VERSION 5.8 ;
BUSBITCHARS "[]" ;
DIVIDERCHAR "/" ;
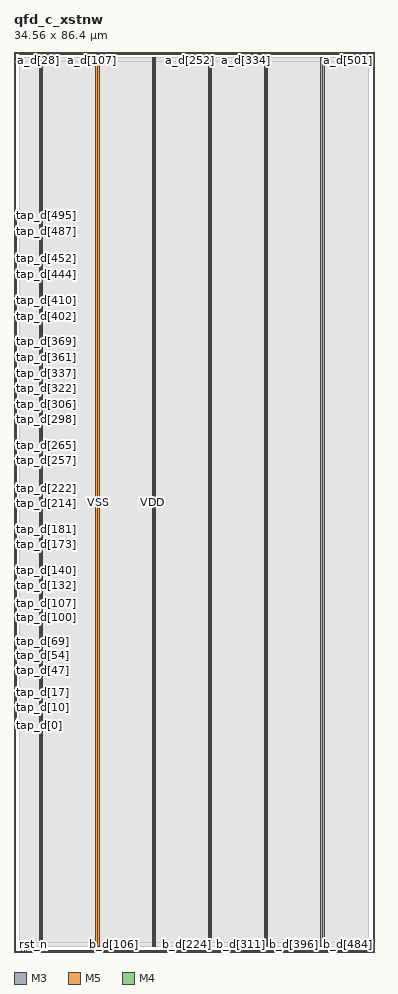
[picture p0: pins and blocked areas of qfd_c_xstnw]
MACRO qfd_c_xstnw
  CLASS BLOCK ;
  ORIGIN 0 0 ;
  FOREIGN qfd_c_xstnw 0 0 ;
  SIZE 34.56 BY 86.4 ;
  SYMMETRY X Y ;
  PIN b_d[0]
    DIRECTION INPUT ;
    USE SIGNAL ;
    PORT
      LAYER M3 ;
        RECT 3.273 0.000 3.297 0.192 ;
    END
  END b_d[0]
  PIN b_d[1]
    DIRECTION INPUT ;
    USE SIGNAL ;
    PORT
      LAYER M5 ;
        RECT 3.312 0.000 3.336 0.192 ;
    END
  END b_d[1]
  PIN b_d[2]
    DIRECTION INPUT ;
    USE SIGNAL ;
    PORT
      LAYER M3 ;
        RECT 3.381 0.000 3.405 0.192 ;
    END
  END b_d[2]
  PIN b_d[3]
    DIRECTION INPUT ;
    USE SIGNAL ;
    PORT
      LAYER M5 ;
        RECT 3.456 0.000 3.480 0.192 ;
    END
  END b_d[3]
  PIN b_d[4]
    DIRECTION INPUT ;
    USE SIGNAL ;
    PORT
      LAYER M3 ;
        RECT 3.489 0.000 3.513 0.192 ;
    END
  END b_d[4]
  PIN b_d[5]
    DIRECTION INPUT ;
    USE SIGNAL ;
    PORT
      LAYER M5 ;
        RECT 3.552 0.000 3.576 0.192 ;
    END
  END b_d[5]
  PIN b_d[6]
    DIRECTION INPUT ;
    USE SIGNAL ;
    PORT
      LAYER M3 ;
        RECT 3.633 0.000 3.657 0.192 ;
    END
  END b_d[6]
  PIN b_d[7]
    DIRECTION INPUT ;
    USE SIGNAL ;
    PORT
      LAYER M5 ;
        RECT 3.696 0.000 3.720 0.192 ;
    END
  END b_d[7]
  PIN b_d[8]
    DIRECTION INPUT ;
    USE SIGNAL ;
    PORT
      LAYER M3 ;
        RECT 3.741 0.000 3.765 0.192 ;
    END
  END b_d[8]
  PIN b_d[9]
    DIRECTION INPUT ;
    USE SIGNAL ;
    PORT
      LAYER M5 ;
        RECT 3.792 0.000 3.816 0.192 ;
    END
  END b_d[9]
  PIN b_d[10]
    DIRECTION INPUT ;
    USE SIGNAL ;
    PORT
      LAYER M3 ;
        RECT 3.849 0.000 3.873 0.192 ;
    END
  END b_d[10]
  PIN b_d[11]
    DIRECTION INPUT ;
    USE SIGNAL ;
    PORT
      LAYER M5 ;
        RECT 3.936 0.000 3.960 0.192 ;
    END
  END b_d[11]
  PIN b_d[12]
    DIRECTION INPUT ;
    USE SIGNAL ;
    PORT
      LAYER M3 ;
        RECT 3.957 0.000 3.981 0.192 ;
    END
  END b_d[12]
  PIN b_d[13]
    DIRECTION INPUT ;
    USE SIGNAL ;
    PORT
      LAYER M5 ;
        RECT 4.032 0.000 4.056 0.192 ;
    END
  END b_d[13]
  PIN b_d[14]
    DIRECTION INPUT ;
    USE SIGNAL ;
    PORT
      LAYER M3 ;
        RECT 4.101 0.000 4.125 0.192 ;
    END
  END b_d[14]
  PIN b_d[15]
    DIRECTION INPUT ;
    USE SIGNAL ;
    PORT
      LAYER M5 ;
        RECT 4.176 0.000 4.200 0.192 ;
    END
  END b_d[15]
  PIN b_d[16]
    DIRECTION INPUT ;
    USE SIGNAL ;
    PORT
      LAYER M3 ;
        RECT 4.209 0.000 4.233 0.192 ;
    END
  END b_d[16]
  PIN b_d[17]
    DIRECTION INPUT ;
    USE SIGNAL ;
    PORT
      LAYER M5 ;
        RECT 4.272 0.000 4.296 0.192 ;
    END
  END b_d[17]
  PIN b_d[18]
    DIRECTION INPUT ;
    USE SIGNAL ;
    PORT
      LAYER M3 ;
        RECT 4.317 0.000 4.341 0.192 ;
    END
  END b_d[18]
  PIN b_d[19]
    DIRECTION INPUT ;
    USE SIGNAL ;
    PORT
      LAYER M5 ;
        RECT 4.368 0.000 4.392 0.192 ;
    END
  END b_d[19]
  PIN b_d[20]
    DIRECTION INPUT ;
    USE SIGNAL ;
    PORT
      LAYER M3 ;
        RECT 4.461 0.000 4.485 0.192 ;
    END
  END b_d[20]
  PIN b_d[21]
    DIRECTION INPUT ;
    USE SIGNAL ;
    PORT
      LAYER M5 ;
        RECT 4.512 0.000 4.536 0.192 ;
    END
  END b_d[21]
  PIN b_d[22]
    DIRECTION INPUT ;
    USE SIGNAL ;
    PORT
      LAYER M3 ;
        RECT 4.569 0.000 4.593 0.192 ;
    END
  END b_d[22]
  PIN b_d[23]
    DIRECTION INPUT ;
    USE SIGNAL ;
    PORT
      LAYER M5 ;
        RECT 4.608 0.000 4.632 0.192 ;
    END
  END b_d[23]
  PIN b_d[24]
    DIRECTION INPUT ;
    USE SIGNAL ;
    PORT
      LAYER M3 ;
        RECT 4.677 0.000 4.701 0.192 ;
    END
  END b_d[24]
  PIN b_d[25]
    DIRECTION INPUT ;
    USE SIGNAL ;
    PORT
      LAYER M5 ;
        RECT 4.752 0.000 4.776 0.192 ;
    END
  END b_d[25]
  PIN b_d[26]
    DIRECTION INPUT ;
    USE SIGNAL ;
    PORT
      LAYER M3 ;
        RECT 4.821 0.000 4.845 0.192 ;
    END
  END b_d[26]
  PIN b_d[27]
    DIRECTION INPUT ;
    USE SIGNAL ;
    PORT
      LAYER M5 ;
        RECT 4.848 0.000 4.872 0.192 ;
    END
  END b_d[27]
  PIN b_d[28]
    DIRECTION INPUT ;
    USE SIGNAL ;
    PORT
      LAYER M3 ;
        RECT 4.929 0.000 4.953 0.192 ;
    END
  END b_d[28]
  PIN b_d[29]
    DIRECTION INPUT ;
    USE SIGNAL ;
    PORT
      LAYER M5 ;
        RECT 4.992 0.000 5.016 0.192 ;
    END
  END b_d[29]
  PIN b_d[30]
    DIRECTION INPUT ;
    USE SIGNAL ;
    PORT
      LAYER M3 ;
        RECT 5.037 0.000 5.061 0.192 ;
    END
  END b_d[30]
  PIN b_d[31]
    DIRECTION INPUT ;
    USE SIGNAL ;
    PORT
      LAYER M5 ;
        RECT 5.088 0.000 5.112 0.192 ;
    END
  END b_d[31]
  PIN b_d[32]
    DIRECTION INPUT ;
    USE SIGNAL ;
    PORT
      LAYER M3 ;
        RECT 5.181 0.000 5.205 0.192 ;
    END
  END b_d[32]
  PIN b_d[33]
    DIRECTION INPUT ;
    USE SIGNAL ;
    PORT
      LAYER M5 ;
        RECT 5.232 0.000 5.256 0.192 ;
    END
  END b_d[33]
  PIN b_d[34]
    DIRECTION INPUT ;
    USE SIGNAL ;
    PORT
      LAYER M3 ;
        RECT 5.289 0.000 5.313 0.192 ;
    END
  END b_d[34]
  PIN b_d[35]
    DIRECTION INPUT ;
    USE SIGNAL ;
    PORT
      LAYER M5 ;
        RECT 5.328 0.000 5.352 0.192 ;
    END
  END b_d[35]
  PIN b_d[36]
    DIRECTION INPUT ;
    USE SIGNAL ;
    PORT
      LAYER M3 ;
        RECT 5.397 0.000 5.421 0.192 ;
    END
  END b_d[36]
  PIN b_d[37]
    DIRECTION INPUT ;
    USE SIGNAL ;
    PORT
      LAYER M5 ;
        RECT 5.472 0.000 5.496 0.192 ;
    END
  END b_d[37]
  PIN b_d[38]
    DIRECTION INPUT ;
    USE SIGNAL ;
    PORT
      LAYER M3 ;
        RECT 5.541 0.000 5.565 0.192 ;
    END
  END b_d[38]
  PIN b_d[39]
    DIRECTION INPUT ;
    USE SIGNAL ;
    PORT
      LAYER M5 ;
        RECT 5.568 0.000 5.592 0.192 ;
    END
  END b_d[39]
  PIN b_d[40]
    DIRECTION INPUT ;
    USE SIGNAL ;
    PORT
      LAYER M3 ;
        RECT 5.649 0.000 5.673 0.192 ;
    END
  END b_d[40]
  PIN b_d[41]
    DIRECTION INPUT ;
    USE SIGNAL ;
    PORT
      LAYER M5 ;
        RECT 5.712 0.000 5.736 0.192 ;
    END
  END b_d[41]
  PIN b_d[42]
    DIRECTION INPUT ;
    USE SIGNAL ;
    PORT
      LAYER M3 ;
        RECT 5.757 0.000 5.781 0.192 ;
    END
  END b_d[42]
  PIN b_d[43]
    DIRECTION INPUT ;
    USE SIGNAL ;
    PORT
      LAYER M5 ;
        RECT 5.808 0.000 5.832 0.192 ;
    END
  END b_d[43]
  PIN b_d[44]
    DIRECTION INPUT ;
    USE SIGNAL ;
    PORT
      LAYER M3 ;
        RECT 5.865 0.000 5.889 0.192 ;
    END
  END b_d[44]
  PIN b_d[45]
    DIRECTION INPUT ;
    USE SIGNAL ;
    PORT
      LAYER M5 ;
        RECT 5.952 0.000 5.976 0.192 ;
    END
  END b_d[45]
  PIN b_d[46]
    DIRECTION INPUT ;
    USE SIGNAL ;
    PORT
      LAYER M3 ;
        RECT 6.009 0.000 6.033 0.192 ;
    END
  END b_d[46]
  PIN b_d[47]
    DIRECTION INPUT ;
    USE SIGNAL ;
    PORT
      LAYER M5 ;
        RECT 6.048 0.000 6.072 0.192 ;
    END
  END b_d[47]
  PIN b_d[48]
    DIRECTION INPUT ;
    USE SIGNAL ;
    PORT
      LAYER M3 ;
        RECT 6.117 0.000 6.141 0.192 ;
    END
  END b_d[48]
  PIN b_d[49]
    DIRECTION INPUT ;
    USE SIGNAL ;
    PORT
      LAYER M5 ;
        RECT 6.192 0.000 6.216 0.192 ;
    END
  END b_d[49]
  PIN b_d[50]
    DIRECTION INPUT ;
    USE SIGNAL ;
    PORT
      LAYER M3 ;
        RECT 6.225 0.000 6.249 0.192 ;
    END
  END b_d[50]
  PIN b_d[51]
    DIRECTION INPUT ;
    USE SIGNAL ;
    PORT
      LAYER M5 ;
        RECT 6.288 0.000 6.312 0.192 ;
    END
  END b_d[51]
  PIN b_d[52]
    DIRECTION INPUT ;
    USE SIGNAL ;
    PORT
      LAYER M3 ;
        RECT 6.369 0.000 6.393 0.192 ;
    END
  END b_d[52]
  PIN b_d[53]
    DIRECTION INPUT ;
    USE SIGNAL ;
    PORT
      LAYER M5 ;
        RECT 6.432 0.000 6.456 0.192 ;
    END
  END b_d[53]
  PIN b_d[54]
    DIRECTION INPUT ;
    USE SIGNAL ;
    PORT
      LAYER M3 ;
        RECT 6.477 0.000 6.501 0.192 ;
    END
  END b_d[54]
  PIN b_d[55]
    DIRECTION INPUT ;
    USE SIGNAL ;
    PORT
      LAYER M5 ;
        RECT 6.528 0.000 6.552 0.192 ;
    END
  END b_d[55]
  PIN b_d[56]
    DIRECTION INPUT ;
    USE SIGNAL ;
    PORT
      LAYER M3 ;
        RECT 6.585 0.000 6.609 0.192 ;
    END
  END b_d[56]
  PIN b_d[57]
    DIRECTION INPUT ;
    USE SIGNAL ;
    PORT
      LAYER M5 ;
        RECT 6.672 0.000 6.696 0.192 ;
    END
  END b_d[57]
  PIN b_d[58]
    DIRECTION INPUT ;
    USE SIGNAL ;
    PORT
      LAYER M3 ;
        RECT 6.729 0.000 6.753 0.192 ;
    END
  END b_d[58]
  PIN b_d[59]
    DIRECTION INPUT ;
    USE SIGNAL ;
    PORT
      LAYER M5 ;
        RECT 6.768 0.000 6.792 0.192 ;
    END
  END b_d[59]
  PIN b_d[60]
    DIRECTION INPUT ;
    USE SIGNAL ;
    PORT
      LAYER M3 ;
        RECT 6.837 0.000 6.861 0.192 ;
    END
  END b_d[60]
  PIN b_d[61]
    DIRECTION INPUT ;
    USE SIGNAL ;
    PORT
      LAYER M5 ;
        RECT 6.912 0.000 6.936 0.192 ;
    END
  END b_d[61]
  PIN b_d[62]
    DIRECTION INPUT ;
    USE SIGNAL ;
    PORT
      LAYER M3 ;
        RECT 6.945 0.000 6.969 0.192 ;
    END
  END b_d[62]
  PIN b_d[63]
    DIRECTION INPUT ;
    USE SIGNAL ;
    PORT
      LAYER M5 ;
        RECT 7.008 0.000 7.032 0.192 ;
    END
  END b_d[63]
  PIN b_d[64]
    DIRECTION INPUT ;
    USE SIGNAL ;
    PORT
      LAYER M3 ;
        RECT 7.089 0.000 7.113 0.192 ;
    END
  END b_d[64]
  PIN b_d[65]
    DIRECTION INPUT ;
    USE SIGNAL ;
    PORT
      LAYER M5 ;
        RECT 7.152 0.000 7.176 0.192 ;
    END
  END b_d[65]
  PIN b_d[66]
    DIRECTION INPUT ;
    USE SIGNAL ;
    PORT
      LAYER M3 ;
        RECT 7.197 0.000 7.221 0.192 ;
    END
  END b_d[66]
  PIN b_d[67]
    DIRECTION INPUT ;
    USE SIGNAL ;
    PORT
      LAYER M5 ;
        RECT 7.248 0.000 7.272 0.192 ;
    END
  END b_d[67]
  PIN b_d[68]
    DIRECTION INPUT ;
    USE SIGNAL ;
    PORT
      LAYER M3 ;
        RECT 7.305 0.000 7.329 0.192 ;
    END
  END b_d[68]
  PIN b_d[69]
    DIRECTION INPUT ;
    USE SIGNAL ;
    PORT
      LAYER M5 ;
        RECT 7.392 0.000 7.416 0.192 ;
    END
  END b_d[69]
  PIN b_d[70]
    DIRECTION INPUT ;
    USE SIGNAL ;
    PORT
      LAYER M3 ;
        RECT 7.449 0.000 7.473 0.192 ;
    END
  END b_d[70]
  PIN b_d[71]
    DIRECTION INPUT ;
    USE SIGNAL ;
    PORT
      LAYER M5 ;
        RECT 7.488 0.000 7.512 0.192 ;
    END
  END b_d[71]
  PIN b_d[72]
    DIRECTION INPUT ;
    USE SIGNAL ;
    PORT
      LAYER M3 ;
        RECT 7.557 0.000 7.581 0.192 ;
    END
  END b_d[72]
  PIN b_d[73]
    DIRECTION INPUT ;
    USE SIGNAL ;
    PORT
      LAYER M5 ;
        RECT 7.632 0.000 7.656 0.192 ;
    END
  END b_d[73]
  PIN b_d[74]
    DIRECTION INPUT ;
    USE SIGNAL ;
    PORT
      LAYER M3 ;
        RECT 7.665 0.000 7.689 0.192 ;
    END
  END b_d[74]
  PIN b_d[75]
    DIRECTION INPUT ;
    USE SIGNAL ;
    PORT
      LAYER M5 ;
        RECT 7.728 0.000 7.752 0.192 ;
    END
  END b_d[75]
  PIN b_d[76]
    DIRECTION INPUT ;
    USE SIGNAL ;
    PORT
      LAYER M3 ;
        RECT 7.809 0.000 7.833 0.192 ;
    END
  END b_d[76]
  PIN b_d[77]
    DIRECTION INPUT ;
    USE SIGNAL ;
    PORT
      LAYER M5 ;
        RECT 7.872 0.000 7.896 0.192 ;
    END
  END b_d[77]
  PIN b_d[78]
    DIRECTION INPUT ;
    USE SIGNAL ;
    PORT
      LAYER M3 ;
        RECT 7.917 0.000 7.941 0.192 ;
    END
  END b_d[78]
  PIN b_d[79]
    DIRECTION INPUT ;
    USE SIGNAL ;
    PORT
      LAYER M5 ;
        RECT 7.968 0.000 7.992 0.192 ;
    END
  END b_d[79]
  PIN b_d[80]
    DIRECTION INPUT ;
    USE SIGNAL ;
    PORT
      LAYER M3 ;
        RECT 8.025 0.000 8.049 0.192 ;
    END
  END b_d[80]
  PIN b_d[81]
    DIRECTION INPUT ;
    USE SIGNAL ;
    PORT
      LAYER M5 ;
        RECT 8.112 0.000 8.136 0.192 ;
    END
  END b_d[81]
  PIN b_d[82]
    DIRECTION INPUT ;
    USE SIGNAL ;
    PORT
      LAYER M3 ;
        RECT 8.133 0.000 8.157 0.192 ;
    END
  END b_d[82]
  PIN b_d[83]
    DIRECTION INPUT ;
    USE SIGNAL ;
    PORT
      LAYER M5 ;
        RECT 8.208 0.000 8.232 0.192 ;
    END
  END b_d[83]
  PIN b_d[84]
    DIRECTION INPUT ;
    USE SIGNAL ;
    PORT
      LAYER M3 ;
        RECT 8.277 0.000 8.301 0.192 ;
    END
  END b_d[84]
  PIN b_d[85]
    DIRECTION INPUT ;
    USE SIGNAL ;
    PORT
      LAYER M5 ;
        RECT 8.352 0.000 8.376 0.192 ;
    END
  END b_d[85]
  PIN b_d[86]
    DIRECTION INPUT ;
    USE SIGNAL ;
    PORT
      LAYER M3 ;
        RECT 8.385 0.000 8.409 0.192 ;
    END
  END b_d[86]
  PIN b_d[87]
    DIRECTION INPUT ;
    USE SIGNAL ;
    PORT
      LAYER M5 ;
        RECT 8.448 0.000 8.472 0.192 ;
    END
  END b_d[87]
  PIN b_d[88]
    DIRECTION INPUT ;
    USE SIGNAL ;
    PORT
      LAYER M3 ;
        RECT 8.493 0.000 8.517 0.192 ;
    END
  END b_d[88]
  PIN b_d[89]
    DIRECTION INPUT ;
    USE SIGNAL ;
    PORT
      LAYER M5 ;
        RECT 8.544 0.000 8.568 0.192 ;
    END
  END b_d[89]
  PIN b_d[90]
    DIRECTION INPUT ;
    USE SIGNAL ;
    PORT
      LAYER M3 ;
        RECT 8.637 0.000 8.661 0.192 ;
    END
  END b_d[90]
  PIN b_d[91]
    DIRECTION INPUT ;
    USE SIGNAL ;
    PORT
      LAYER M5 ;
        RECT 8.688 0.000 8.712 0.192 ;
    END
  END b_d[91]
  PIN b_d[92]
    DIRECTION INPUT ;
    USE SIGNAL ;
    PORT
      LAYER M3 ;
        RECT 8.745 0.000 8.769 0.192 ;
    END
  END b_d[92]
  PIN b_d[93]
    DIRECTION INPUT ;
    USE SIGNAL ;
    PORT
      LAYER M5 ;
        RECT 8.784 0.000 8.808 0.192 ;
    END
  END b_d[93]
  PIN b_d[94]
    DIRECTION INPUT ;
    USE SIGNAL ;
    PORT
      LAYER M3 ;
        RECT 8.853 0.000 8.877 0.192 ;
    END
  END b_d[94]
  PIN b_d[95]
    DIRECTION INPUT ;
    USE SIGNAL ;
    PORT
      LAYER M5 ;
        RECT 8.928 0.000 8.952 0.192 ;
    END
  END b_d[95]
  PIN b_d[96]
    DIRECTION INPUT ;
    USE SIGNAL ;
    PORT
      LAYER M3 ;
        RECT 8.997 0.000 9.021 0.192 ;
    END
  END b_d[96]
  PIN b_d[97]
    DIRECTION INPUT ;
    USE SIGNAL ;
    PORT
      LAYER M5 ;
        RECT 9.024 0.000 9.048 0.192 ;
    END
  END b_d[97]
  PIN b_d[98]
    DIRECTION INPUT ;
    USE SIGNAL ;
    PORT
      LAYER M3 ;
        RECT 9.105 0.000 9.129 0.192 ;
    END
  END b_d[98]
  PIN b_d[99]
    DIRECTION INPUT ;
    USE SIGNAL ;
    PORT
      LAYER M5 ;
        RECT 9.168 0.000 9.192 0.192 ;
    END
  END b_d[99]
  PIN b_d[100]
    DIRECTION INPUT ;
    USE SIGNAL ;
    PORT
      LAYER M3 ;
        RECT 9.213 0.000 9.237 0.192 ;
    END
  END b_d[100]
  PIN b_d[101]
    DIRECTION INPUT ;
    USE SIGNAL ;
    PORT
      LAYER M5 ;
        RECT 9.264 0.000 9.288 0.192 ;
    END
  END b_d[101]
  PIN b_d[102]
    DIRECTION INPUT ;
    USE SIGNAL ;
    PORT
      LAYER M3 ;
        RECT 9.357 0.000 9.381 0.192 ;
    END
  END b_d[102]
  PIN b_d[103]
    DIRECTION INPUT ;
    USE SIGNAL ;
    PORT
      LAYER M5 ;
        RECT 9.408 0.000 9.432 0.192 ;
    END
  END b_d[103]
  PIN b_d[104]
    DIRECTION INPUT ;
    USE SIGNAL ;
    PORT
      LAYER M3 ;
        RECT 9.465 0.000 9.489 0.192 ;
    END
  END b_d[104]
  PIN b_d[105]
    DIRECTION INPUT ;
    USE SIGNAL ;
    PORT
      LAYER M5 ;
        RECT 9.504 0.000 9.528 0.192 ;
    END
  END b_d[105]
  PIN b_d[106]
    DIRECTION INPUT ;
    USE SIGNAL ;
    PORT
      LAYER M3 ;
        RECT 9.573 0.000 9.597 0.192 ;
    END
  END b_d[106]
  PIN b_d[107]
    DIRECTION INPUT ;
    USE SIGNAL ;
    PORT
      LAYER M5 ;
        RECT 9.648 0.000 9.672 0.192 ;
    END
  END b_d[107]
  PIN b_d[108]
    DIRECTION INPUT ;
    USE SIGNAL ;
    PORT
      LAYER M3 ;
        RECT 9.717 0.000 9.741 0.192 ;
    END
  END b_d[108]
  PIN b_d[109]
    DIRECTION INPUT ;
    USE SIGNAL ;
    PORT
      LAYER M5 ;
        RECT 9.744 0.000 9.768 0.192 ;
    END
  END b_d[109]
  PIN b_d[110]
    DIRECTION INPUT ;
    USE SIGNAL ;
    PORT
      LAYER M3 ;
        RECT 9.825 0.000 9.849 0.192 ;
    END
  END b_d[110]
  PIN b_d[111]
    DIRECTION INPUT ;
    USE SIGNAL ;
    PORT
      LAYER M5 ;
        RECT 9.888 0.000 9.912 0.192 ;
    END
  END b_d[111]
  PIN b_d[112]
    DIRECTION INPUT ;
    USE SIGNAL ;
    PORT
      LAYER M3 ;
        RECT 9.933 0.000 9.957 0.192 ;
    END
  END b_d[112]
  PIN b_d[113]
    DIRECTION INPUT ;
    USE SIGNAL ;
    PORT
      LAYER M5 ;
        RECT 9.984 0.000 10.008 0.192 ;
    END
  END b_d[113]
  PIN b_d[114]
    DIRECTION INPUT ;
    USE SIGNAL ;
    PORT
      LAYER M3 ;
        RECT 10.041 0.000 10.065 0.192 ;
    END
  END b_d[114]
  PIN b_d[115]
    DIRECTION INPUT ;
    USE SIGNAL ;
    PORT
      LAYER M5 ;
        RECT 10.128 0.000 10.152 0.192 ;
    END
  END b_d[115]
  PIN b_d[116]
    DIRECTION INPUT ;
    USE SIGNAL ;
    PORT
      LAYER M3 ;
        RECT 10.185 0.000 10.209 0.192 ;
    END
  END b_d[116]
  PIN b_d[117]
    DIRECTION INPUT ;
    USE SIGNAL ;
    PORT
      LAYER M5 ;
        RECT 10.224 0.000 10.248 0.192 ;
    END
  END b_d[117]
  PIN b_d[118]
    DIRECTION INPUT ;
    USE SIGNAL ;
    PORT
      LAYER M3 ;
        RECT 10.293 0.000 10.317 0.192 ;
    END
  END b_d[118]
  PIN b_d[119]
    DIRECTION INPUT ;
    USE SIGNAL ;
    PORT
      LAYER M5 ;
        RECT 10.368 0.000 10.392 0.192 ;
    END
  END b_d[119]
  PIN b_d[120]
    DIRECTION INPUT ;
    USE SIGNAL ;
    PORT
      LAYER M3 ;
        RECT 10.401 0.000 10.425 0.192 ;
    END
  END b_d[120]
  PIN b_d[121]
    DIRECTION INPUT ;
    USE SIGNAL ;
    PORT
      LAYER M5 ;
        RECT 10.464 0.000 10.488 0.192 ;
    END
  END b_d[121]
  PIN b_d[122]
    DIRECTION INPUT ;
    USE SIGNAL ;
    PORT
      LAYER M3 ;
        RECT 10.545 0.000 10.569 0.192 ;
    END
  END b_d[122]
  PIN b_d[123]
    DIRECTION INPUT ;
    USE SIGNAL ;
    PORT
      LAYER M5 ;
        RECT 10.608 0.000 10.632 0.192 ;
    END
  END b_d[123]
  PIN b_d[124]
    DIRECTION INPUT ;
    USE SIGNAL ;
    PORT
      LAYER M3 ;
        RECT 10.653 0.000 10.677 0.192 ;
    END
  END b_d[124]
  PIN b_d[125]
    DIRECTION INPUT ;
    USE SIGNAL ;
    PORT
      LAYER M5 ;
        RECT 10.704 0.000 10.728 0.192 ;
    END
  END b_d[125]
  PIN b_d[126]
    DIRECTION INPUT ;
    USE SIGNAL ;
    PORT
      LAYER M3 ;
        RECT 10.761 0.000 10.785 0.192 ;
    END
  END b_d[126]
  PIN b_d[127]
    DIRECTION INPUT ;
    USE SIGNAL ;
    PORT
      LAYER M5 ;
        RECT 10.848 0.000 10.872 0.192 ;
    END
  END b_d[127]
  PIN b_d[128]
    DIRECTION INPUT ;
    USE SIGNAL ;
    PORT
      LAYER M3 ;
        RECT 10.905 0.000 10.929 0.192 ;
    END
  END b_d[128]
  PIN b_d[129]
    DIRECTION INPUT ;
    USE SIGNAL ;
    PORT
      LAYER M5 ;
        RECT 10.944 0.000 10.968 0.192 ;
    END
  END b_d[129]
  PIN b_d[130]
    DIRECTION INPUT ;
    USE SIGNAL ;
    PORT
      LAYER M3 ;
        RECT 11.013 0.000 11.037 0.192 ;
    END
  END b_d[130]
  PIN b_d[131]
    DIRECTION INPUT ;
    USE SIGNAL ;
    PORT
      LAYER M5 ;
        RECT 11.088 0.000 11.112 0.192 ;
    END
  END b_d[131]
  PIN b_d[132]
    DIRECTION INPUT ;
    USE SIGNAL ;
    PORT
      LAYER M3 ;
        RECT 11.121 0.000 11.145 0.192 ;
    END
  END b_d[132]
  PIN b_d[133]
    DIRECTION INPUT ;
    USE SIGNAL ;
    PORT
      LAYER M5 ;
        RECT 11.184 0.000 11.208 0.192 ;
    END
  END b_d[133]
  PIN b_d[134]
    DIRECTION INPUT ;
    USE SIGNAL ;
    PORT
      LAYER M3 ;
        RECT 11.265 0.000 11.289 0.192 ;
    END
  END b_d[134]
  PIN b_d[135]
    DIRECTION INPUT ;
    USE SIGNAL ;
    PORT
      LAYER M5 ;
        RECT 11.328 0.000 11.352 0.192 ;
    END
  END b_d[135]
  PIN b_d[136]
    DIRECTION INPUT ;
    USE SIGNAL ;
    PORT
      LAYER M3 ;
        RECT 11.373 0.000 11.397 0.192 ;
    END
  END b_d[136]
  PIN b_d[137]
    DIRECTION INPUT ;
    USE SIGNAL ;
    PORT
      LAYER M5 ;
        RECT 11.424 0.000 11.448 0.192 ;
    END
  END b_d[137]
  PIN b_d[138]
    DIRECTION INPUT ;
    USE SIGNAL ;
    PORT
      LAYER M3 ;
        RECT 11.481 0.000 11.505 0.192 ;
    END
  END b_d[138]
  PIN b_d[139]
    DIRECTION INPUT ;
    USE SIGNAL ;
    PORT
      LAYER M5 ;
        RECT 11.568 0.000 11.592 0.192 ;
    END
  END b_d[139]
  PIN b_d[140]
    DIRECTION INPUT ;
    USE SIGNAL ;
    PORT
      LAYER M3 ;
        RECT 11.625 0.000 11.649 0.192 ;
    END
  END b_d[140]
  PIN b_d[141]
    DIRECTION INPUT ;
    USE SIGNAL ;
    PORT
      LAYER M5 ;
        RECT 11.664 0.000 11.688 0.192 ;
    END
  END b_d[141]
  PIN b_d[142]
    DIRECTION INPUT ;
    USE SIGNAL ;
    PORT
      LAYER M3 ;
        RECT 11.733 0.000 11.757 0.192 ;
    END
  END b_d[142]
  PIN b_d[143]
    DIRECTION INPUT ;
    USE SIGNAL ;
    PORT
      LAYER M5 ;
        RECT 11.808 0.000 11.832 0.192 ;
    END
  END b_d[143]
  PIN b_d[144]
    DIRECTION INPUT ;
    USE SIGNAL ;
    PORT
      LAYER M3 ;
        RECT 11.841 0.000 11.865 0.192 ;
    END
  END b_d[144]
  PIN b_d[145]
    DIRECTION INPUT ;
    USE SIGNAL ;
    PORT
      LAYER M5 ;
        RECT 11.904 0.000 11.928 0.192 ;
    END
  END b_d[145]
  PIN b_d[146]
    DIRECTION INPUT ;
    USE SIGNAL ;
    PORT
      LAYER M3 ;
        RECT 11.949 0.000 11.973 0.192 ;
    END
  END b_d[146]
  PIN b_d[147]
    DIRECTION INPUT ;
    USE SIGNAL ;
    PORT
      LAYER M5 ;
        RECT 12.048 0.000 12.072 0.192 ;
    END
  END b_d[147]
  PIN b_d[148]
    DIRECTION INPUT ;
    USE SIGNAL ;
    PORT
      LAYER M3 ;
        RECT 12.093 0.000 12.117 0.192 ;
    END
  END b_d[148]
  PIN b_d[149]
    DIRECTION INPUT ;
    USE SIGNAL ;
    PORT
      LAYER M5 ;
        RECT 12.144 0.000 12.168 0.192 ;
    END
  END b_d[149]
  PIN b_d[150]
    DIRECTION INPUT ;
    USE SIGNAL ;
    PORT
      LAYER M3 ;
        RECT 12.201 0.000 12.225 0.192 ;
    END
  END b_d[150]
  PIN b_d[151]
    DIRECTION INPUT ;
    USE SIGNAL ;
    PORT
      LAYER M5 ;
        RECT 12.288 0.000 12.312 0.192 ;
    END
  END b_d[151]
  PIN b_d[152]
    DIRECTION INPUT ;
    USE SIGNAL ;
    PORT
      LAYER M3 ;
        RECT 12.309 0.000 12.333 0.192 ;
    END
  END b_d[152]
  PIN b_d[153]
    DIRECTION INPUT ;
    USE SIGNAL ;
    PORT
      LAYER M5 ;
        RECT 12.384 0.000 12.408 0.192 ;
    END
  END b_d[153]
  PIN b_d[154]
    DIRECTION INPUT ;
    USE SIGNAL ;
    PORT
      LAYER M3 ;
        RECT 12.453 0.000 12.477 0.192 ;
    END
  END b_d[154]
  PIN b_d[155]
    DIRECTION INPUT ;
    USE SIGNAL ;
    PORT
      LAYER M5 ;
        RECT 12.480 0.000 12.504 0.192 ;
    END
  END b_d[155]
  PIN b_d[156]
    DIRECTION INPUT ;
    USE SIGNAL ;
    PORT
      LAYER M3 ;
        RECT 12.561 0.000 12.585 0.192 ;
    END
  END b_d[156]
  PIN b_d[157]
    DIRECTION INPUT ;
    USE SIGNAL ;
    PORT
      LAYER M5 ;
        RECT 12.624 0.000 12.648 0.192 ;
    END
  END b_d[157]
  PIN b_d[158]
    DIRECTION INPUT ;
    USE SIGNAL ;
    PORT
      LAYER M3 ;
        RECT 12.669 0.000 12.693 0.192 ;
    END
  END b_d[158]
  PIN b_d[159]
    DIRECTION INPUT ;
    USE SIGNAL ;
    PORT
      LAYER M5 ;
        RECT 12.720 0.000 12.744 0.192 ;
    END
  END b_d[159]
  PIN b_d[160]
    DIRECTION INPUT ;
    USE SIGNAL ;
    PORT
      LAYER M3 ;
        RECT 12.813 0.000 12.837 0.192 ;
    END
  END b_d[160]
  PIN b_d[161]
    DIRECTION INPUT ;
    USE SIGNAL ;
    PORT
      LAYER M5 ;
        RECT 12.864 0.000 12.888 0.192 ;
    END
  END b_d[161]
  PIN b_d[162]
    DIRECTION INPUT ;
    USE SIGNAL ;
    PORT
      LAYER M3 ;
        RECT 12.921 0.000 12.945 0.192 ;
    END
  END b_d[162]
  PIN b_d[163]
    DIRECTION INPUT ;
    USE SIGNAL ;
    PORT
      LAYER M5 ;
        RECT 12.960 0.000 12.984 0.192 ;
    END
  END b_d[163]
  PIN b_d[164]
    DIRECTION INPUT ;
    USE SIGNAL ;
    PORT
      LAYER M3 ;
        RECT 13.029 0.000 13.053 0.192 ;
    END
  END b_d[164]
  PIN b_d[165]
    DIRECTION INPUT ;
    USE SIGNAL ;
    PORT
      LAYER M5 ;
        RECT 13.104 0.000 13.128 0.192 ;
    END
  END b_d[165]
  PIN b_d[166]
    DIRECTION INPUT ;
    USE SIGNAL ;
    PORT
      LAYER M3 ;
        RECT 13.173 0.000 13.197 0.192 ;
    END
  END b_d[166]
  PIN b_d[167]
    DIRECTION INPUT ;
    USE SIGNAL ;
    PORT
      LAYER M5 ;
        RECT 13.200 0.000 13.224 0.192 ;
    END
  END b_d[167]
  PIN b_d[168]
    DIRECTION INPUT ;
    USE SIGNAL ;
    PORT
      LAYER M3 ;
        RECT 13.281 0.000 13.305 0.192 ;
    END
  END b_d[168]
  PIN b_d[169]
    DIRECTION INPUT ;
    USE SIGNAL ;
    PORT
      LAYER M5 ;
        RECT 13.344 0.000 13.368 0.192 ;
    END
  END b_d[169]
  PIN b_d[170]
    DIRECTION INPUT ;
    USE SIGNAL ;
    PORT
      LAYER M3 ;
        RECT 13.389 0.000 13.413 0.192 ;
    END
  END b_d[170]
  PIN b_d[171]
    DIRECTION INPUT ;
    USE SIGNAL ;
    PORT
      LAYER M5 ;
        RECT 13.440 0.000 13.464 0.192 ;
    END
  END b_d[171]
  PIN b_d[172]
    DIRECTION INPUT ;
    USE SIGNAL ;
    PORT
      LAYER M3 ;
        RECT 13.533 0.000 13.557 0.192 ;
    END
  END b_d[172]
  PIN b_d[173]
    DIRECTION INPUT ;
    USE SIGNAL ;
    PORT
      LAYER M5 ;
        RECT 13.584 0.000 13.608 0.192 ;
    END
  END b_d[173]
  PIN b_d[174]
    DIRECTION INPUT ;
    USE SIGNAL ;
    PORT
      LAYER M3 ;
        RECT 13.641 0.000 13.665 0.192 ;
    END
  END b_d[174]
  PIN b_d[175]
    DIRECTION INPUT ;
    USE SIGNAL ;
    PORT
      LAYER M5 ;
        RECT 13.680 0.000 13.704 0.192 ;
    END
  END b_d[175]
  PIN b_d[176]
    DIRECTION INPUT ;
    USE SIGNAL ;
    PORT
      LAYER M3 ;
        RECT 13.749 0.000 13.773 0.192 ;
    END
  END b_d[176]
  PIN b_d[177]
    DIRECTION INPUT ;
    USE SIGNAL ;
    PORT
      LAYER M5 ;
        RECT 13.824 0.000 13.848 0.192 ;
    END
  END b_d[177]
  PIN b_d[178]
    DIRECTION INPUT ;
    USE SIGNAL ;
    PORT
      LAYER M3 ;
        RECT 13.893 0.000 13.917 0.192 ;
    END
  END b_d[178]
  PIN b_d[179]
    DIRECTION INPUT ;
    USE SIGNAL ;
    PORT
      LAYER M5 ;
        RECT 13.920 0.000 13.944 0.192 ;
    END
  END b_d[179]
  PIN b_d[180]
    DIRECTION INPUT ;
    USE SIGNAL ;
    PORT
      LAYER M3 ;
        RECT 14.001 0.000 14.025 0.192 ;
    END
  END b_d[180]
  PIN b_d[181]
    DIRECTION INPUT ;
    USE SIGNAL ;
    PORT
      LAYER M5 ;
        RECT 14.064 0.000 14.088 0.192 ;
    END
  END b_d[181]
  PIN b_d[182]
    DIRECTION INPUT ;
    USE SIGNAL ;
    PORT
      LAYER M3 ;
        RECT 14.109 0.000 14.133 0.192 ;
    END
  END b_d[182]
  PIN b_d[183]
    DIRECTION INPUT ;
    USE SIGNAL ;
    PORT
      LAYER M5 ;
        RECT 14.160 0.000 14.184 0.192 ;
    END
  END b_d[183]
  PIN b_d[184]
    DIRECTION INPUT ;
    USE SIGNAL ;
    PORT
      LAYER M3 ;
        RECT 14.217 0.000 14.241 0.192 ;
    END
  END b_d[184]
  PIN b_d[185]
    DIRECTION INPUT ;
    USE SIGNAL ;
    PORT
      LAYER M5 ;
        RECT 14.304 0.000 14.328 0.192 ;
    END
  END b_d[185]
  PIN b_d[186]
    DIRECTION INPUT ;
    USE SIGNAL ;
    PORT
      LAYER M3 ;
        RECT 14.361 0.000 14.385 0.192 ;
    END
  END b_d[186]
  PIN b_d[187]
    DIRECTION INPUT ;
    USE SIGNAL ;
    PORT
      LAYER M5 ;
        RECT 14.400 0.000 14.424 0.192 ;
    END
  END b_d[187]
  PIN b_d[188]
    DIRECTION INPUT ;
    USE SIGNAL ;
    PORT
      LAYER M3 ;
        RECT 14.469 0.000 14.493 0.192 ;
    END
  END b_d[188]
  PIN b_d[189]
    DIRECTION INPUT ;
    USE SIGNAL ;
    PORT
      LAYER M5 ;
        RECT 14.544 0.000 14.568 0.192 ;
    END
  END b_d[189]
  PIN b_d[190]
    DIRECTION INPUT ;
    USE SIGNAL ;
    PORT
      LAYER M3 ;
        RECT 14.577 0.000 14.601 0.192 ;
    END
  END b_d[190]
  PIN b_d[191]
    DIRECTION INPUT ;
    USE SIGNAL ;
    PORT
      LAYER M5 ;
        RECT 14.640 0.000 14.664 0.192 ;
    END
  END b_d[191]
  PIN b_d[192]
    DIRECTION INPUT ;
    USE SIGNAL ;
    PORT
      LAYER M3 ;
        RECT 14.721 0.000 14.745 0.192 ;
    END
  END b_d[192]
  PIN b_d[193]
    DIRECTION INPUT ;
    USE SIGNAL ;
    PORT
      LAYER M5 ;
        RECT 14.784 0.000 14.808 0.192 ;
    END
  END b_d[193]
  PIN b_d[194]
    DIRECTION INPUT ;
    USE SIGNAL ;
    PORT
      LAYER M3 ;
        RECT 14.829 0.000 14.853 0.192 ;
    END
  END b_d[194]
  PIN b_d[195]
    DIRECTION INPUT ;
    USE SIGNAL ;
    PORT
      LAYER M5 ;
        RECT 14.880 0.000 14.904 0.192 ;
    END
  END b_d[195]
  PIN b_d[196]
    DIRECTION INPUT ;
    USE SIGNAL ;
    PORT
      LAYER M3 ;
        RECT 14.937 0.000 14.961 0.192 ;
    END
  END b_d[196]
  PIN b_d[197]
    DIRECTION INPUT ;
    USE SIGNAL ;
    PORT
      LAYER M5 ;
        RECT 15.024 0.000 15.048 0.192 ;
    END
  END b_d[197]
  PIN b_d[198]
    DIRECTION INPUT ;
    USE SIGNAL ;
    PORT
      LAYER M3 ;
        RECT 15.081 0.000 15.105 0.192 ;
    END
  END b_d[198]
  PIN b_d[199]
    DIRECTION INPUT ;
    USE SIGNAL ;
    PORT
      LAYER M5 ;
        RECT 15.120 0.000 15.144 0.192 ;
    END
  END b_d[199]
  PIN b_d[200]
    DIRECTION INPUT ;
    USE SIGNAL ;
    PORT
      LAYER M3 ;
        RECT 15.189 0.000 15.213 0.192 ;
    END
  END b_d[200]
  PIN b_d[201]
    DIRECTION INPUT ;
    USE SIGNAL ;
    PORT
      LAYER M5 ;
        RECT 15.264 0.000 15.288 0.192 ;
    END
  END b_d[201]
  PIN b_d[202]
    DIRECTION INPUT ;
    USE SIGNAL ;
    PORT
      LAYER M3 ;
        RECT 15.297 0.000 15.321 0.192 ;
    END
  END b_d[202]
  PIN b_d[203]
    DIRECTION INPUT ;
    USE SIGNAL ;
    PORT
      LAYER M5 ;
        RECT 15.360 0.000 15.384 0.192 ;
    END
  END b_d[203]
  PIN b_d[204]
    DIRECTION INPUT ;
    USE SIGNAL ;
    PORT
      LAYER M3 ;
        RECT 15.441 0.000 15.465 0.192 ;
    END
  END b_d[204]
  PIN b_d[205]
    DIRECTION INPUT ;
    USE SIGNAL ;
    PORT
      LAYER M5 ;
        RECT 15.504 0.000 15.528 0.192 ;
    END
  END b_d[205]
  PIN b_d[206]
    DIRECTION INPUT ;
    USE SIGNAL ;
    PORT
      LAYER M3 ;
        RECT 15.549 0.000 15.573 0.192 ;
    END
  END b_d[206]
  PIN b_d[207]
    DIRECTION INPUT ;
    USE SIGNAL ;
    PORT
      LAYER M5 ;
        RECT 15.600 0.000 15.624 0.192 ;
    END
  END b_d[207]
  PIN b_d[208]
    DIRECTION INPUT ;
    USE SIGNAL ;
    PORT
      LAYER M3 ;
        RECT 15.657 0.000 15.681 0.192 ;
    END
  END b_d[208]
  PIN b_d[209]
    DIRECTION INPUT ;
    USE SIGNAL ;
    PORT
      LAYER M5 ;
        RECT 15.744 0.000 15.768 0.192 ;
    END
  END b_d[209]
  PIN b_d[210]
    DIRECTION INPUT ;
    USE SIGNAL ;
    PORT
      LAYER M3 ;
        RECT 15.801 0.000 15.825 0.192 ;
    END
  END b_d[210]
  PIN b_d[211]
    DIRECTION INPUT ;
    USE SIGNAL ;
    PORT
      LAYER M5 ;
        RECT 15.840 0.000 15.864 0.192 ;
    END
  END b_d[211]
  PIN b_d[212]
    DIRECTION INPUT ;
    USE SIGNAL ;
    PORT
      LAYER M3 ;
        RECT 15.909 0.000 15.933 0.192 ;
    END
  END b_d[212]
  PIN b_d[213]
    DIRECTION INPUT ;
    USE SIGNAL ;
    PORT
      LAYER M5 ;
        RECT 15.984 0.000 16.008 0.192 ;
    END
  END b_d[213]
  PIN b_d[214]
    DIRECTION INPUT ;
    USE SIGNAL ;
    PORT
      LAYER M3 ;
        RECT 16.017 0.000 16.041 0.192 ;
    END
  END b_d[214]
  PIN b_d[215]
    DIRECTION INPUT ;
    USE SIGNAL ;
    PORT
      LAYER M5 ;
        RECT 16.080 0.000 16.104 0.192 ;
    END
  END b_d[215]
  PIN b_d[216]
    DIRECTION INPUT ;
    USE SIGNAL ;
    PORT
      LAYER M3 ;
        RECT 16.125 0.000 16.149 0.192 ;
    END
  END b_d[216]
  PIN b_d[217]
    DIRECTION INPUT ;
    USE SIGNAL ;
    PORT
      LAYER M5 ;
        RECT 16.224 0.000 16.248 0.192 ;
    END
  END b_d[217]
  PIN b_d[218]
    DIRECTION INPUT ;
    USE SIGNAL ;
    PORT
      LAYER M3 ;
        RECT 16.269 0.000 16.293 0.192 ;
    END
  END b_d[218]
  PIN b_d[219]
    DIRECTION INPUT ;
    USE SIGNAL ;
    PORT
      LAYER M5 ;
        RECT 16.320 0.000 16.344 0.192 ;
    END
  END b_d[219]
  PIN b_d[220]
    DIRECTION INPUT ;
    USE SIGNAL ;
    PORT
      LAYER M3 ;
        RECT 16.377 0.000 16.401 0.192 ;
    END
  END b_d[220]
  PIN b_d[221]
    DIRECTION INPUT ;
    USE SIGNAL ;
    PORT
      LAYER M5 ;
        RECT 16.464 0.000 16.488 0.192 ;
    END
  END b_d[221]
  PIN b_d[222]
    DIRECTION INPUT ;
    USE SIGNAL ;
    PORT
      LAYER M3 ;
        RECT 16.485 0.000 16.509 0.192 ;
    END
  END b_d[222]
  PIN b_d[223]
    DIRECTION INPUT ;
    USE SIGNAL ;
    PORT
      LAYER M5 ;
        RECT 16.560 0.000 16.584 0.192 ;
    END
  END b_d[223]
  PIN b_d[224]
    DIRECTION INPUT ;
    USE SIGNAL ;
    PORT
      LAYER M3 ;
        RECT 16.629 0.000 16.653 0.192 ;
    END
  END b_d[224]
  PIN b_d[225]
    DIRECTION INPUT ;
    USE SIGNAL ;
    PORT
      LAYER M5 ;
        RECT 16.656 0.000 16.680 0.192 ;
    END
  END b_d[225]
  PIN b_d[226]
    DIRECTION INPUT ;
    USE SIGNAL ;
    PORT
      LAYER M3 ;
        RECT 16.737 0.000 16.761 0.192 ;
    END
  END b_d[226]
  PIN b_d[227]
    DIRECTION INPUT ;
    USE SIGNAL ;
    PORT
      LAYER M5 ;
        RECT 16.800 0.000 16.824 0.192 ;
    END
  END b_d[227]
  PIN b_d[228]
    DIRECTION INPUT ;
    USE SIGNAL ;
    PORT
      LAYER M3 ;
        RECT 16.845 0.000 16.869 0.192 ;
    END
  END b_d[228]
  PIN b_d[229]
    DIRECTION INPUT ;
    USE SIGNAL ;
    PORT
      LAYER M5 ;
        RECT 16.896 0.000 16.920 0.192 ;
    END
  END b_d[229]
  PIN b_d[230]
    DIRECTION INPUT ;
    USE SIGNAL ;
    PORT
      LAYER M3 ;
        RECT 16.989 0.000 17.013 0.192 ;
    END
  END b_d[230]
  PIN b_d[231]
    DIRECTION INPUT ;
    USE SIGNAL ;
    PORT
      LAYER M5 ;
        RECT 17.040 0.000 17.064 0.192 ;
    END
  END b_d[231]
  PIN b_d[232]
    DIRECTION INPUT ;
    USE SIGNAL ;
    PORT
      LAYER M3 ;
        RECT 17.097 0.000 17.121 0.192 ;
    END
  END b_d[232]
  PIN b_d[233]
    DIRECTION INPUT ;
    USE SIGNAL ;
    PORT
      LAYER M5 ;
        RECT 17.136 0.000 17.160 0.192 ;
    END
  END b_d[233]
  PIN b_d[234]
    DIRECTION INPUT ;
    USE SIGNAL ;
    PORT
      LAYER M3 ;
        RECT 17.205 0.000 17.229 0.192 ;
    END
  END b_d[234]
  PIN b_d[235]
    DIRECTION INPUT ;
    USE SIGNAL ;
    PORT
      LAYER M5 ;
        RECT 17.280 0.000 17.304 0.192 ;
    END
  END b_d[235]
  PIN b_d[236]
    DIRECTION INPUT ;
    USE SIGNAL ;
    PORT
      LAYER M3 ;
        RECT 17.349 0.000 17.373 0.192 ;
    END
  END b_d[236]
  PIN b_d[237]
    DIRECTION INPUT ;
    USE SIGNAL ;
    PORT
      LAYER M5 ;
        RECT 17.376 0.000 17.400 0.192 ;
    END
  END b_d[237]
  PIN b_d[238]
    DIRECTION INPUT ;
    USE SIGNAL ;
    PORT
      LAYER M3 ;
        RECT 17.457 0.000 17.481 0.192 ;
    END
  END b_d[238]
  PIN b_d[239]
    DIRECTION INPUT ;
    USE SIGNAL ;
    PORT
      LAYER M5 ;
        RECT 17.520 0.000 17.544 0.192 ;
    END
  END b_d[239]
  PIN b_d[240]
    DIRECTION INPUT ;
    USE SIGNAL ;
    PORT
      LAYER M3 ;
        RECT 17.565 0.000 17.589 0.192 ;
    END
  END b_d[240]
  PIN b_d[241]
    DIRECTION INPUT ;
    USE SIGNAL ;
    PORT
      LAYER M5 ;
        RECT 17.616 0.000 17.640 0.192 ;
    END
  END b_d[241]
  PIN b_d[242]
    DIRECTION INPUT ;
    USE SIGNAL ;
    PORT
      LAYER M3 ;
        RECT 17.709 0.000 17.733 0.192 ;
    END
  END b_d[242]
  PIN b_d[243]
    DIRECTION INPUT ;
    USE SIGNAL ;
    PORT
      LAYER M5 ;
        RECT 17.760 0.000 17.784 0.192 ;
    END
  END b_d[243]
  PIN b_d[244]
    DIRECTION INPUT ;
    USE SIGNAL ;
    PORT
      LAYER M3 ;
        RECT 17.817 0.000 17.841 0.192 ;
    END
  END b_d[244]
  PIN b_d[245]
    DIRECTION INPUT ;
    USE SIGNAL ;
    PORT
      LAYER M5 ;
        RECT 17.856 0.000 17.880 0.192 ;
    END
  END b_d[245]
  PIN b_d[246]
    DIRECTION INPUT ;
    USE SIGNAL ;
    PORT
      LAYER M3 ;
        RECT 17.925 0.000 17.949 0.192 ;
    END
  END b_d[246]
  PIN b_d[247]
    DIRECTION INPUT ;
    USE SIGNAL ;
    PORT
      LAYER M5 ;
        RECT 18.000 0.000 18.024 0.192 ;
    END
  END b_d[247]
  PIN b_d[248]
    DIRECTION INPUT ;
    USE SIGNAL ;
    PORT
      LAYER M3 ;
        RECT 18.069 0.000 18.093 0.192 ;
    END
  END b_d[248]
  PIN b_d[249]
    DIRECTION INPUT ;
    USE SIGNAL ;
    PORT
      LAYER M5 ;
        RECT 18.096 0.000 18.120 0.192 ;
    END
  END b_d[249]
  PIN b_d[250]
    DIRECTION INPUT ;
    USE SIGNAL ;
    PORT
      LAYER M3 ;
        RECT 18.177 0.000 18.201 0.192 ;
    END
  END b_d[250]
  PIN b_d[251]
    DIRECTION INPUT ;
    USE SIGNAL ;
    PORT
      LAYER M5 ;
        RECT 18.240 0.000 18.264 0.192 ;
    END
  END b_d[251]
  PIN b_d[252]
    DIRECTION INPUT ;
    USE SIGNAL ;
    PORT
      LAYER M3 ;
        RECT 18.285 0.000 18.309 0.192 ;
    END
  END b_d[252]
  PIN b_d[253]
    DIRECTION INPUT ;
    USE SIGNAL ;
    PORT
      LAYER M5 ;
        RECT 18.336 0.000 18.360 0.192 ;
    END
  END b_d[253]
  PIN b_d[254]
    DIRECTION INPUT ;
    USE SIGNAL ;
    PORT
      LAYER M3 ;
        RECT 18.393 0.000 18.417 0.192 ;
    END
  END b_d[254]
  PIN b_d[255]
    DIRECTION INPUT ;
    USE SIGNAL ;
    PORT
      LAYER M5 ;
        RECT 18.480 0.000 18.504 0.192 ;
    END
  END b_d[255]
  PIN b_d[256]
    DIRECTION INPUT ;
    USE SIGNAL ;
    PORT
      LAYER M3 ;
        RECT 18.537 0.000 18.561 0.192 ;
    END
  END b_d[256]
  PIN b_d[257]
    DIRECTION INPUT ;
    USE SIGNAL ;
    PORT
      LAYER M5 ;
        RECT 18.576 0.000 18.600 0.192 ;
    END
  END b_d[257]
  PIN b_d[258]
    DIRECTION INPUT ;
    USE SIGNAL ;
    PORT
      LAYER M3 ;
        RECT 18.645 0.000 18.669 0.192 ;
    END
  END b_d[258]
  PIN b_d[259]
    DIRECTION INPUT ;
    USE SIGNAL ;
    PORT
      LAYER M5 ;
        RECT 18.720 0.000 18.744 0.192 ;
    END
  END b_d[259]
  PIN b_d[260]
    DIRECTION INPUT ;
    USE SIGNAL ;
    PORT
      LAYER M3 ;
        RECT 18.753 0.000 18.777 0.192 ;
    END
  END b_d[260]
  PIN b_d[261]
    DIRECTION INPUT ;
    USE SIGNAL ;
    PORT
      LAYER M5 ;
        RECT 18.816 0.000 18.840 0.192 ;
    END
  END b_d[261]
  PIN b_d[262]
    DIRECTION INPUT ;
    USE SIGNAL ;
    PORT
      LAYER M3 ;
        RECT 18.897 0.000 18.921 0.192 ;
    END
  END b_d[262]
  PIN b_d[263]
    DIRECTION INPUT ;
    USE SIGNAL ;
    PORT
      LAYER M5 ;
        RECT 18.960 0.000 18.984 0.192 ;
    END
  END b_d[263]
  PIN b_d[264]
    DIRECTION INPUT ;
    USE SIGNAL ;
    PORT
      LAYER M3 ;
        RECT 19.005 0.000 19.029 0.192 ;
    END
  END b_d[264]
  PIN b_d[265]
    DIRECTION INPUT ;
    USE SIGNAL ;
    PORT
      LAYER M5 ;
        RECT 19.056 0.000 19.080 0.192 ;
    END
  END b_d[265]
  PIN b_d[266]
    DIRECTION INPUT ;
    USE SIGNAL ;
    PORT
      LAYER M3 ;
        RECT 19.113 0.000 19.137 0.192 ;
    END
  END b_d[266]
  PIN b_d[267]
    DIRECTION INPUT ;
    USE SIGNAL ;
    PORT
      LAYER M5 ;
        RECT 19.200 0.000 19.224 0.192 ;
    END
  END b_d[267]
  PIN b_d[268]
    DIRECTION INPUT ;
    USE SIGNAL ;
    PORT
      LAYER M3 ;
        RECT 19.257 0.000 19.281 0.192 ;
    END
  END b_d[268]
  PIN b_d[269]
    DIRECTION INPUT ;
    USE SIGNAL ;
    PORT
      LAYER M5 ;
        RECT 19.296 0.000 19.320 0.192 ;
    END
  END b_d[269]
  PIN b_d[270]
    DIRECTION INPUT ;
    USE SIGNAL ;
    PORT
      LAYER M3 ;
        RECT 19.365 0.000 19.389 0.192 ;
    END
  END b_d[270]
  PIN b_d[271]
    DIRECTION INPUT ;
    USE SIGNAL ;
    PORT
      LAYER M5 ;
        RECT 19.440 0.000 19.464 0.192 ;
    END
  END b_d[271]
  PIN b_d[272]
    DIRECTION INPUT ;
    USE SIGNAL ;
    PORT
      LAYER M3 ;
        RECT 19.473 0.000 19.497 0.192 ;
    END
  END b_d[272]
  PIN b_d[273]
    DIRECTION INPUT ;
    USE SIGNAL ;
    PORT
      LAYER M5 ;
        RECT 19.536 0.000 19.560 0.192 ;
    END
  END b_d[273]
  PIN b_d[274]
    DIRECTION INPUT ;
    USE SIGNAL ;
    PORT
      LAYER M3 ;
        RECT 19.617 0.000 19.641 0.192 ;
    END
  END b_d[274]
  PIN b_d[275]
    DIRECTION INPUT ;
    USE SIGNAL ;
    PORT
      LAYER M5 ;
        RECT 19.680 0.000 19.704 0.192 ;
    END
  END b_d[275]
  PIN b_d[276]
    DIRECTION INPUT ;
    USE SIGNAL ;
    PORT
      LAYER M3 ;
        RECT 19.725 0.000 19.749 0.192 ;
    END
  END b_d[276]
  PIN b_d[277]
    DIRECTION INPUT ;
    USE SIGNAL ;
    PORT
      LAYER M5 ;
        RECT 19.776 0.000 19.800 0.192 ;
    END
  END b_d[277]
  PIN b_d[278]
    DIRECTION INPUT ;
    USE SIGNAL ;
    PORT
      LAYER M3 ;
        RECT 19.833 0.000 19.857 0.192 ;
    END
  END b_d[278]
  PIN b_d[279]
    DIRECTION INPUT ;
    USE SIGNAL ;
    PORT
      LAYER M5 ;
        RECT 19.920 0.000 19.944 0.192 ;
    END
  END b_d[279]
  PIN b_d[280]
    DIRECTION INPUT ;
    USE SIGNAL ;
    PORT
      LAYER M3 ;
        RECT 19.977 0.000 20.001 0.192 ;
    END
  END b_d[280]
  PIN b_d[281]
    DIRECTION INPUT ;
    USE SIGNAL ;
    PORT
      LAYER M5 ;
        RECT 20.016 0.000 20.040 0.192 ;
    END
  END b_d[281]
  PIN b_d[282]
    DIRECTION INPUT ;
    USE SIGNAL ;
    PORT
      LAYER M3 ;
        RECT 20.085 0.000 20.109 0.192 ;
    END
  END b_d[282]
  PIN b_d[283]
    DIRECTION INPUT ;
    USE SIGNAL ;
    PORT
      LAYER M5 ;
        RECT 20.160 0.000 20.184 0.192 ;
    END
  END b_d[283]
  PIN b_d[284]
    DIRECTION INPUT ;
    USE SIGNAL ;
    PORT
      LAYER M3 ;
        RECT 20.193 0.000 20.217 0.192 ;
    END
  END b_d[284]
  PIN b_d[285]
    DIRECTION INPUT ;
    USE SIGNAL ;
    PORT
      LAYER M5 ;
        RECT 20.256 0.000 20.280 0.192 ;
    END
  END b_d[285]
  PIN b_d[286]
    DIRECTION INPUT ;
    USE SIGNAL ;
    PORT
      LAYER M3 ;
        RECT 20.301 0.000 20.325 0.192 ;
    END
  END b_d[286]
  PIN b_d[287]
    DIRECTION INPUT ;
    USE SIGNAL ;
    PORT
      LAYER M5 ;
        RECT 20.400 0.000 20.424 0.192 ;
    END
  END b_d[287]
  PIN b_d[288]
    DIRECTION INPUT ;
    USE SIGNAL ;
    PORT
      LAYER M3 ;
        RECT 20.445 0.000 20.469 0.192 ;
    END
  END b_d[288]
  PIN b_d[289]
    DIRECTION INPUT ;
    USE SIGNAL ;
    PORT
      LAYER M5 ;
        RECT 20.496 0.000 20.520 0.192 ;
    END
  END b_d[289]
  PIN b_d[290]
    DIRECTION INPUT ;
    USE SIGNAL ;
    PORT
      LAYER M3 ;
        RECT 20.553 0.000 20.577 0.192 ;
    END
  END b_d[290]
  PIN b_d[291]
    DIRECTION INPUT ;
    USE SIGNAL ;
    PORT
      LAYER M5 ;
        RECT 20.640 0.000 20.664 0.192 ;
    END
  END b_d[291]
  PIN b_d[292]
    DIRECTION INPUT ;
    USE SIGNAL ;
    PORT
      LAYER M3 ;
        RECT 20.661 0.000 20.685 0.192 ;
    END
  END b_d[292]
  PIN b_d[293]
    DIRECTION INPUT ;
    USE SIGNAL ;
    PORT
      LAYER M5 ;
        RECT 20.736 0.000 20.760 0.192 ;
    END
  END b_d[293]
  PIN b_d[294]
    DIRECTION INPUT ;
    USE SIGNAL ;
    PORT
      LAYER M3 ;
        RECT 20.805 0.000 20.829 0.192 ;
    END
  END b_d[294]
  PIN b_d[295]
    DIRECTION INPUT ;
    USE SIGNAL ;
    PORT
      LAYER M5 ;
        RECT 20.832 0.000 20.856 0.192 ;
    END
  END b_d[295]
  PIN b_d[296]
    DIRECTION INPUT ;
    USE SIGNAL ;
    PORT
      LAYER M3 ;
        RECT 20.913 0.000 20.937 0.192 ;
    END
  END b_d[296]
  PIN b_d[297]
    DIRECTION INPUT ;
    USE SIGNAL ;
    PORT
      LAYER M5 ;
        RECT 20.976 0.000 21.000 0.192 ;
    END
  END b_d[297]
  PIN b_d[298]
    DIRECTION INPUT ;
    USE SIGNAL ;
    PORT
      LAYER M3 ;
        RECT 21.021 0.000 21.045 0.192 ;
    END
  END b_d[298]
  PIN b_d[299]
    DIRECTION INPUT ;
    USE SIGNAL ;
    PORT
      LAYER M5 ;
        RECT 21.072 0.000 21.096 0.192 ;
    END
  END b_d[299]
  PIN b_d[300]
    DIRECTION INPUT ;
    USE SIGNAL ;
    PORT
      LAYER M3 ;
        RECT 21.165 0.000 21.189 0.192 ;
    END
  END b_d[300]
  PIN b_d[301]
    DIRECTION INPUT ;
    USE SIGNAL ;
    PORT
      LAYER M5 ;
        RECT 21.216 0.000 21.240 0.192 ;
    END
  END b_d[301]
  PIN b_d[302]
    DIRECTION INPUT ;
    USE SIGNAL ;
    PORT
      LAYER M3 ;
        RECT 21.273 0.000 21.297 0.192 ;
    END
  END b_d[302]
  PIN b_d[303]
    DIRECTION INPUT ;
    USE SIGNAL ;
    PORT
      LAYER M5 ;
        RECT 21.312 0.000 21.336 0.192 ;
    END
  END b_d[303]
  PIN b_d[304]
    DIRECTION INPUT ;
    USE SIGNAL ;
    PORT
      LAYER M3 ;
        RECT 21.381 0.000 21.405 0.192 ;
    END
  END b_d[304]
  PIN b_d[305]
    DIRECTION INPUT ;
    USE SIGNAL ;
    PORT
      LAYER M5 ;
        RECT 21.456 0.000 21.480 0.192 ;
    END
  END b_d[305]
  PIN b_d[306]
    DIRECTION INPUT ;
    USE SIGNAL ;
    PORT
      LAYER M3 ;
        RECT 21.525 0.000 21.549 0.192 ;
    END
  END b_d[306]
  PIN b_d[307]
    DIRECTION INPUT ;
    USE SIGNAL ;
    PORT
      LAYER M5 ;
        RECT 21.552 0.000 21.576 0.192 ;
    END
  END b_d[307]
  PIN b_d[308]
    DIRECTION INPUT ;
    USE SIGNAL ;
    PORT
      LAYER M3 ;
        RECT 21.633 0.000 21.657 0.192 ;
    END
  END b_d[308]
  PIN b_d[309]
    DIRECTION INPUT ;
    USE SIGNAL ;
    PORT
      LAYER M5 ;
        RECT 21.696 0.000 21.720 0.192 ;
    END
  END b_d[309]
  PIN b_d[310]
    DIRECTION INPUT ;
    USE SIGNAL ;
    PORT
      LAYER M3 ;
        RECT 21.741 0.000 21.765 0.192 ;
    END
  END b_d[310]
  PIN b_d[311]
    DIRECTION INPUT ;
    USE SIGNAL ;
    PORT
      LAYER M5 ;
        RECT 21.792 0.000 21.816 0.192 ;
    END
  END b_d[311]
  PIN b_d[312]
    DIRECTION INPUT ;
    USE SIGNAL ;
    PORT
      LAYER M3 ;
        RECT 21.885 0.000 21.909 0.192 ;
    END
  END b_d[312]
  PIN b_d[313]
    DIRECTION INPUT ;
    USE SIGNAL ;
    PORT
      LAYER M5 ;
        RECT 21.936 0.000 21.960 0.192 ;
    END
  END b_d[313]
  PIN b_d[314]
    DIRECTION INPUT ;
    USE SIGNAL ;
    PORT
      LAYER M3 ;
        RECT 21.993 0.000 22.017 0.192 ;
    END
  END b_d[314]
  PIN b_d[315]
    DIRECTION INPUT ;
    USE SIGNAL ;
    PORT
      LAYER M5 ;
        RECT 22.032 0.000 22.056 0.192 ;
    END
  END b_d[315]
  PIN b_d[316]
    DIRECTION INPUT ;
    USE SIGNAL ;
    PORT
      LAYER M3 ;
        RECT 22.101 0.000 22.125 0.192 ;
    END
  END b_d[316]
  PIN b_d[317]
    DIRECTION INPUT ;
    USE SIGNAL ;
    PORT
      LAYER M5 ;
        RECT 22.176 0.000 22.200 0.192 ;
    END
  END b_d[317]
  PIN b_d[318]
    DIRECTION INPUT ;
    USE SIGNAL ;
    PORT
      LAYER M3 ;
        RECT 22.209 0.000 22.233 0.192 ;
    END
  END b_d[318]
  PIN b_d[319]
    DIRECTION INPUT ;
    USE SIGNAL ;
    PORT
      LAYER M5 ;
        RECT 22.272 0.000 22.296 0.192 ;
    END
  END b_d[319]
  PIN b_d[320]
    DIRECTION INPUT ;
    USE SIGNAL ;
    PORT
      LAYER M3 ;
        RECT 22.353 0.000 22.377 0.192 ;
    END
  END b_d[320]
  PIN b_d[321]
    DIRECTION INPUT ;
    USE SIGNAL ;
    PORT
      LAYER M5 ;
        RECT 22.416 0.000 22.440 0.192 ;
    END
  END b_d[321]
  PIN b_d[322]
    DIRECTION INPUT ;
    USE SIGNAL ;
    PORT
      LAYER M3 ;
        RECT 22.461 0.000 22.485 0.192 ;
    END
  END b_d[322]
  PIN b_d[323]
    DIRECTION INPUT ;
    USE SIGNAL ;
    PORT
      LAYER M5 ;
        RECT 22.512 0.000 22.536 0.192 ;
    END
  END b_d[323]
  PIN b_d[324]
    DIRECTION INPUT ;
    USE SIGNAL ;
    PORT
      LAYER M3 ;
        RECT 22.569 0.000 22.593 0.192 ;
    END
  END b_d[324]
  PIN b_d[325]
    DIRECTION INPUT ;
    USE SIGNAL ;
    PORT
      LAYER M5 ;
        RECT 22.656 0.000 22.680 0.192 ;
    END
  END b_d[325]
  PIN b_d[326]
    DIRECTION INPUT ;
    USE SIGNAL ;
    PORT
      LAYER M3 ;
        RECT 22.713 0.000 22.737 0.192 ;
    END
  END b_d[326]
  PIN b_d[327]
    DIRECTION INPUT ;
    USE SIGNAL ;
    PORT
      LAYER M5 ;
        RECT 22.752 0.000 22.776 0.192 ;
    END
  END b_d[327]
  PIN b_d[328]
    DIRECTION INPUT ;
    USE SIGNAL ;
    PORT
      LAYER M3 ;
        RECT 22.821 0.000 22.845 0.192 ;
    END
  END b_d[328]
  PIN b_d[329]
    DIRECTION INPUT ;
    USE SIGNAL ;
    PORT
      LAYER M5 ;
        RECT 22.896 0.000 22.920 0.192 ;
    END
  END b_d[329]
  PIN b_d[330]
    DIRECTION INPUT ;
    USE SIGNAL ;
    PORT
      LAYER M3 ;
        RECT 22.929 0.000 22.953 0.192 ;
    END
  END b_d[330]
  PIN b_d[331]
    DIRECTION INPUT ;
    USE SIGNAL ;
    PORT
      LAYER M5 ;
        RECT 22.992 0.000 23.016 0.192 ;
    END
  END b_d[331]
  PIN b_d[332]
    DIRECTION INPUT ;
    USE SIGNAL ;
    PORT
      LAYER M3 ;
        RECT 23.073 0.000 23.097 0.192 ;
    END
  END b_d[332]
  PIN b_d[333]
    DIRECTION INPUT ;
    USE SIGNAL ;
    PORT
      LAYER M5 ;
        RECT 23.136 0.000 23.160 0.192 ;
    END
  END b_d[333]
  PIN b_d[334]
    DIRECTION INPUT ;
    USE SIGNAL ;
    PORT
      LAYER M3 ;
        RECT 23.181 0.000 23.205 0.192 ;
    END
  END b_d[334]
  PIN b_d[335]
    DIRECTION INPUT ;
    USE SIGNAL ;
    PORT
      LAYER M5 ;
        RECT 23.232 0.000 23.256 0.192 ;
    END
  END b_d[335]
  PIN b_d[336]
    DIRECTION INPUT ;
    USE SIGNAL ;
    PORT
      LAYER M3 ;
        RECT 23.289 0.000 23.313 0.192 ;
    END
  END b_d[336]
  PIN b_d[337]
    DIRECTION INPUT ;
    USE SIGNAL ;
    PORT
      LAYER M5 ;
        RECT 23.376 0.000 23.400 0.192 ;
    END
  END b_d[337]
  PIN b_d[338]
    DIRECTION INPUT ;
    USE SIGNAL ;
    PORT
      LAYER M3 ;
        RECT 23.433 0.000 23.457 0.192 ;
    END
  END b_d[338]
  PIN b_d[339]
    DIRECTION INPUT ;
    USE SIGNAL ;
    PORT
      LAYER M5 ;
        RECT 23.472 0.000 23.496 0.192 ;
    END
  END b_d[339]
  PIN b_d[340]
    DIRECTION INPUT ;
    USE SIGNAL ;
    PORT
      LAYER M3 ;
        RECT 23.541 0.000 23.565 0.192 ;
    END
  END b_d[340]
  PIN b_d[341]
    DIRECTION INPUT ;
    USE SIGNAL ;
    PORT
      LAYER M5 ;
        RECT 23.616 0.000 23.640 0.192 ;
    END
  END b_d[341]
  PIN b_d[342]
    DIRECTION INPUT ;
    USE SIGNAL ;
    PORT
      LAYER M3 ;
        RECT 23.649 0.000 23.673 0.192 ;
    END
  END b_d[342]
  PIN b_d[343]
    DIRECTION INPUT ;
    USE SIGNAL ;
    PORT
      LAYER M5 ;
        RECT 23.712 0.000 23.736 0.192 ;
    END
  END b_d[343]
  PIN b_d[344]
    DIRECTION INPUT ;
    USE SIGNAL ;
    PORT
      LAYER M3 ;
        RECT 23.793 0.000 23.817 0.192 ;
    END
  END b_d[344]
  PIN b_d[345]
    DIRECTION INPUT ;
    USE SIGNAL ;
    PORT
      LAYER M5 ;
        RECT 23.856 0.000 23.880 0.192 ;
    END
  END b_d[345]
  PIN b_d[346]
    DIRECTION INPUT ;
    USE SIGNAL ;
    PORT
      LAYER M3 ;
        RECT 23.901 0.000 23.925 0.192 ;
    END
  END b_d[346]
  PIN b_d[347]
    DIRECTION INPUT ;
    USE SIGNAL ;
    PORT
      LAYER M5 ;
        RECT 23.952 0.000 23.976 0.192 ;
    END
  END b_d[347]
  PIN b_d[348]
    DIRECTION INPUT ;
    USE SIGNAL ;
    PORT
      LAYER M3 ;
        RECT 24.009 0.000 24.033 0.192 ;
    END
  END b_d[348]
  PIN b_d[349]
    DIRECTION INPUT ;
    USE SIGNAL ;
    PORT
      LAYER M5 ;
        RECT 24.096 0.000 24.120 0.192 ;
    END
  END b_d[349]
  PIN b_d[350]
    DIRECTION INPUT ;
    USE SIGNAL ;
    PORT
      LAYER M3 ;
        RECT 24.153 0.000 24.177 0.192 ;
    END
  END b_d[350]
  PIN b_d[351]
    DIRECTION INPUT ;
    USE SIGNAL ;
    PORT
      LAYER M5 ;
        RECT 24.192 0.000 24.216 0.192 ;
    END
  END b_d[351]
  PIN b_d[352]
    DIRECTION INPUT ;
    USE SIGNAL ;
    PORT
      LAYER M3 ;
        RECT 24.261 0.000 24.285 0.192 ;
    END
  END b_d[352]
  PIN b_d[353]
    DIRECTION INPUT ;
    USE SIGNAL ;
    PORT
      LAYER M5 ;
        RECT 24.336 0.000 24.360 0.192 ;
    END
  END b_d[353]
  PIN b_d[354]
    DIRECTION INPUT ;
    USE SIGNAL ;
    PORT
      LAYER M3 ;
        RECT 24.369 0.000 24.393 0.192 ;
    END
  END b_d[354]
  PIN b_d[355]
    DIRECTION INPUT ;
    USE SIGNAL ;
    PORT
      LAYER M5 ;
        RECT 24.432 0.000 24.456 0.192 ;
    END
  END b_d[355]
  PIN b_d[356]
    DIRECTION INPUT ;
    USE SIGNAL ;
    PORT
      LAYER M3 ;
        RECT 24.477 0.000 24.501 0.192 ;
    END
  END b_d[356]
  PIN b_d[357]
    DIRECTION INPUT ;
    USE SIGNAL ;
    PORT
      LAYER M5 ;
        RECT 24.576 0.000 24.600 0.192 ;
    END
  END b_d[357]
  PIN b_d[358]
    DIRECTION INPUT ;
    USE SIGNAL ;
    PORT
      LAYER M3 ;
        RECT 24.621 0.000 24.645 0.192 ;
    END
  END b_d[358]
  PIN b_d[359]
    DIRECTION INPUT ;
    USE SIGNAL ;
    PORT
      LAYER M5 ;
        RECT 24.672 0.000 24.696 0.192 ;
    END
  END b_d[359]
  PIN b_d[360]
    DIRECTION INPUT ;
    USE SIGNAL ;
    PORT
      LAYER M3 ;
        RECT 24.729 0.000 24.753 0.192 ;
    END
  END b_d[360]
  PIN b_d[361]
    DIRECTION INPUT ;
    USE SIGNAL ;
    PORT
      LAYER M5 ;
        RECT 24.768 0.000 24.792 0.192 ;
    END
  END b_d[361]
  PIN b_d[362]
    DIRECTION INPUT ;
    USE SIGNAL ;
    PORT
      LAYER M3 ;
        RECT 24.837 0.000 24.861 0.192 ;
    END
  END b_d[362]
  PIN b_d[363]
    DIRECTION INPUT ;
    USE SIGNAL ;
    PORT
      LAYER M5 ;
        RECT 24.912 0.000 24.936 0.192 ;
    END
  END b_d[363]
  PIN b_d[364]
    DIRECTION INPUT ;
    USE SIGNAL ;
    PORT
      LAYER M3 ;
        RECT 24.981 0.000 25.005 0.192 ;
    END
  END b_d[364]
  PIN b_d[365]
    DIRECTION INPUT ;
    USE SIGNAL ;
    PORT
      LAYER M5 ;
        RECT 25.008 0.000 25.032 0.192 ;
    END
  END b_d[365]
  PIN b_d[366]
    DIRECTION INPUT ;
    USE SIGNAL ;
    PORT
      LAYER M3 ;
        RECT 25.089 0.000 25.113 0.192 ;
    END
  END b_d[366]
  PIN b_d[367]
    DIRECTION INPUT ;
    USE SIGNAL ;
    PORT
      LAYER M5 ;
        RECT 25.152 0.000 25.176 0.192 ;
    END
  END b_d[367]
  PIN b_d[368]
    DIRECTION INPUT ;
    USE SIGNAL ;
    PORT
      LAYER M3 ;
        RECT 25.197 0.000 25.221 0.192 ;
    END
  END b_d[368]
  PIN b_d[369]
    DIRECTION INPUT ;
    USE SIGNAL ;
    PORT
      LAYER M5 ;
        RECT 25.248 0.000 25.272 0.192 ;
    END
  END b_d[369]
  PIN b_d[370]
    DIRECTION INPUT ;
    USE SIGNAL ;
    PORT
      LAYER M3 ;
        RECT 25.341 0.000 25.365 0.192 ;
    END
  END b_d[370]
  PIN b_d[371]
    DIRECTION INPUT ;
    USE SIGNAL ;
    PORT
      LAYER M5 ;
        RECT 25.392 0.000 25.416 0.192 ;
    END
  END b_d[371]
  PIN b_d[372]
    DIRECTION INPUT ;
    USE SIGNAL ;
    PORT
      LAYER M3 ;
        RECT 25.449 0.000 25.473 0.192 ;
    END
  END b_d[372]
  PIN b_d[373]
    DIRECTION INPUT ;
    USE SIGNAL ;
    PORT
      LAYER M5 ;
        RECT 25.488 0.000 25.512 0.192 ;
    END
  END b_d[373]
  PIN b_d[374]
    DIRECTION INPUT ;
    USE SIGNAL ;
    PORT
      LAYER M3 ;
        RECT 25.557 0.000 25.581 0.192 ;
    END
  END b_d[374]
  PIN b_d[375]
    DIRECTION INPUT ;
    USE SIGNAL ;
    PORT
      LAYER M5 ;
        RECT 25.632 0.000 25.656 0.192 ;
    END
  END b_d[375]
  PIN b_d[376]
    DIRECTION INPUT ;
    USE SIGNAL ;
    PORT
      LAYER M3 ;
        RECT 25.701 0.000 25.725 0.192 ;
    END
  END b_d[376]
  PIN b_d[377]
    DIRECTION INPUT ;
    USE SIGNAL ;
    PORT
      LAYER M5 ;
        RECT 25.728 0.000 25.752 0.192 ;
    END
  END b_d[377]
  PIN b_d[378]
    DIRECTION INPUT ;
    USE SIGNAL ;
    PORT
      LAYER M3 ;
        RECT 25.809 0.000 25.833 0.192 ;
    END
  END b_d[378]
  PIN b_d[379]
    DIRECTION INPUT ;
    USE SIGNAL ;
    PORT
      LAYER M5 ;
        RECT 25.872 0.000 25.896 0.192 ;
    END
  END b_d[379]
  PIN b_d[380]
    DIRECTION INPUT ;
    USE SIGNAL ;
    PORT
      LAYER M3 ;
        RECT 25.917 0.000 25.941 0.192 ;
    END
  END b_d[380]
  PIN b_d[381]
    DIRECTION INPUT ;
    USE SIGNAL ;
    PORT
      LAYER M5 ;
        RECT 25.968 0.000 25.992 0.192 ;
    END
  END b_d[381]
  PIN b_d[382]
    DIRECTION INPUT ;
    USE SIGNAL ;
    PORT
      LAYER M3 ;
        RECT 26.061 0.000 26.085 0.192 ;
    END
  END b_d[382]
  PIN b_d[383]
    DIRECTION INPUT ;
    USE SIGNAL ;
    PORT
      LAYER M5 ;
        RECT 26.112 0.000 26.136 0.192 ;
    END
  END b_d[383]
  PIN b_d[384]
    DIRECTION INPUT ;
    USE SIGNAL ;
    PORT
      LAYER M3 ;
        RECT 26.169 0.000 26.193 0.192 ;
    END
  END b_d[384]
  PIN b_d[385]
    DIRECTION INPUT ;
    USE SIGNAL ;
    PORT
      LAYER M5 ;
        RECT 26.208 0.000 26.232 0.192 ;
    END
  END b_d[385]
  PIN b_d[386]
    DIRECTION INPUT ;
    USE SIGNAL ;
    PORT
      LAYER M3 ;
        RECT 26.277 0.000 26.301 0.192 ;
    END
  END b_d[386]
  PIN b_d[387]
    DIRECTION INPUT ;
    USE SIGNAL ;
    PORT
      LAYER M5 ;
        RECT 26.352 0.000 26.376 0.192 ;
    END
  END b_d[387]
  PIN b_d[388]
    DIRECTION INPUT ;
    USE SIGNAL ;
    PORT
      LAYER M3 ;
        RECT 26.385 0.000 26.409 0.192 ;
    END
  END b_d[388]
  PIN b_d[389]
    DIRECTION INPUT ;
    USE SIGNAL ;
    PORT
      LAYER M5 ;
        RECT 26.448 0.000 26.472 0.192 ;
    END
  END b_d[389]
  PIN b_d[390]
    DIRECTION INPUT ;
    USE SIGNAL ;
    PORT
      LAYER M3 ;
        RECT 26.529 0.000 26.553 0.192 ;
    END
  END b_d[390]
  PIN b_d[391]
    DIRECTION INPUT ;
    USE SIGNAL ;
    PORT
      LAYER M5 ;
        RECT 26.592 0.000 26.616 0.192 ;
    END
  END b_d[391]
  PIN b_d[392]
    DIRECTION INPUT ;
    USE SIGNAL ;
    PORT
      LAYER M3 ;
        RECT 26.637 0.000 26.661 0.192 ;
    END
  END b_d[392]
  PIN b_d[393]
    DIRECTION INPUT ;
    USE SIGNAL ;
    PORT
      LAYER M5 ;
        RECT 26.688 0.000 26.712 0.192 ;
    END
  END b_d[393]
  PIN b_d[394]
    DIRECTION INPUT ;
    USE SIGNAL ;
    PORT
      LAYER M3 ;
        RECT 26.745 0.000 26.769 0.192 ;
    END
  END b_d[394]
  PIN b_d[395]
    DIRECTION INPUT ;
    USE SIGNAL ;
    PORT
      LAYER M5 ;
        RECT 26.832 0.000 26.856 0.192 ;
    END
  END b_d[395]
  PIN b_d[396]
    DIRECTION INPUT ;
    USE SIGNAL ;
    PORT
      LAYER M3 ;
        RECT 26.889 0.000 26.913 0.192 ;
    END
  END b_d[396]
  PIN b_d[397]
    DIRECTION INPUT ;
    USE SIGNAL ;
    PORT
      LAYER M5 ;
        RECT 26.928 0.000 26.952 0.192 ;
    END
  END b_d[397]
  PIN b_d[398]
    DIRECTION INPUT ;
    USE SIGNAL ;
    PORT
      LAYER M3 ;
        RECT 26.997 0.000 27.021 0.192 ;
    END
  END b_d[398]
  PIN b_d[399]
    DIRECTION INPUT ;
    USE SIGNAL ;
    PORT
      LAYER M5 ;
        RECT 27.072 0.000 27.096 0.192 ;
    END
  END b_d[399]
  PIN b_d[400]
    DIRECTION INPUT ;
    USE SIGNAL ;
    PORT
      LAYER M3 ;
        RECT 27.105 0.000 27.129 0.192 ;
    END
  END b_d[400]
  PIN b_d[401]
    DIRECTION INPUT ;
    USE SIGNAL ;
    PORT
      LAYER M5 ;
        RECT 27.168 0.000 27.192 0.192 ;
    END
  END b_d[401]
  PIN b_d[402]
    DIRECTION INPUT ;
    USE SIGNAL ;
    PORT
      LAYER M3 ;
        RECT 27.249 0.000 27.273 0.192 ;
    END
  END b_d[402]
  PIN b_d[403]
    DIRECTION INPUT ;
    USE SIGNAL ;
    PORT
      LAYER M5 ;
        RECT 27.312 0.000 27.336 0.192 ;
    END
  END b_d[403]
  PIN b_d[404]
    DIRECTION INPUT ;
    USE SIGNAL ;
    PORT
      LAYER M3 ;
        RECT 27.357 0.000 27.381 0.192 ;
    END
  END b_d[404]
  PIN b_d[405]
    DIRECTION INPUT ;
    USE SIGNAL ;
    PORT
      LAYER M5 ;
        RECT 27.408 0.000 27.432 0.192 ;
    END
  END b_d[405]
  PIN b_d[406]
    DIRECTION INPUT ;
    USE SIGNAL ;
    PORT
      LAYER M3 ;
        RECT 27.465 0.000 27.489 0.192 ;
    END
  END b_d[406]
  PIN b_d[407]
    DIRECTION INPUT ;
    USE SIGNAL ;
    PORT
      LAYER M5 ;
        RECT 27.552 0.000 27.576 0.192 ;
    END
  END b_d[407]
  PIN b_d[408]
    DIRECTION INPUT ;
    USE SIGNAL ;
    PORT
      LAYER M3 ;
        RECT 27.609 0.000 27.633 0.192 ;
    END
  END b_d[408]
  PIN b_d[409]
    DIRECTION INPUT ;
    USE SIGNAL ;
    PORT
      LAYER M5 ;
        RECT 27.648 0.000 27.672 0.192 ;
    END
  END b_d[409]
  PIN b_d[410]
    DIRECTION INPUT ;
    USE SIGNAL ;
    PORT
      LAYER M3 ;
        RECT 27.717 0.000 27.741 0.192 ;
    END
  END b_d[410]
  PIN b_d[411]
    DIRECTION INPUT ;
    USE SIGNAL ;
    PORT
      LAYER M5 ;
        RECT 27.792 0.000 27.816 0.192 ;
    END
  END b_d[411]
  PIN b_d[412]
    DIRECTION INPUT ;
    USE SIGNAL ;
    PORT
      LAYER M3 ;
        RECT 27.825 0.000 27.849 0.192 ;
    END
  END b_d[412]
  PIN b_d[413]
    DIRECTION INPUT ;
    USE SIGNAL ;
    PORT
      LAYER M5 ;
        RECT 27.888 0.000 27.912 0.192 ;
    END
  END b_d[413]
  PIN b_d[414]
    DIRECTION INPUT ;
    USE SIGNAL ;
    PORT
      LAYER M3 ;
        RECT 27.969 0.000 27.993 0.192 ;
    END
  END b_d[414]
  PIN b_d[415]
    DIRECTION INPUT ;
    USE SIGNAL ;
    PORT
      LAYER M5 ;
        RECT 28.032 0.000 28.056 0.192 ;
    END
  END b_d[415]
  PIN b_d[416]
    DIRECTION INPUT ;
    USE SIGNAL ;
    PORT
      LAYER M3 ;
        RECT 28.077 0.000 28.101 0.192 ;
    END
  END b_d[416]
  PIN b_d[417]
    DIRECTION INPUT ;
    USE SIGNAL ;
    PORT
      LAYER M5 ;
        RECT 28.128 0.000 28.152 0.192 ;
    END
  END b_d[417]
  PIN b_d[418]
    DIRECTION INPUT ;
    USE SIGNAL ;
    PORT
      LAYER M3 ;
        RECT 28.185 0.000 28.209 0.192 ;
    END
  END b_d[418]
  PIN b_d[419]
    DIRECTION INPUT ;
    USE SIGNAL ;
    PORT
      LAYER M5 ;
        RECT 28.272 0.000 28.296 0.192 ;
    END
  END b_d[419]
  PIN b_d[420]
    DIRECTION INPUT ;
    USE SIGNAL ;
    PORT
      LAYER M3 ;
        RECT 28.329 0.000 28.353 0.192 ;
    END
  END b_d[420]
  PIN b_d[421]
    DIRECTION INPUT ;
    USE SIGNAL ;
    PORT
      LAYER M5 ;
        RECT 28.368 0.000 28.392 0.192 ;
    END
  END b_d[421]
  PIN b_d[422]
    DIRECTION INPUT ;
    USE SIGNAL ;
    PORT
      LAYER M3 ;
        RECT 28.437 0.000 28.461 0.192 ;
    END
  END b_d[422]
  PIN b_d[423]
    DIRECTION INPUT ;
    USE SIGNAL ;
    PORT
      LAYER M5 ;
        RECT 28.512 0.000 28.536 0.192 ;
    END
  END b_d[423]
  PIN b_d[424]
    DIRECTION INPUT ;
    USE SIGNAL ;
    PORT
      LAYER M3 ;
        RECT 28.545 0.000 28.569 0.192 ;
    END
  END b_d[424]
  PIN b_d[425]
    DIRECTION INPUT ;
    USE SIGNAL ;
    PORT
      LAYER M5 ;
        RECT 28.608 0.000 28.632 0.192 ;
    END
  END b_d[425]
  PIN b_d[426]
    DIRECTION INPUT ;
    USE SIGNAL ;
    PORT
      LAYER M3 ;
        RECT 28.653 0.000 28.677 0.192 ;
    END
  END b_d[426]
  PIN b_d[427]
    DIRECTION INPUT ;
    USE SIGNAL ;
    PORT
      LAYER M5 ;
        RECT 28.752 0.000 28.776 0.192 ;
    END
  END b_d[427]
  PIN b_d[428]
    DIRECTION INPUT ;
    USE SIGNAL ;
    PORT
      LAYER M3 ;
        RECT 28.797 0.000 28.821 0.192 ;
    END
  END b_d[428]
  PIN b_d[429]
    DIRECTION INPUT ;
    USE SIGNAL ;
    PORT
      LAYER M5 ;
        RECT 28.848 0.000 28.872 0.192 ;
    END
  END b_d[429]
  PIN b_d[430]
    DIRECTION INPUT ;
    USE SIGNAL ;
    PORT
      LAYER M3 ;
        RECT 28.905 0.000 28.929 0.192 ;
    END
  END b_d[430]
  PIN b_d[431]
    DIRECTION INPUT ;
    USE SIGNAL ;
    PORT
      LAYER M5 ;
        RECT 28.944 0.000 28.968 0.192 ;
    END
  END b_d[431]
  PIN b_d[432]
    DIRECTION INPUT ;
    USE SIGNAL ;
    PORT
      LAYER M3 ;
        RECT 29.013 0.000 29.037 0.192 ;
    END
  END b_d[432]
  PIN b_d[433]
    DIRECTION INPUT ;
    USE SIGNAL ;
    PORT
      LAYER M5 ;
        RECT 29.088 0.000 29.112 0.192 ;
    END
  END b_d[433]
  PIN b_d[434]
    DIRECTION INPUT ;
    USE SIGNAL ;
    PORT
      LAYER M3 ;
        RECT 29.157 0.000 29.181 0.192 ;
    END
  END b_d[434]
  PIN b_d[435]
    DIRECTION INPUT ;
    USE SIGNAL ;
    PORT
      LAYER M5 ;
        RECT 29.184 0.000 29.208 0.192 ;
    END
  END b_d[435]
  PIN b_d[436]
    DIRECTION INPUT ;
    USE SIGNAL ;
    PORT
      LAYER M3 ;
        RECT 29.265 0.000 29.289 0.192 ;
    END
  END b_d[436]
  PIN b_d[437]
    DIRECTION INPUT ;
    USE SIGNAL ;
    PORT
      LAYER M5 ;
        RECT 29.328 0.000 29.352 0.192 ;
    END
  END b_d[437]
  PIN b_d[438]
    DIRECTION INPUT ;
    USE SIGNAL ;
    PORT
      LAYER M3 ;
        RECT 29.373 0.000 29.397 0.192 ;
    END
  END b_d[438]
  PIN b_d[439]
    DIRECTION INPUT ;
    USE SIGNAL ;
    PORT
      LAYER M5 ;
        RECT 29.424 0.000 29.448 0.192 ;
    END
  END b_d[439]
  PIN b_d[440]
    DIRECTION INPUT ;
    USE SIGNAL ;
    PORT
      LAYER M3 ;
        RECT 29.517 0.000 29.541 0.192 ;
    END
  END b_d[440]
  PIN b_d[441]
    DIRECTION INPUT ;
    USE SIGNAL ;
    PORT
      LAYER M5 ;
        RECT 29.568 0.000 29.592 0.192 ;
    END
  END b_d[441]
  PIN b_d[442]
    DIRECTION INPUT ;
    USE SIGNAL ;
    PORT
      LAYER M3 ;
        RECT 29.625 0.000 29.649 0.192 ;
    END
  END b_d[442]
  PIN b_d[443]
    DIRECTION INPUT ;
    USE SIGNAL ;
    PORT
      LAYER M5 ;
        RECT 29.664 0.000 29.688 0.192 ;
    END
  END b_d[443]
  PIN b_d[444]
    DIRECTION INPUT ;
    USE SIGNAL ;
    PORT
      LAYER M3 ;
        RECT 29.733 0.000 29.757 0.192 ;
    END
  END b_d[444]
  PIN b_d[445]
    DIRECTION INPUT ;
    USE SIGNAL ;
    PORT
      LAYER M5 ;
        RECT 29.808 0.000 29.832 0.192 ;
    END
  END b_d[445]
  PIN b_d[446]
    DIRECTION INPUT ;
    USE SIGNAL ;
    PORT
      LAYER M3 ;
        RECT 29.877 0.000 29.901 0.192 ;
    END
  END b_d[446]
  PIN b_d[447]
    DIRECTION INPUT ;
    USE SIGNAL ;
    PORT
      LAYER M5 ;
        RECT 29.904 0.000 29.928 0.192 ;
    END
  END b_d[447]
  PIN b_d[448]
    DIRECTION INPUT ;
    USE SIGNAL ;
    PORT
      LAYER M3 ;
        RECT 29.985 0.000 30.009 0.192 ;
    END
  END b_d[448]
  PIN b_d[449]
    DIRECTION INPUT ;
    USE SIGNAL ;
    PORT
      LAYER M5 ;
        RECT 30.048 0.000 30.072 0.192 ;
    END
  END b_d[449]
  PIN b_d[450]
    DIRECTION INPUT ;
    USE SIGNAL ;
    PORT
      LAYER M3 ;
        RECT 30.093 0.000 30.117 0.192 ;
    END
  END b_d[450]
  PIN b_d[451]
    DIRECTION INPUT ;
    USE SIGNAL ;
    PORT
      LAYER M5 ;
        RECT 30.144 0.000 30.168 0.192 ;
    END
  END b_d[451]
  PIN b_d[452]
    DIRECTION INPUT ;
    USE SIGNAL ;
    PORT
      LAYER M3 ;
        RECT 30.237 0.000 30.261 0.192 ;
    END
  END b_d[452]
  PIN b_d[453]
    DIRECTION INPUT ;
    USE SIGNAL ;
    PORT
      LAYER M5 ;
        RECT 30.288 0.000 30.312 0.192 ;
    END
  END b_d[453]
  PIN b_d[454]
    DIRECTION INPUT ;
    USE SIGNAL ;
    PORT
      LAYER M3 ;
        RECT 30.345 0.000 30.369 0.192 ;
    END
  END b_d[454]
  PIN b_d[455]
    DIRECTION INPUT ;
    USE SIGNAL ;
    PORT
      LAYER M5 ;
        RECT 30.384 0.000 30.408 0.192 ;
    END
  END b_d[455]
  PIN b_d[456]
    DIRECTION INPUT ;
    USE SIGNAL ;
    PORT
      LAYER M3 ;
        RECT 30.453 0.000 30.477 0.192 ;
    END
  END b_d[456]
  PIN b_d[457]
    DIRECTION INPUT ;
    USE SIGNAL ;
    PORT
      LAYER M5 ;
        RECT 30.528 0.000 30.552 0.192 ;
    END
  END b_d[457]
  PIN b_d[458]
    DIRECTION INPUT ;
    USE SIGNAL ;
    PORT
      LAYER M3 ;
        RECT 30.561 0.000 30.585 0.192 ;
    END
  END b_d[458]
  PIN b_d[459]
    DIRECTION INPUT ;
    USE SIGNAL ;
    PORT
      LAYER M5 ;
        RECT 30.624 0.000 30.648 0.192 ;
    END
  END b_d[459]
  PIN b_d[460]
    DIRECTION INPUT ;
    USE SIGNAL ;
    PORT
      LAYER M3 ;
        RECT 30.705 0.000 30.729 0.192 ;
    END
  END b_d[460]
  PIN b_d[461]
    DIRECTION INPUT ;
    USE SIGNAL ;
    PORT
      LAYER M5 ;
        RECT 30.768 0.000 30.792 0.192 ;
    END
  END b_d[461]
  PIN b_d[462]
    DIRECTION INPUT ;
    USE SIGNAL ;
    PORT
      LAYER M3 ;
        RECT 30.813 0.000 30.837 0.192 ;
    END
  END b_d[462]
  PIN b_d[463]
    DIRECTION INPUT ;
    USE SIGNAL ;
    PORT
      LAYER M5 ;
        RECT 30.864 0.000 30.888 0.192 ;
    END
  END b_d[463]
  PIN b_d[464]
    DIRECTION INPUT ;
    USE SIGNAL ;
    PORT
      LAYER M3 ;
        RECT 30.921 0.000 30.945 0.192 ;
    END
  END b_d[464]
  PIN b_d[465]
    DIRECTION INPUT ;
    USE SIGNAL ;
    PORT
      LAYER M5 ;
        RECT 31.008 0.000 31.032 0.192 ;
    END
  END b_d[465]
  PIN b_d[466]
    DIRECTION INPUT ;
    USE SIGNAL ;
    PORT
      LAYER M3 ;
        RECT 31.065 0.000 31.089 0.192 ;
    END
  END b_d[466]
  PIN b_d[467]
    DIRECTION INPUT ;
    USE SIGNAL ;
    PORT
      LAYER M5 ;
        RECT 31.104 0.000 31.128 0.192 ;
    END
  END b_d[467]
  PIN b_d[468]
    DIRECTION INPUT ;
    USE SIGNAL ;
    PORT
      LAYER M3 ;
        RECT 31.173 0.000 31.197 0.192 ;
    END
  END b_d[468]
  PIN b_d[469]
    DIRECTION INPUT ;
    USE SIGNAL ;
    PORT
      LAYER M5 ;
        RECT 31.248 0.000 31.272 0.192 ;
    END
  END b_d[469]
  PIN b_d[470]
    DIRECTION INPUT ;
    USE SIGNAL ;
    PORT
      LAYER M3 ;
        RECT 31.281 0.000 31.305 0.192 ;
    END
  END b_d[470]
  PIN b_d[471]
    DIRECTION INPUT ;
    USE SIGNAL ;
    PORT
      LAYER M5 ;
        RECT 31.344 0.000 31.368 0.192 ;
    END
  END b_d[471]
  PIN b_d[472]
    DIRECTION INPUT ;
    USE SIGNAL ;
    PORT
      LAYER M3 ;
        RECT 31.425 0.000 31.449 0.192 ;
    END
  END b_d[472]
  PIN b_d[473]
    DIRECTION INPUT ;
    USE SIGNAL ;
    PORT
      LAYER M5 ;
        RECT 31.488 0.000 31.512 0.192 ;
    END
  END b_d[473]
  PIN b_d[474]
    DIRECTION INPUT ;
    USE SIGNAL ;
    PORT
      LAYER M3 ;
        RECT 31.533 0.000 31.557 0.192 ;
    END
  END b_d[474]
  PIN b_d[475]
    DIRECTION INPUT ;
    USE SIGNAL ;
    PORT
      LAYER M5 ;
        RECT 31.584 0.000 31.608 0.192 ;
    END
  END b_d[475]
  PIN b_d[476]
    DIRECTION INPUT ;
    USE SIGNAL ;
    PORT
      LAYER M3 ;
        RECT 31.641 0.000 31.665 0.192 ;
    END
  END b_d[476]
  PIN b_d[477]
    DIRECTION INPUT ;
    USE SIGNAL ;
    PORT
      LAYER M5 ;
        RECT 31.728 0.000 31.752 0.192 ;
    END
  END b_d[477]
  PIN b_d[478]
    DIRECTION INPUT ;
    USE SIGNAL ;
    PORT
      LAYER M3 ;
        RECT 31.785 0.000 31.809 0.192 ;
    END
  END b_d[478]
  PIN b_d[479]
    DIRECTION INPUT ;
    USE SIGNAL ;
    PORT
      LAYER M5 ;
        RECT 31.824 0.000 31.848 0.192 ;
    END
  END b_d[479]
  PIN b_d[480]
    DIRECTION INPUT ;
    USE SIGNAL ;
    PORT
      LAYER M3 ;
        RECT 31.893 0.000 31.917 0.192 ;
    END
  END b_d[480]
  PIN b_d[481]
    DIRECTION INPUT ;
    USE SIGNAL ;
    PORT
      LAYER M5 ;
        RECT 31.968 0.000 31.992 0.192 ;
    END
  END b_d[481]
  PIN b_d[482]
    DIRECTION INPUT ;
    USE SIGNAL ;
    PORT
      LAYER M3 ;
        RECT 32.001 0.000 32.025 0.192 ;
    END
  END b_d[482]
  PIN b_d[483]
    DIRECTION INPUT ;
    USE SIGNAL ;
    PORT
      LAYER M5 ;
        RECT 32.064 0.000 32.088 0.192 ;
    END
  END b_d[483]
  PIN b_d[484]
    DIRECTION INPUT ;
    USE SIGNAL ;
    PORT
      LAYER M3 ;
        RECT 32.145 0.000 32.169 0.192 ;
    END
  END b_d[484]
  PIN b_d[485]
    DIRECTION INPUT ;
    USE SIGNAL ;
    PORT
      LAYER M5 ;
        RECT 32.208 0.000 32.232 0.192 ;
    END
  END b_d[485]
  PIN b_d[486]
    DIRECTION INPUT ;
    USE SIGNAL ;
    PORT
      LAYER M3 ;
        RECT 32.253 0.000 32.277 0.192 ;
    END
  END b_d[486]
  PIN b_d[487]
    DIRECTION INPUT ;
    USE SIGNAL ;
    PORT
      LAYER M5 ;
        RECT 32.304 0.000 32.328 0.192 ;
    END
  END b_d[487]
  PIN b_d[488]
    DIRECTION INPUT ;
    USE SIGNAL ;
    PORT
      LAYER M3 ;
        RECT 32.361 0.000 32.385 0.192 ;
    END
  END b_d[488]
  PIN b_d[489]
    DIRECTION INPUT ;
    USE SIGNAL ;
    PORT
      LAYER M5 ;
        RECT 32.448 0.000 32.472 0.192 ;
    END
  END b_d[489]
  PIN b_d[490]
    DIRECTION INPUT ;
    USE SIGNAL ;
    PORT
      LAYER M3 ;
        RECT 32.469 0.000 32.493 0.192 ;
    END
  END b_d[490]
  PIN b_d[491]
    DIRECTION INPUT ;
    USE SIGNAL ;
    PORT
      LAYER M5 ;
        RECT 32.544 0.000 32.568 0.192 ;
    END
  END b_d[491]
  PIN b_d[492]
    DIRECTION INPUT ;
    USE SIGNAL ;
    PORT
      LAYER M3 ;
        RECT 32.613 0.000 32.637 0.192 ;
    END
  END b_d[492]
  PIN b_d[493]
    DIRECTION INPUT ;
    USE SIGNAL ;
    PORT
      LAYER M5 ;
        RECT 32.688 0.000 32.712 0.192 ;
    END
  END b_d[493]
  PIN b_d[494]
    DIRECTION INPUT ;
    USE SIGNAL ;
    PORT
      LAYER M3 ;
        RECT 32.721 0.000 32.745 0.192 ;
    END
  END b_d[494]
  PIN b_d[495]
    DIRECTION INPUT ;
    USE SIGNAL ;
    PORT
      LAYER M5 ;
        RECT 32.784 0.000 32.808 0.192 ;
    END
  END b_d[495]
  PIN b_d[496]
    DIRECTION INPUT ;
    USE SIGNAL ;
    PORT
      LAYER M3 ;
        RECT 32.829 0.000 32.853 0.192 ;
    END
  END b_d[496]
  PIN b_d[497]
    DIRECTION INPUT ;
    USE SIGNAL ;
    PORT
      LAYER M5 ;
        RECT 32.928 0.000 32.952 0.192 ;
    END
  END b_d[497]
  PIN b_d[498]
    DIRECTION INPUT ;
    USE SIGNAL ;
    PORT
      LAYER M3 ;
        RECT 32.973 0.000 32.997 0.192 ;
    END
  END b_d[498]
  PIN b_d[499]
    DIRECTION INPUT ;
    USE SIGNAL ;
    PORT
      LAYER M5 ;
        RECT 33.024 0.000 33.048 0.192 ;
    END
  END b_d[499]
  PIN b_d[500]
    DIRECTION INPUT ;
    USE SIGNAL ;
    PORT
      LAYER M3 ;
        RECT 33.081 0.000 33.105 0.192 ;
    END
  END b_d[500]
  PIN b_d[501]
    DIRECTION INPUT ;
    USE SIGNAL ;
    PORT
      LAYER M5 ;
        RECT 33.120 0.000 33.144 0.192 ;
    END
  END b_d[501]
  PIN b_d[502]
    DIRECTION INPUT ;
    USE SIGNAL ;
    PORT
      LAYER M3 ;
        RECT 33.189 0.000 33.213 0.192 ;
    END
  END b_d[502]
  PIN b_d[503]
    DIRECTION INPUT ;
    USE SIGNAL ;
    PORT
      LAYER M5 ;
        RECT 33.264 0.000 33.288 0.192 ;
    END
  END b_d[503]
  PIN b_d[504]
    DIRECTION INPUT ;
    USE SIGNAL ;
    PORT
      LAYER M3 ;
        RECT 33.333 0.000 33.357 0.192 ;
    END
  END b_d[504]
  PIN b_d[505]
    DIRECTION INPUT ;
    USE SIGNAL ;
    PORT
      LAYER M5 ;
        RECT 33.360 0.000 33.384 0.192 ;
    END
  END b_d[505]
  PIN b_d[506]
    DIRECTION INPUT ;
    USE SIGNAL ;
    PORT
      LAYER M3 ;
        RECT 33.441 0.000 33.465 0.192 ;
    END
  END b_d[506]
  PIN b_d[507]
    DIRECTION INPUT ;
    USE SIGNAL ;
    PORT
      LAYER M5 ;
        RECT 33.504 0.000 33.528 0.192 ;
    END
  END b_d[507]
  PIN b_d[508]
    DIRECTION INPUT ;
    USE SIGNAL ;
    PORT
      LAYER M3 ;
        RECT 33.549 0.000 33.573 0.192 ;
    END
  END b_d[508]
  PIN b_d[509]
    DIRECTION INPUT ;
    USE SIGNAL ;
    PORT
      LAYER M5 ;
        RECT 33.600 0.000 33.624 0.192 ;
    END
  END b_d[509]
  PIN b_d[510]
    DIRECTION INPUT ;
    USE SIGNAL ;
    PORT
      LAYER M3 ;
        RECT 33.693 0.000 33.717 0.192 ;
    END
  END b_d[510]
  PIN b_d[511]
    DIRECTION INPUT ;
    USE SIGNAL ;
    PORT
      LAYER M5 ;
        RECT 33.744 0.000 33.768 0.192 ;
    END
  END b_d[511]
  PIN b_d[512]
    DIRECTION INPUT ;
    USE SIGNAL ;
    PORT
      LAYER M3 ;
        RECT 33.801 0.000 33.825 0.192 ;
    END
  END b_d[512]
  PIN b_d[513]
    DIRECTION INPUT ;
    USE SIGNAL ;
    PORT
      LAYER M5 ;
        RECT 33.840 0.000 33.864 0.192 ;
    END
  END b_d[513]
  PIN b_d[514]
    DIRECTION INPUT ;
    USE SIGNAL ;
    PORT
      LAYER M3 ;
        RECT 33.909 0.000 33.933 0.192 ;
    END
  END b_d[514]
  PIN b_d[515]
    DIRECTION INPUT ;
    USE SIGNAL ;
    PORT
      LAYER M5 ;
        RECT 33.984 0.000 34.008 0.192 ;
    END
  END b_d[515]
  PIN ck
    DIRECTION INPUT ;
    USE CLOCK ;
    PORT
      LAYER M5 ;
        RECT 2.544 0.000 2.568 0.192 ;
    END
  END ck
  PIN rst_n
    DIRECTION INPUT ;
    USE SIGNAL ;
    PORT
      LAYER M5 ;
        RECT 1.872 0.000 1.896 0.192 ;
    END
  END rst_n
  PIN sidx[0]
    DIRECTION INPUT ;
    USE SIGNAL ;
    PORT
      LAYER M3 ;
        RECT 0.681 0.000 0.705 0.192 ;
    END
  END sidx[0]
  PIN sidx[1]
    DIRECTION INPUT ;
    USE SIGNAL ;
    PORT
      LAYER M5 ;
        RECT 0.960 0.000 0.984 0.192 ;
    END
  END sidx[1]
  PIN sidx[2]
    DIRECTION INPUT ;
    USE SIGNAL ;
    PORT
      LAYER M3 ;
        RECT 1.221 0.000 1.245 0.192 ;
    END
  END sidx[2]
  PIN a_d[0]
    DIRECTION OUTPUT ;
    USE SIGNAL ;
    PORT
      LAYER M3 ;
        RECT 0.573 86.208 0.597 86.400 ;
    END
  END a_d[0]
  PIN a_d[1]
    DIRECTION OUTPUT ;
    USE SIGNAL ;
    PORT
      LAYER M5 ;
        RECT 0.624 86.208 0.648 86.400 ;
    END
  END a_d[1]
  PIN a_d[2]
    DIRECTION OUTPUT ;
    USE SIGNAL ;
    PORT
      LAYER M3 ;
        RECT 0.681 86.208 0.705 86.400 ;
    END
  END a_d[2]
  PIN a_d[3]
    DIRECTION OUTPUT ;
    USE SIGNAL ;
    PORT
      LAYER M5 ;
        RECT 0.768 86.208 0.792 86.400 ;
    END
  END a_d[3]
  PIN a_d[4]
    DIRECTION OUTPUT ;
    USE SIGNAL ;
    PORT
      LAYER M3 ;
        RECT 0.825 86.208 0.849 86.400 ;
    END
  END a_d[4]
  PIN a_d[5]
    DIRECTION OUTPUT ;
    USE SIGNAL ;
    PORT
      LAYER M5 ;
        RECT 0.864 86.208 0.888 86.400 ;
    END
  END a_d[5]
  PIN a_d[6]
    DIRECTION OUTPUT ;
    USE SIGNAL ;
    PORT
      LAYER M3 ;
        RECT 0.933 86.208 0.957 86.400 ;
    END
  END a_d[6]
  PIN a_d[7]
    DIRECTION OUTPUT ;
    USE SIGNAL ;
    PORT
      LAYER M5 ;
        RECT 1.008 86.208 1.032 86.400 ;
    END
  END a_d[7]
  PIN a_d[8]
    DIRECTION OUTPUT ;
    USE SIGNAL ;
    PORT
      LAYER M3 ;
        RECT 1.077 86.208 1.101 86.400 ;
    END
  END a_d[8]
  PIN a_d[9]
    DIRECTION OUTPUT ;
    USE SIGNAL ;
    PORT
      LAYER M5 ;
        RECT 1.152 86.208 1.176 86.400 ;
    END
  END a_d[9]
  PIN a_d[10]
    DIRECTION OUTPUT ;
    USE SIGNAL ;
    PORT
      LAYER M3 ;
        RECT 1.221 86.208 1.245 86.400 ;
    END
  END a_d[10]
  PIN a_d[11]
    DIRECTION OUTPUT ;
    USE SIGNAL ;
    PORT
      LAYER M5 ;
        RECT 1.296 86.208 1.320 86.400 ;
    END
  END a_d[11]
  PIN a_d[12]
    DIRECTION OUTPUT ;
    USE SIGNAL ;
    PORT
      LAYER M3 ;
        RECT 1.329 86.208 1.353 86.400 ;
    END
  END a_d[12]
  PIN a_d[13]
    DIRECTION OUTPUT ;
    USE SIGNAL ;
    PORT
      LAYER M5 ;
        RECT 1.392 86.208 1.416 86.400 ;
    END
  END a_d[13]
  PIN a_d[14]
    DIRECTION OUTPUT ;
    USE SIGNAL ;
    PORT
      LAYER M3 ;
        RECT 1.473 86.208 1.497 86.400 ;
    END
  END a_d[14]
  PIN a_d[15]
    DIRECTION OUTPUT ;
    USE SIGNAL ;
    PORT
      LAYER M5 ;
        RECT 1.536 86.208 1.560 86.400 ;
    END
  END a_d[15]
  PIN a_d[16]
    DIRECTION OUTPUT ;
    USE SIGNAL ;
    PORT
      LAYER M3 ;
        RECT 1.581 86.208 1.605 86.400 ;
    END
  END a_d[16]
  PIN a_d[17]
    DIRECTION OUTPUT ;
    USE SIGNAL ;
    PORT
      LAYER M5 ;
        RECT 1.680 86.208 1.704 86.400 ;
    END
  END a_d[17]
  PIN a_d[18]
    DIRECTION OUTPUT ;
    USE SIGNAL ;
    PORT
      LAYER M3 ;
        RECT 1.725 86.208 1.749 86.400 ;
    END
  END a_d[18]
  PIN a_d[19]
    DIRECTION OUTPUT ;
    USE SIGNAL ;
    PORT
      LAYER M5 ;
        RECT 1.776 86.208 1.800 86.400 ;
    END
  END a_d[19]
  PIN a_d[20]
    DIRECTION OUTPUT ;
    USE SIGNAL ;
    PORT
      LAYER M3 ;
        RECT 1.869 86.208 1.893 86.400 ;
    END
  END a_d[20]
  PIN a_d[21]
    DIRECTION OUTPUT ;
    USE SIGNAL ;
    PORT
      LAYER M5 ;
        RECT 1.920 86.208 1.944 86.400 ;
    END
  END a_d[21]
  PIN a_d[22]
    DIRECTION OUTPUT ;
    USE SIGNAL ;
    PORT
      LAYER M3 ;
        RECT 1.977 86.208 2.001 86.400 ;
    END
  END a_d[22]
  PIN a_d[23]
    DIRECTION OUTPUT ;
    USE SIGNAL ;
    PORT
      LAYER M5 ;
        RECT 2.064 86.208 2.088 86.400 ;
    END
  END a_d[23]
  PIN a_d[24]
    DIRECTION OUTPUT ;
    USE SIGNAL ;
    PORT
      LAYER M3 ;
        RECT 2.121 86.208 2.145 86.400 ;
    END
  END a_d[24]
  PIN a_d[25]
    DIRECTION OUTPUT ;
    USE SIGNAL ;
    PORT
      LAYER M5 ;
        RECT 2.160 86.208 2.184 86.400 ;
    END
  END a_d[25]
  PIN a_d[26]
    DIRECTION OUTPUT ;
    USE SIGNAL ;
    PORT
      LAYER M3 ;
        RECT 2.265 86.208 2.289 86.400 ;
    END
  END a_d[26]
  PIN a_d[27]
    DIRECTION OUTPUT ;
    USE SIGNAL ;
    PORT
      LAYER M5 ;
        RECT 2.304 86.208 2.328 86.400 ;
    END
  END a_d[27]
  PIN a_d[28]
    DIRECTION OUTPUT ;
    USE SIGNAL ;
    PORT
      LAYER M3 ;
        RECT 2.373 86.208 2.397 86.400 ;
    END
  END a_d[28]
  PIN a_d[29]
    DIRECTION OUTPUT ;
    USE SIGNAL ;
    PORT
      LAYER M5 ;
        RECT 2.448 86.208 2.472 86.400 ;
    END
  END a_d[29]
  PIN a_d[30]
    DIRECTION OUTPUT ;
    USE SIGNAL ;
    PORT
      LAYER M3 ;
        RECT 2.517 86.208 2.541 86.400 ;
    END
  END a_d[30]
  PIN a_d[31]
    DIRECTION OUTPUT ;
    USE SIGNAL ;
    PORT
      LAYER M5 ;
        RECT 2.592 86.208 2.616 86.400 ;
    END
  END a_d[31]
  PIN a_d[32]
    DIRECTION OUTPUT ;
    USE SIGNAL ;
    PORT
      LAYER M3 ;
        RECT 2.625 86.208 2.649 86.400 ;
    END
  END a_d[32]
  PIN a_d[33]
    DIRECTION OUTPUT ;
    USE SIGNAL ;
    PORT
      LAYER M5 ;
        RECT 2.688 86.208 2.712 86.400 ;
    END
  END a_d[33]
  PIN a_d[34]
    DIRECTION OUTPUT ;
    USE SIGNAL ;
    PORT
      LAYER M3 ;
        RECT 2.769 86.208 2.793 86.400 ;
    END
  END a_d[34]
  PIN a_d[35]
    DIRECTION OUTPUT ;
    USE SIGNAL ;
    PORT
      LAYER M5 ;
        RECT 2.832 86.208 2.856 86.400 ;
    END
  END a_d[35]
  PIN a_d[36]
    DIRECTION OUTPUT ;
    USE SIGNAL ;
    PORT
      LAYER M3 ;
        RECT 2.913 86.208 2.937 86.400 ;
    END
  END a_d[36]
  PIN a_d[37]
    DIRECTION OUTPUT ;
    USE SIGNAL ;
    PORT
      LAYER M5 ;
        RECT 2.976 86.208 3.000 86.400 ;
    END
  END a_d[37]
  PIN a_d[38]
    DIRECTION OUTPUT ;
    USE SIGNAL ;
    PORT
      LAYER M3 ;
        RECT 3.021 86.208 3.045 86.400 ;
    END
  END a_d[38]
  PIN a_d[39]
    DIRECTION OUTPUT ;
    USE SIGNAL ;
    PORT
      LAYER M5 ;
        RECT 3.072 86.208 3.096 86.400 ;
    END
  END a_d[39]
  PIN a_d[40]
    DIRECTION OUTPUT ;
    USE SIGNAL ;
    PORT
      LAYER M3 ;
        RECT 3.165 86.208 3.189 86.400 ;
    END
  END a_d[40]
  PIN a_d[41]
    DIRECTION OUTPUT ;
    USE SIGNAL ;
    PORT
      LAYER M5 ;
        RECT 3.216 86.208 3.240 86.400 ;
    END
  END a_d[41]
  PIN a_d[42]
    DIRECTION OUTPUT ;
    USE SIGNAL ;
    PORT
      LAYER M3 ;
        RECT 3.273 86.208 3.297 86.400 ;
    END
  END a_d[42]
  PIN a_d[43]
    DIRECTION OUTPUT ;
    USE SIGNAL ;
    PORT
      LAYER M5 ;
        RECT 3.360 86.208 3.384 86.400 ;
    END
  END a_d[43]
  PIN a_d[44]
    DIRECTION OUTPUT ;
    USE SIGNAL ;
    PORT
      LAYER M3 ;
        RECT 3.417 86.208 3.441 86.400 ;
    END
  END a_d[44]
  PIN a_d[45]
    DIRECTION OUTPUT ;
    USE SIGNAL ;
    PORT
      LAYER M5 ;
        RECT 3.504 86.208 3.528 86.400 ;
    END
  END a_d[45]
  PIN a_d[46]
    DIRECTION OUTPUT ;
    USE SIGNAL ;
    PORT
      LAYER M3 ;
        RECT 3.561 86.208 3.585 86.400 ;
    END
  END a_d[46]
  PIN a_d[47]
    DIRECTION OUTPUT ;
    USE SIGNAL ;
    PORT
      LAYER M5 ;
        RECT 3.600 86.208 3.624 86.400 ;
    END
  END a_d[47]
  PIN a_d[48]
    DIRECTION OUTPUT ;
    USE SIGNAL ;
    PORT
      LAYER M3 ;
        RECT 3.669 86.208 3.693 86.400 ;
    END
  END a_d[48]
  PIN a_d[49]
    DIRECTION OUTPUT ;
    USE SIGNAL ;
    PORT
      LAYER M5 ;
        RECT 3.744 86.208 3.768 86.400 ;
    END
  END a_d[49]
  PIN a_d[50]
    DIRECTION OUTPUT ;
    USE SIGNAL ;
    PORT
      LAYER M3 ;
        RECT 3.813 86.208 3.837 86.400 ;
    END
  END a_d[50]
  PIN a_d[51]
    DIRECTION OUTPUT ;
    USE SIGNAL ;
    PORT
      LAYER M5 ;
        RECT 3.888 86.208 3.912 86.400 ;
    END
  END a_d[51]
  PIN a_d[52]
    DIRECTION OUTPUT ;
    USE SIGNAL ;
    PORT
      LAYER M3 ;
        RECT 3.921 86.208 3.945 86.400 ;
    END
  END a_d[52]
  PIN a_d[53]
    DIRECTION OUTPUT ;
    USE SIGNAL ;
    PORT
      LAYER M5 ;
        RECT 3.984 86.208 4.008 86.400 ;
    END
  END a_d[53]
  PIN a_d[54]
    DIRECTION OUTPUT ;
    USE SIGNAL ;
    PORT
      LAYER M3 ;
        RECT 4.065 86.208 4.089 86.400 ;
    END
  END a_d[54]
  PIN a_d[55]
    DIRECTION OUTPUT ;
    USE SIGNAL ;
    PORT
      LAYER M5 ;
        RECT 4.128 86.208 4.152 86.400 ;
    END
  END a_d[55]
  PIN a_d[56]
    DIRECTION OUTPUT ;
    USE SIGNAL ;
    PORT
      LAYER M3 ;
        RECT 4.209 86.208 4.233 86.400 ;
    END
  END a_d[56]
  PIN a_d[57]
    DIRECTION OUTPUT ;
    USE SIGNAL ;
    PORT
      LAYER M5 ;
        RECT 4.272 86.208 4.296 86.400 ;
    END
  END a_d[57]
  PIN a_d[58]
    DIRECTION OUTPUT ;
    USE SIGNAL ;
    PORT
      LAYER M3 ;
        RECT 4.317 86.208 4.341 86.400 ;
    END
  END a_d[58]
  PIN a_d[59]
    DIRECTION OUTPUT ;
    USE SIGNAL ;
    PORT
      LAYER M5 ;
        RECT 4.368 86.208 4.392 86.400 ;
    END
  END a_d[59]
  PIN a_d[60]
    DIRECTION OUTPUT ;
    USE SIGNAL ;
    PORT
      LAYER M3 ;
        RECT 4.461 86.208 4.485 86.400 ;
    END
  END a_d[60]
  PIN a_d[61]
    DIRECTION OUTPUT ;
    USE SIGNAL ;
    PORT
      LAYER M5 ;
        RECT 4.512 86.208 4.536 86.400 ;
    END
  END a_d[61]
  PIN a_d[62]
    DIRECTION OUTPUT ;
    USE SIGNAL ;
    PORT
      LAYER M3 ;
        RECT 4.569 86.208 4.593 86.400 ;
    END
  END a_d[62]
  PIN a_d[63]
    DIRECTION OUTPUT ;
    USE SIGNAL ;
    PORT
      LAYER M5 ;
        RECT 4.656 86.208 4.680 86.400 ;
    END
  END a_d[63]
  PIN a_d[64]
    DIRECTION OUTPUT ;
    USE SIGNAL ;
    PORT
      LAYER M3 ;
        RECT 4.713 86.208 4.737 86.400 ;
    END
  END a_d[64]
  PIN a_d[65]
    DIRECTION OUTPUT ;
    USE SIGNAL ;
    PORT
      LAYER M5 ;
        RECT 4.800 86.208 4.824 86.400 ;
    END
  END a_d[65]
  PIN a_d[66]
    DIRECTION OUTPUT ;
    USE SIGNAL ;
    PORT
      LAYER M3 ;
        RECT 4.857 86.208 4.881 86.400 ;
    END
  END a_d[66]
  PIN a_d[67]
    DIRECTION OUTPUT ;
    USE SIGNAL ;
    PORT
      LAYER M5 ;
        RECT 4.896 86.208 4.920 86.400 ;
    END
  END a_d[67]
  PIN a_d[68]
    DIRECTION OUTPUT ;
    USE SIGNAL ;
    PORT
      LAYER M3 ;
        RECT 4.965 86.208 4.989 86.400 ;
    END
  END a_d[68]
  PIN a_d[69]
    DIRECTION OUTPUT ;
    USE SIGNAL ;
    PORT
      LAYER M5 ;
        RECT 5.040 86.208 5.064 86.400 ;
    END
  END a_d[69]
  PIN a_d[70]
    DIRECTION OUTPUT ;
    USE SIGNAL ;
    PORT
      LAYER M3 ;
        RECT 5.109 86.208 5.133 86.400 ;
    END
  END a_d[70]
  PIN a_d[71]
    DIRECTION OUTPUT ;
    USE SIGNAL ;
    PORT
      LAYER M5 ;
        RECT 5.184 86.208 5.208 86.400 ;
    END
  END a_d[71]
  PIN a_d[72]
    DIRECTION OUTPUT ;
    USE SIGNAL ;
    PORT
      LAYER M3 ;
        RECT 5.217 86.208 5.241 86.400 ;
    END
  END a_d[72]
  PIN a_d[73]
    DIRECTION OUTPUT ;
    USE SIGNAL ;
    PORT
      LAYER M5 ;
        RECT 5.280 86.208 5.304 86.400 ;
    END
  END a_d[73]
  PIN a_d[74]
    DIRECTION OUTPUT ;
    USE SIGNAL ;
    PORT
      LAYER M3 ;
        RECT 5.361 86.208 5.385 86.400 ;
    END
  END a_d[74]
  PIN a_d[75]
    DIRECTION OUTPUT ;
    USE SIGNAL ;
    PORT
      LAYER M5 ;
        RECT 5.424 86.208 5.448 86.400 ;
    END
  END a_d[75]
  PIN a_d[76]
    DIRECTION OUTPUT ;
    USE SIGNAL ;
    PORT
      LAYER M3 ;
        RECT 5.505 86.208 5.529 86.400 ;
    END
  END a_d[76]
  PIN a_d[77]
    DIRECTION OUTPUT ;
    USE SIGNAL ;
    PORT
      LAYER M5 ;
        RECT 5.568 86.208 5.592 86.400 ;
    END
  END a_d[77]
  PIN a_d[78]
    DIRECTION OUTPUT ;
    USE SIGNAL ;
    PORT
      LAYER M3 ;
        RECT 5.613 86.208 5.637 86.400 ;
    END
  END a_d[78]
  PIN a_d[79]
    DIRECTION OUTPUT ;
    USE SIGNAL ;
    PORT
      LAYER M5 ;
        RECT 5.664 86.208 5.688 86.400 ;
    END
  END a_d[79]
  PIN a_d[80]
    DIRECTION OUTPUT ;
    USE SIGNAL ;
    PORT
      LAYER M3 ;
        RECT 5.757 86.208 5.781 86.400 ;
    END
  END a_d[80]
  PIN a_d[81]
    DIRECTION OUTPUT ;
    USE SIGNAL ;
    PORT
      LAYER M5 ;
        RECT 5.808 86.208 5.832 86.400 ;
    END
  END a_d[81]
  PIN a_d[82]
    DIRECTION OUTPUT ;
    USE SIGNAL ;
    PORT
      LAYER M3 ;
        RECT 5.865 86.208 5.889 86.400 ;
    END
  END a_d[82]
  PIN a_d[83]
    DIRECTION OUTPUT ;
    USE SIGNAL ;
    PORT
      LAYER M5 ;
        RECT 5.952 86.208 5.976 86.400 ;
    END
  END a_d[83]
  PIN a_d[84]
    DIRECTION OUTPUT ;
    USE SIGNAL ;
    PORT
      LAYER M3 ;
        RECT 6.009 86.208 6.033 86.400 ;
    END
  END a_d[84]
  PIN a_d[85]
    DIRECTION OUTPUT ;
    USE SIGNAL ;
    PORT
      LAYER M5 ;
        RECT 6.096 86.208 6.120 86.400 ;
    END
  END a_d[85]
  PIN a_d[86]
    DIRECTION OUTPUT ;
    USE SIGNAL ;
    PORT
      LAYER M3 ;
        RECT 6.153 86.208 6.177 86.400 ;
    END
  END a_d[86]
  PIN a_d[87]
    DIRECTION OUTPUT ;
    USE SIGNAL ;
    PORT
      LAYER M5 ;
        RECT 6.192 86.208 6.216 86.400 ;
    END
  END a_d[87]
  PIN a_d[88]
    DIRECTION OUTPUT ;
    USE SIGNAL ;
    PORT
      LAYER M3 ;
        RECT 6.261 86.208 6.285 86.400 ;
    END
  END a_d[88]
  PIN a_d[89]
    DIRECTION OUTPUT ;
    USE SIGNAL ;
    PORT
      LAYER M5 ;
        RECT 6.336 86.208 6.360 86.400 ;
    END
  END a_d[89]
  PIN a_d[90]
    DIRECTION OUTPUT ;
    USE SIGNAL ;
    PORT
      LAYER M3 ;
        RECT 6.405 86.208 6.429 86.400 ;
    END
  END a_d[90]
  PIN a_d[91]
    DIRECTION OUTPUT ;
    USE SIGNAL ;
    PORT
      LAYER M5 ;
        RECT 6.480 86.208 6.504 86.400 ;
    END
  END a_d[91]
  PIN a_d[92]
    DIRECTION OUTPUT ;
    USE SIGNAL ;
    PORT
      LAYER M3 ;
        RECT 6.513 86.208 6.537 86.400 ;
    END
  END a_d[92]
  PIN a_d[93]
    DIRECTION OUTPUT ;
    USE SIGNAL ;
    PORT
      LAYER M5 ;
        RECT 6.576 86.208 6.600 86.400 ;
    END
  END a_d[93]
  PIN a_d[94]
    DIRECTION OUTPUT ;
    USE SIGNAL ;
    PORT
      LAYER M3 ;
        RECT 6.657 86.208 6.681 86.400 ;
    END
  END a_d[94]
  PIN a_d[95]
    DIRECTION OUTPUT ;
    USE SIGNAL ;
    PORT
      LAYER M5 ;
        RECT 6.720 86.208 6.744 86.400 ;
    END
  END a_d[95]
  PIN a_d[96]
    DIRECTION OUTPUT ;
    USE SIGNAL ;
    PORT
      LAYER M3 ;
        RECT 6.801 86.208 6.825 86.400 ;
    END
  END a_d[96]
  PIN a_d[97]
    DIRECTION OUTPUT ;
    USE SIGNAL ;
    PORT
      LAYER M5 ;
        RECT 6.864 86.208 6.888 86.400 ;
    END
  END a_d[97]
  PIN a_d[98]
    DIRECTION OUTPUT ;
    USE SIGNAL ;
    PORT
      LAYER M3 ;
        RECT 6.909 86.208 6.933 86.400 ;
    END
  END a_d[98]
  PIN a_d[99]
    DIRECTION OUTPUT ;
    USE SIGNAL ;
    PORT
      LAYER M5 ;
        RECT 6.960 86.208 6.984 86.400 ;
    END
  END a_d[99]
  PIN a_d[100]
    DIRECTION OUTPUT ;
    USE SIGNAL ;
    PORT
      LAYER M3 ;
        RECT 7.053 86.208 7.077 86.400 ;
    END
  END a_d[100]
  PIN a_d[101]
    DIRECTION OUTPUT ;
    USE SIGNAL ;
    PORT
      LAYER M5 ;
        RECT 7.104 86.208 7.128 86.400 ;
    END
  END a_d[101]
  PIN a_d[102]
    DIRECTION OUTPUT ;
    USE SIGNAL ;
    PORT
      LAYER M3 ;
        RECT 7.161 86.208 7.185 86.400 ;
    END
  END a_d[102]
  PIN a_d[103]
    DIRECTION OUTPUT ;
    USE SIGNAL ;
    PORT
      LAYER M5 ;
        RECT 7.248 86.208 7.272 86.400 ;
    END
  END a_d[103]
  PIN a_d[104]
    DIRECTION OUTPUT ;
    USE SIGNAL ;
    PORT
      LAYER M3 ;
        RECT 7.305 86.208 7.329 86.400 ;
    END
  END a_d[104]
  PIN a_d[105]
    DIRECTION OUTPUT ;
    USE SIGNAL ;
    PORT
      LAYER M5 ;
        RECT 7.392 86.208 7.416 86.400 ;
    END
  END a_d[105]
  PIN a_d[106]
    DIRECTION OUTPUT ;
    USE SIGNAL ;
    PORT
      LAYER M3 ;
        RECT 7.449 86.208 7.473 86.400 ;
    END
  END a_d[106]
  PIN a_d[107]
    DIRECTION OUTPUT ;
    USE SIGNAL ;
    PORT
      LAYER M5 ;
        RECT 7.488 86.208 7.512 86.400 ;
    END
  END a_d[107]
  PIN a_d[108]
    DIRECTION OUTPUT ;
    USE SIGNAL ;
    PORT
      LAYER M3 ;
        RECT 7.557 86.208 7.581 86.400 ;
    END
  END a_d[108]
  PIN a_d[109]
    DIRECTION OUTPUT ;
    USE SIGNAL ;
    PORT
      LAYER M5 ;
        RECT 7.632 86.208 7.656 86.400 ;
    END
  END a_d[109]
  PIN a_d[110]
    DIRECTION OUTPUT ;
    USE SIGNAL ;
    PORT
      LAYER M3 ;
        RECT 7.701 86.208 7.725 86.400 ;
    END
  END a_d[110]
  PIN a_d[111]
    DIRECTION OUTPUT ;
    USE SIGNAL ;
    PORT
      LAYER M5 ;
        RECT 7.776 86.208 7.800 86.400 ;
    END
  END a_d[111]
  PIN a_d[112]
    DIRECTION OUTPUT ;
    USE SIGNAL ;
    PORT
      LAYER M3 ;
        RECT 7.845 86.208 7.869 86.400 ;
    END
  END a_d[112]
  PIN a_d[113]
    DIRECTION OUTPUT ;
    USE SIGNAL ;
    PORT
      LAYER M5 ;
        RECT 7.872 86.208 7.896 86.400 ;
    END
  END a_d[113]
  PIN a_d[114]
    DIRECTION OUTPUT ;
    USE SIGNAL ;
    PORT
      LAYER M3 ;
        RECT 7.953 86.208 7.977 86.400 ;
    END
  END a_d[114]
  PIN a_d[115]
    DIRECTION OUTPUT ;
    USE SIGNAL ;
    PORT
      LAYER M5 ;
        RECT 8.016 86.208 8.040 86.400 ;
    END
  END a_d[115]
  PIN a_d[116]
    DIRECTION OUTPUT ;
    USE SIGNAL ;
    PORT
      LAYER M3 ;
        RECT 8.097 86.208 8.121 86.400 ;
    END
  END a_d[116]
  PIN a_d[117]
    DIRECTION OUTPUT ;
    USE SIGNAL ;
    PORT
      LAYER M5 ;
        RECT 8.160 86.208 8.184 86.400 ;
    END
  END a_d[117]
  PIN a_d[118]
    DIRECTION OUTPUT ;
    USE SIGNAL ;
    PORT
      LAYER M3 ;
        RECT 8.205 86.208 8.229 86.400 ;
    END
  END a_d[118]
  PIN a_d[119]
    DIRECTION OUTPUT ;
    USE SIGNAL ;
    PORT
      LAYER M5 ;
        RECT 8.304 86.208 8.328 86.400 ;
    END
  END a_d[119]
  PIN a_d[120]
    DIRECTION OUTPUT ;
    USE SIGNAL ;
    PORT
      LAYER M3 ;
        RECT 8.349 86.208 8.373 86.400 ;
    END
  END a_d[120]
  PIN a_d[121]
    DIRECTION OUTPUT ;
    USE SIGNAL ;
    PORT
      LAYER M5 ;
        RECT 8.400 86.208 8.424 86.400 ;
    END
  END a_d[121]
  PIN a_d[122]
    DIRECTION OUTPUT ;
    USE SIGNAL ;
    PORT
      LAYER M3 ;
        RECT 8.493 86.208 8.517 86.400 ;
    END
  END a_d[122]
  PIN a_d[123]
    DIRECTION OUTPUT ;
    USE SIGNAL ;
    PORT
      LAYER M5 ;
        RECT 8.544 86.208 8.568 86.400 ;
    END
  END a_d[123]
  PIN a_d[124]
    DIRECTION OUTPUT ;
    USE SIGNAL ;
    PORT
      LAYER M3 ;
        RECT 8.601 86.208 8.625 86.400 ;
    END
  END a_d[124]
  PIN a_d[125]
    DIRECTION OUTPUT ;
    USE SIGNAL ;
    PORT
      LAYER M5 ;
        RECT 8.688 86.208 8.712 86.400 ;
    END
  END a_d[125]
  PIN a_d[126]
    DIRECTION OUTPUT ;
    USE SIGNAL ;
    PORT
      LAYER M3 ;
        RECT 8.745 86.208 8.769 86.400 ;
    END
  END a_d[126]
  PIN a_d[127]
    DIRECTION OUTPUT ;
    USE SIGNAL ;
    PORT
      LAYER M5 ;
        RECT 8.784 86.208 8.808 86.400 ;
    END
  END a_d[127]
  PIN a_d[128]
    DIRECTION OUTPUT ;
    USE SIGNAL ;
    PORT
      LAYER M3 ;
        RECT 8.853 86.208 8.877 86.400 ;
    END
  END a_d[128]
  PIN a_d[129]
    DIRECTION OUTPUT ;
    USE SIGNAL ;
    PORT
      LAYER M5 ;
        RECT 8.928 86.208 8.952 86.400 ;
    END
  END a_d[129]
  PIN a_d[130]
    DIRECTION OUTPUT ;
    USE SIGNAL ;
    PORT
      LAYER M3 ;
        RECT 8.997 86.208 9.021 86.400 ;
    END
  END a_d[130]
  PIN a_d[131]
    DIRECTION OUTPUT ;
    USE SIGNAL ;
    PORT
      LAYER M5 ;
        RECT 9.072 86.208 9.096 86.400 ;
    END
  END a_d[131]
  PIN a_d[132]
    DIRECTION OUTPUT ;
    USE SIGNAL ;
    PORT
      LAYER M3 ;
        RECT 9.141 86.208 9.165 86.400 ;
    END
  END a_d[132]
  PIN a_d[133]
    DIRECTION OUTPUT ;
    USE SIGNAL ;
    PORT
      LAYER M5 ;
        RECT 9.168 86.208 9.192 86.400 ;
    END
  END a_d[133]
  PIN a_d[134]
    DIRECTION OUTPUT ;
    USE SIGNAL ;
    PORT
      LAYER M3 ;
        RECT 9.249 86.208 9.273 86.400 ;
    END
  END a_d[134]
  PIN a_d[135]
    DIRECTION OUTPUT ;
    USE SIGNAL ;
    PORT
      LAYER M5 ;
        RECT 9.312 86.208 9.336 86.400 ;
    END
  END a_d[135]
  PIN a_d[136]
    DIRECTION OUTPUT ;
    USE SIGNAL ;
    PORT
      LAYER M3 ;
        RECT 9.393 86.208 9.417 86.400 ;
    END
  END a_d[136]
  PIN a_d[137]
    DIRECTION OUTPUT ;
    USE SIGNAL ;
    PORT
      LAYER M5 ;
        RECT 9.456 86.208 9.480 86.400 ;
    END
  END a_d[137]
  PIN a_d[138]
    DIRECTION OUTPUT ;
    USE SIGNAL ;
    PORT
      LAYER M3 ;
        RECT 9.501 86.208 9.525 86.400 ;
    END
  END a_d[138]
  PIN a_d[139]
    DIRECTION OUTPUT ;
    USE SIGNAL ;
    PORT
      LAYER M5 ;
        RECT 9.600 86.208 9.624 86.400 ;
    END
  END a_d[139]
  PIN a_d[140]
    DIRECTION OUTPUT ;
    USE SIGNAL ;
    PORT
      LAYER M3 ;
        RECT 9.645 86.208 9.669 86.400 ;
    END
  END a_d[140]
  PIN a_d[141]
    DIRECTION OUTPUT ;
    USE SIGNAL ;
    PORT
      LAYER M5 ;
        RECT 9.696 86.208 9.720 86.400 ;
    END
  END a_d[141]
  PIN a_d[142]
    DIRECTION OUTPUT ;
    USE SIGNAL ;
    PORT
      LAYER M3 ;
        RECT 9.789 86.208 9.813 86.400 ;
    END
  END a_d[142]
  PIN a_d[143]
    DIRECTION OUTPUT ;
    USE SIGNAL ;
    PORT
      LAYER M5 ;
        RECT 9.840 86.208 9.864 86.400 ;
    END
  END a_d[143]
  PIN a_d[144]
    DIRECTION OUTPUT ;
    USE SIGNAL ;
    PORT
      LAYER M3 ;
        RECT 9.897 86.208 9.921 86.400 ;
    END
  END a_d[144]
  PIN a_d[145]
    DIRECTION OUTPUT ;
    USE SIGNAL ;
    PORT
      LAYER M5 ;
        RECT 9.984 86.208 10.008 86.400 ;
    END
  END a_d[145]
  PIN a_d[146]
    DIRECTION OUTPUT ;
    USE SIGNAL ;
    PORT
      LAYER M3 ;
        RECT 10.041 86.208 10.065 86.400 ;
    END
  END a_d[146]
  PIN a_d[147]
    DIRECTION OUTPUT ;
    USE SIGNAL ;
    PORT
      LAYER M5 ;
        RECT 10.080 86.208 10.104 86.400 ;
    END
  END a_d[147]
  PIN a_d[148]
    DIRECTION OUTPUT ;
    USE SIGNAL ;
    PORT
      LAYER M3 ;
        RECT 10.149 86.208 10.173 86.400 ;
    END
  END a_d[148]
  PIN a_d[149]
    DIRECTION OUTPUT ;
    USE SIGNAL ;
    PORT
      LAYER M5 ;
        RECT 10.224 86.208 10.248 86.400 ;
    END
  END a_d[149]
  PIN a_d[150]
    DIRECTION OUTPUT ;
    USE SIGNAL ;
    PORT
      LAYER M3 ;
        RECT 10.293 86.208 10.317 86.400 ;
    END
  END a_d[150]
  PIN a_d[151]
    DIRECTION OUTPUT ;
    USE SIGNAL ;
    PORT
      LAYER M5 ;
        RECT 10.368 86.208 10.392 86.400 ;
    END
  END a_d[151]
  PIN a_d[152]
    DIRECTION OUTPUT ;
    USE SIGNAL ;
    PORT
      LAYER M3 ;
        RECT 10.437 86.208 10.461 86.400 ;
    END
  END a_d[152]
  PIN a_d[153]
    DIRECTION OUTPUT ;
    USE SIGNAL ;
    PORT
      LAYER M5 ;
        RECT 10.464 86.208 10.488 86.400 ;
    END
  END a_d[153]
  PIN a_d[154]
    DIRECTION OUTPUT ;
    USE SIGNAL ;
    PORT
      LAYER M3 ;
        RECT 10.545 86.208 10.569 86.400 ;
    END
  END a_d[154]
  PIN a_d[155]
    DIRECTION OUTPUT ;
    USE SIGNAL ;
    PORT
      LAYER M5 ;
        RECT 10.608 86.208 10.632 86.400 ;
    END
  END a_d[155]
  PIN a_d[156]
    DIRECTION OUTPUT ;
    USE SIGNAL ;
    PORT
      LAYER M3 ;
        RECT 10.689 86.208 10.713 86.400 ;
    END
  END a_d[156]
  PIN a_d[157]
    DIRECTION OUTPUT ;
    USE SIGNAL ;
    PORT
      LAYER M5 ;
        RECT 10.752 86.208 10.776 86.400 ;
    END
  END a_d[157]
  PIN a_d[158]
    DIRECTION OUTPUT ;
    USE SIGNAL ;
    PORT
      LAYER M3 ;
        RECT 10.797 86.208 10.821 86.400 ;
    END
  END a_d[158]
  PIN a_d[159]
    DIRECTION OUTPUT ;
    USE SIGNAL ;
    PORT
      LAYER M5 ;
        RECT 10.896 86.208 10.920 86.400 ;
    END
  END a_d[159]
  PIN a_d[160]
    DIRECTION OUTPUT ;
    USE SIGNAL ;
    PORT
      LAYER M3 ;
        RECT 10.941 86.208 10.965 86.400 ;
    END
  END a_d[160]
  PIN a_d[161]
    DIRECTION OUTPUT ;
    USE SIGNAL ;
    PORT
      LAYER M5 ;
        RECT 10.992 86.208 11.016 86.400 ;
    END
  END a_d[161]
  PIN a_d[162]
    DIRECTION OUTPUT ;
    USE SIGNAL ;
    PORT
      LAYER M3 ;
        RECT 11.085 86.208 11.109 86.400 ;
    END
  END a_d[162]
  PIN a_d[163]
    DIRECTION OUTPUT ;
    USE SIGNAL ;
    PORT
      LAYER M5 ;
        RECT 11.136 86.208 11.160 86.400 ;
    END
  END a_d[163]
  PIN a_d[164]
    DIRECTION OUTPUT ;
    USE SIGNAL ;
    PORT
      LAYER M3 ;
        RECT 11.193 86.208 11.217 86.400 ;
    END
  END a_d[164]
  PIN a_d[165]
    DIRECTION OUTPUT ;
    USE SIGNAL ;
    PORT
      LAYER M5 ;
        RECT 11.280 86.208 11.304 86.400 ;
    END
  END a_d[165]
  PIN a_d[166]
    DIRECTION OUTPUT ;
    USE SIGNAL ;
    PORT
      LAYER M3 ;
        RECT 11.337 86.208 11.361 86.400 ;
    END
  END a_d[166]
  PIN a_d[167]
    DIRECTION OUTPUT ;
    USE SIGNAL ;
    PORT
      LAYER M5 ;
        RECT 11.376 86.208 11.400 86.400 ;
    END
  END a_d[167]
  PIN a_d[168]
    DIRECTION OUTPUT ;
    USE SIGNAL ;
    PORT
      LAYER M3 ;
        RECT 11.445 86.208 11.469 86.400 ;
    END
  END a_d[168]
  PIN a_d[169]
    DIRECTION OUTPUT ;
    USE SIGNAL ;
    PORT
      LAYER M5 ;
        RECT 11.520 86.208 11.544 86.400 ;
    END
  END a_d[169]
  PIN a_d[170]
    DIRECTION OUTPUT ;
    USE SIGNAL ;
    PORT
      LAYER M3 ;
        RECT 11.589 86.208 11.613 86.400 ;
    END
  END a_d[170]
  PIN a_d[171]
    DIRECTION OUTPUT ;
    USE SIGNAL ;
    PORT
      LAYER M5 ;
        RECT 11.664 86.208 11.688 86.400 ;
    END
  END a_d[171]
  PIN a_d[172]
    DIRECTION OUTPUT ;
    USE SIGNAL ;
    PORT
      LAYER M3 ;
        RECT 11.733 86.208 11.757 86.400 ;
    END
  END a_d[172]
  PIN a_d[173]
    DIRECTION OUTPUT ;
    USE SIGNAL ;
    PORT
      LAYER M5 ;
        RECT 11.808 86.208 11.832 86.400 ;
    END
  END a_d[173]
  PIN a_d[174]
    DIRECTION OUTPUT ;
    USE SIGNAL ;
    PORT
      LAYER M3 ;
        RECT 11.841 86.208 11.865 86.400 ;
    END
  END a_d[174]
  PIN a_d[175]
    DIRECTION OUTPUT ;
    USE SIGNAL ;
    PORT
      LAYER M5 ;
        RECT 11.904 86.208 11.928 86.400 ;
    END
  END a_d[175]
  PIN a_d[176]
    DIRECTION OUTPUT ;
    USE SIGNAL ;
    PORT
      LAYER M3 ;
        RECT 11.985 86.208 12.009 86.400 ;
    END
  END a_d[176]
  PIN a_d[177]
    DIRECTION OUTPUT ;
    USE SIGNAL ;
    PORT
      LAYER M5 ;
        RECT 12.048 86.208 12.072 86.400 ;
    END
  END a_d[177]
  PIN a_d[178]
    DIRECTION OUTPUT ;
    USE SIGNAL ;
    PORT
      LAYER M3 ;
        RECT 12.093 86.208 12.117 86.400 ;
    END
  END a_d[178]
  PIN a_d[179]
    DIRECTION OUTPUT ;
    USE SIGNAL ;
    PORT
      LAYER M5 ;
        RECT 12.192 86.208 12.216 86.400 ;
    END
  END a_d[179]
  PIN a_d[180]
    DIRECTION OUTPUT ;
    USE SIGNAL ;
    PORT
      LAYER M3 ;
        RECT 12.237 86.208 12.261 86.400 ;
    END
  END a_d[180]
  PIN a_d[181]
    DIRECTION OUTPUT ;
    USE SIGNAL ;
    PORT
      LAYER M5 ;
        RECT 12.288 86.208 12.312 86.400 ;
    END
  END a_d[181]
  PIN a_d[182]
    DIRECTION OUTPUT ;
    USE SIGNAL ;
    PORT
      LAYER M3 ;
        RECT 12.381 86.208 12.405 86.400 ;
    END
  END a_d[182]
  PIN a_d[183]
    DIRECTION OUTPUT ;
    USE SIGNAL ;
    PORT
      LAYER M5 ;
        RECT 12.432 86.208 12.456 86.400 ;
    END
  END a_d[183]
  PIN a_d[184]
    DIRECTION OUTPUT ;
    USE SIGNAL ;
    PORT
      LAYER M3 ;
        RECT 12.489 86.208 12.513 86.400 ;
    END
  END a_d[184]
  PIN a_d[185]
    DIRECTION OUTPUT ;
    USE SIGNAL ;
    PORT
      LAYER M5 ;
        RECT 12.576 86.208 12.600 86.400 ;
    END
  END a_d[185]
  PIN a_d[186]
    DIRECTION OUTPUT ;
    USE SIGNAL ;
    PORT
      LAYER M3 ;
        RECT 12.633 86.208 12.657 86.400 ;
    END
  END a_d[186]
  PIN a_d[187]
    DIRECTION OUTPUT ;
    USE SIGNAL ;
    PORT
      LAYER M5 ;
        RECT 12.672 86.208 12.696 86.400 ;
    END
  END a_d[187]
  PIN a_d[188]
    DIRECTION OUTPUT ;
    USE SIGNAL ;
    PORT
      LAYER M3 ;
        RECT 12.741 86.208 12.765 86.400 ;
    END
  END a_d[188]
  PIN a_d[189]
    DIRECTION OUTPUT ;
    USE SIGNAL ;
    PORT
      LAYER M5 ;
        RECT 12.816 86.208 12.840 86.400 ;
    END
  END a_d[189]
  PIN a_d[190]
    DIRECTION OUTPUT ;
    USE SIGNAL ;
    PORT
      LAYER M3 ;
        RECT 12.885 86.208 12.909 86.400 ;
    END
  END a_d[190]
  PIN a_d[191]
    DIRECTION OUTPUT ;
    USE SIGNAL ;
    PORT
      LAYER M5 ;
        RECT 12.960 86.208 12.984 86.400 ;
    END
  END a_d[191]
  PIN a_d[192]
    DIRECTION OUTPUT ;
    USE SIGNAL ;
    PORT
      LAYER M3 ;
        RECT 13.029 86.208 13.053 86.400 ;
    END
  END a_d[192]
  PIN a_d[193]
    DIRECTION OUTPUT ;
    USE SIGNAL ;
    PORT
      LAYER M5 ;
        RECT 13.104 86.208 13.128 86.400 ;
    END
  END a_d[193]
  PIN a_d[194]
    DIRECTION OUTPUT ;
    USE SIGNAL ;
    PORT
      LAYER M3 ;
        RECT 13.137 86.208 13.161 86.400 ;
    END
  END a_d[194]
  PIN a_d[195]
    DIRECTION OUTPUT ;
    USE SIGNAL ;
    PORT
      LAYER M5 ;
        RECT 13.200 86.208 13.224 86.400 ;
    END
  END a_d[195]
  PIN a_d[196]
    DIRECTION OUTPUT ;
    USE SIGNAL ;
    PORT
      LAYER M3 ;
        RECT 13.281 86.208 13.305 86.400 ;
    END
  END a_d[196]
  PIN a_d[197]
    DIRECTION OUTPUT ;
    USE SIGNAL ;
    PORT
      LAYER M5 ;
        RECT 13.344 86.208 13.368 86.400 ;
    END
  END a_d[197]
  PIN a_d[198]
    DIRECTION OUTPUT ;
    USE SIGNAL ;
    PORT
      LAYER M3 ;
        RECT 13.425 86.208 13.449 86.400 ;
    END
  END a_d[198]
  PIN a_d[199]
    DIRECTION OUTPUT ;
    USE SIGNAL ;
    PORT
      LAYER M5 ;
        RECT 13.488 86.208 13.512 86.400 ;
    END
  END a_d[199]
  PIN a_d[200]
    DIRECTION OUTPUT ;
    USE SIGNAL ;
    PORT
      LAYER M3 ;
        RECT 13.533 86.208 13.557 86.400 ;
    END
  END a_d[200]
  PIN a_d[201]
    DIRECTION OUTPUT ;
    USE SIGNAL ;
    PORT
      LAYER M5 ;
        RECT 13.584 86.208 13.608 86.400 ;
    END
  END a_d[201]
  PIN a_d[202]
    DIRECTION OUTPUT ;
    USE SIGNAL ;
    PORT
      LAYER M3 ;
        RECT 13.677 86.208 13.701 86.400 ;
    END
  END a_d[202]
  PIN a_d[203]
    DIRECTION OUTPUT ;
    USE SIGNAL ;
    PORT
      LAYER M5 ;
        RECT 13.728 86.208 13.752 86.400 ;
    END
  END a_d[203]
  PIN a_d[204]
    DIRECTION OUTPUT ;
    USE SIGNAL ;
    PORT
      LAYER M3 ;
        RECT 13.785 86.208 13.809 86.400 ;
    END
  END a_d[204]
  PIN a_d[205]
    DIRECTION OUTPUT ;
    USE SIGNAL ;
    PORT
      LAYER M5 ;
        RECT 13.872 86.208 13.896 86.400 ;
    END
  END a_d[205]
  PIN a_d[206]
    DIRECTION OUTPUT ;
    USE SIGNAL ;
    PORT
      LAYER M3 ;
        RECT 13.929 86.208 13.953 86.400 ;
    END
  END a_d[206]
  PIN a_d[207]
    DIRECTION OUTPUT ;
    USE SIGNAL ;
    PORT
      LAYER M5 ;
        RECT 13.968 86.208 13.992 86.400 ;
    END
  END a_d[207]
  PIN a_d[208]
    DIRECTION OUTPUT ;
    USE SIGNAL ;
    PORT
      LAYER M3 ;
        RECT 14.073 86.208 14.097 86.400 ;
    END
  END a_d[208]
  PIN a_d[209]
    DIRECTION OUTPUT ;
    USE SIGNAL ;
    PORT
      LAYER M5 ;
        RECT 14.112 86.208 14.136 86.400 ;
    END
  END a_d[209]
  PIN a_d[210]
    DIRECTION OUTPUT ;
    USE SIGNAL ;
    PORT
      LAYER M3 ;
        RECT 14.181 86.208 14.205 86.400 ;
    END
  END a_d[210]
  PIN a_d[211]
    DIRECTION OUTPUT ;
    USE SIGNAL ;
    PORT
      LAYER M5 ;
        RECT 14.256 86.208 14.280 86.400 ;
    END
  END a_d[211]
  PIN a_d[212]
    DIRECTION OUTPUT ;
    USE SIGNAL ;
    PORT
      LAYER M3 ;
        RECT 14.325 86.208 14.349 86.400 ;
    END
  END a_d[212]
  PIN a_d[213]
    DIRECTION OUTPUT ;
    USE SIGNAL ;
    PORT
      LAYER M5 ;
        RECT 14.400 86.208 14.424 86.400 ;
    END
  END a_d[213]
  PIN a_d[214]
    DIRECTION OUTPUT ;
    USE SIGNAL ;
    PORT
      LAYER M3 ;
        RECT 14.433 86.208 14.457 86.400 ;
    END
  END a_d[214]
  PIN a_d[215]
    DIRECTION OUTPUT ;
    USE SIGNAL ;
    PORT
      LAYER M5 ;
        RECT 14.496 86.208 14.520 86.400 ;
    END
  END a_d[215]
  PIN a_d[216]
    DIRECTION OUTPUT ;
    USE SIGNAL ;
    PORT
      LAYER M3 ;
        RECT 14.577 86.208 14.601 86.400 ;
    END
  END a_d[216]
  PIN a_d[217]
    DIRECTION OUTPUT ;
    USE SIGNAL ;
    PORT
      LAYER M5 ;
        RECT 14.640 86.208 14.664 86.400 ;
    END
  END a_d[217]
  PIN a_d[218]
    DIRECTION OUTPUT ;
    USE SIGNAL ;
    PORT
      LAYER M3 ;
        RECT 14.721 86.208 14.745 86.400 ;
    END
  END a_d[218]
  PIN a_d[219]
    DIRECTION OUTPUT ;
    USE SIGNAL ;
    PORT
      LAYER M5 ;
        RECT 14.784 86.208 14.808 86.400 ;
    END
  END a_d[219]
  PIN a_d[220]
    DIRECTION OUTPUT ;
    USE SIGNAL ;
    PORT
      LAYER M3 ;
        RECT 14.829 86.208 14.853 86.400 ;
    END
  END a_d[220]
  PIN a_d[221]
    DIRECTION OUTPUT ;
    USE SIGNAL ;
    PORT
      LAYER M5 ;
        RECT 14.880 86.208 14.904 86.400 ;
    END
  END a_d[221]
  PIN a_d[222]
    DIRECTION OUTPUT ;
    USE SIGNAL ;
    PORT
      LAYER M3 ;
        RECT 14.973 86.208 14.997 86.400 ;
    END
  END a_d[222]
  PIN a_d[223]
    DIRECTION OUTPUT ;
    USE SIGNAL ;
    PORT
      LAYER M5 ;
        RECT 15.024 86.208 15.048 86.400 ;
    END
  END a_d[223]
  PIN a_d[224]
    DIRECTION OUTPUT ;
    USE SIGNAL ;
    PORT
      LAYER M3 ;
        RECT 15.081 86.208 15.105 86.400 ;
    END
  END a_d[224]
  PIN a_d[225]
    DIRECTION OUTPUT ;
    USE SIGNAL ;
    PORT
      LAYER M5 ;
        RECT 15.168 86.208 15.192 86.400 ;
    END
  END a_d[225]
  PIN a_d[226]
    DIRECTION OUTPUT ;
    USE SIGNAL ;
    PORT
      LAYER M3 ;
        RECT 15.225 86.208 15.249 86.400 ;
    END
  END a_d[226]
  PIN a_d[227]
    DIRECTION OUTPUT ;
    USE SIGNAL ;
    PORT
      LAYER M5 ;
        RECT 15.312 86.208 15.336 86.400 ;
    END
  END a_d[227]
  PIN a_d[228]
    DIRECTION OUTPUT ;
    USE SIGNAL ;
    PORT
      LAYER M3 ;
        RECT 15.369 86.208 15.393 86.400 ;
    END
  END a_d[228]
  PIN a_d[229]
    DIRECTION OUTPUT ;
    USE SIGNAL ;
    PORT
      LAYER M5 ;
        RECT 15.408 86.208 15.432 86.400 ;
    END
  END a_d[229]
  PIN a_d[230]
    DIRECTION OUTPUT ;
    USE SIGNAL ;
    PORT
      LAYER M3 ;
        RECT 15.477 86.208 15.501 86.400 ;
    END
  END a_d[230]
  PIN a_d[231]
    DIRECTION OUTPUT ;
    USE SIGNAL ;
    PORT
      LAYER M5 ;
        RECT 15.552 86.208 15.576 86.400 ;
    END
  END a_d[231]
  PIN a_d[232]
    DIRECTION OUTPUT ;
    USE SIGNAL ;
    PORT
      LAYER M3 ;
        RECT 15.621 86.208 15.645 86.400 ;
    END
  END a_d[232]
  PIN a_d[233]
    DIRECTION OUTPUT ;
    USE SIGNAL ;
    PORT
      LAYER M5 ;
        RECT 15.696 86.208 15.720 86.400 ;
    END
  END a_d[233]
  PIN a_d[234]
    DIRECTION OUTPUT ;
    USE SIGNAL ;
    PORT
      LAYER M3 ;
        RECT 15.729 86.208 15.753 86.400 ;
    END
  END a_d[234]
  PIN a_d[235]
    DIRECTION OUTPUT ;
    USE SIGNAL ;
    PORT
      LAYER M5 ;
        RECT 15.792 86.208 15.816 86.400 ;
    END
  END a_d[235]
  PIN a_d[236]
    DIRECTION OUTPUT ;
    USE SIGNAL ;
    PORT
      LAYER M3 ;
        RECT 15.873 86.208 15.897 86.400 ;
    END
  END a_d[236]
  PIN a_d[237]
    DIRECTION OUTPUT ;
    USE SIGNAL ;
    PORT
      LAYER M5 ;
        RECT 15.936 86.208 15.960 86.400 ;
    END
  END a_d[237]
  PIN a_d[238]
    DIRECTION OUTPUT ;
    USE SIGNAL ;
    PORT
      LAYER M3 ;
        RECT 16.017 86.208 16.041 86.400 ;
    END
  END a_d[238]
  PIN a_d[239]
    DIRECTION OUTPUT ;
    USE SIGNAL ;
    PORT
      LAYER M5 ;
        RECT 16.080 86.208 16.104 86.400 ;
    END
  END a_d[239]
  PIN a_d[240]
    DIRECTION OUTPUT ;
    USE SIGNAL ;
    PORT
      LAYER M3 ;
        RECT 16.125 86.208 16.149 86.400 ;
    END
  END a_d[240]
  PIN a_d[241]
    DIRECTION OUTPUT ;
    USE SIGNAL ;
    PORT
      LAYER M5 ;
        RECT 16.176 86.208 16.200 86.400 ;
    END
  END a_d[241]
  PIN a_d[242]
    DIRECTION OUTPUT ;
    USE SIGNAL ;
    PORT
      LAYER M3 ;
        RECT 16.269 86.208 16.293 86.400 ;
    END
  END a_d[242]
  PIN a_d[243]
    DIRECTION OUTPUT ;
    USE SIGNAL ;
    PORT
      LAYER M5 ;
        RECT 16.320 86.208 16.344 86.400 ;
    END
  END a_d[243]
  PIN a_d[244]
    DIRECTION OUTPUT ;
    USE SIGNAL ;
    PORT
      LAYER M3 ;
        RECT 16.377 86.208 16.401 86.400 ;
    END
  END a_d[244]
  PIN a_d[245]
    DIRECTION OUTPUT ;
    USE SIGNAL ;
    PORT
      LAYER M5 ;
        RECT 16.464 86.208 16.488 86.400 ;
    END
  END a_d[245]
  PIN a_d[246]
    DIRECTION OUTPUT ;
    USE SIGNAL ;
    PORT
      LAYER M3 ;
        RECT 16.521 86.208 16.545 86.400 ;
    END
  END a_d[246]
  PIN a_d[247]
    DIRECTION OUTPUT ;
    USE SIGNAL ;
    PORT
      LAYER M5 ;
        RECT 16.608 86.208 16.632 86.400 ;
    END
  END a_d[247]
  PIN a_d[248]
    DIRECTION OUTPUT ;
    USE SIGNAL ;
    PORT
      LAYER M3 ;
        RECT 16.665 86.208 16.689 86.400 ;
    END
  END a_d[248]
  PIN a_d[249]
    DIRECTION OUTPUT ;
    USE SIGNAL ;
    PORT
      LAYER M5 ;
        RECT 16.704 86.208 16.728 86.400 ;
    END
  END a_d[249]
  PIN a_d[250]
    DIRECTION OUTPUT ;
    USE SIGNAL ;
    PORT
      LAYER M3 ;
        RECT 16.773 86.208 16.797 86.400 ;
    END
  END a_d[250]
  PIN a_d[251]
    DIRECTION OUTPUT ;
    USE SIGNAL ;
    PORT
      LAYER M5 ;
        RECT 16.848 86.208 16.872 86.400 ;
    END
  END a_d[251]
  PIN a_d[252]
    DIRECTION OUTPUT ;
    USE SIGNAL ;
    PORT
      LAYER M3 ;
        RECT 16.917 86.208 16.941 86.400 ;
    END
  END a_d[252]
  PIN a_d[253]
    DIRECTION OUTPUT ;
    USE SIGNAL ;
    PORT
      LAYER M5 ;
        RECT 16.992 86.208 17.016 86.400 ;
    END
  END a_d[253]
  PIN a_d[254]
    DIRECTION OUTPUT ;
    USE SIGNAL ;
    PORT
      LAYER M3 ;
        RECT 17.025 86.208 17.049 86.400 ;
    END
  END a_d[254]
  PIN a_d[255]
    DIRECTION OUTPUT ;
    USE SIGNAL ;
    PORT
      LAYER M5 ;
        RECT 17.088 86.208 17.112 86.400 ;
    END
  END a_d[255]
  PIN a_d[256]
    DIRECTION OUTPUT ;
    USE SIGNAL ;
    PORT
      LAYER M3 ;
        RECT 17.169 86.208 17.193 86.400 ;
    END
  END a_d[256]
  PIN a_d[257]
    DIRECTION OUTPUT ;
    USE SIGNAL ;
    PORT
      LAYER M5 ;
        RECT 17.232 86.208 17.256 86.400 ;
    END
  END a_d[257]
  PIN a_d[258]
    DIRECTION OUTPUT ;
    USE SIGNAL ;
    PORT
      LAYER M3 ;
        RECT 17.313 86.208 17.337 86.400 ;
    END
  END a_d[258]
  PIN a_d[259]
    DIRECTION OUTPUT ;
    USE SIGNAL ;
    PORT
      LAYER M5 ;
        RECT 17.376 86.208 17.400 86.400 ;
    END
  END a_d[259]
  PIN a_d[260]
    DIRECTION OUTPUT ;
    USE SIGNAL ;
    PORT
      LAYER M3 ;
        RECT 17.421 86.208 17.445 86.400 ;
    END
  END a_d[260]
  PIN a_d[261]
    DIRECTION OUTPUT ;
    USE SIGNAL ;
    PORT
      LAYER M5 ;
        RECT 17.472 86.208 17.496 86.400 ;
    END
  END a_d[261]
  PIN a_d[262]
    DIRECTION OUTPUT ;
    USE SIGNAL ;
    PORT
      LAYER M3 ;
        RECT 17.565 86.208 17.589 86.400 ;
    END
  END a_d[262]
  PIN a_d[263]
    DIRECTION OUTPUT ;
    USE SIGNAL ;
    PORT
      LAYER M5 ;
        RECT 17.616 86.208 17.640 86.400 ;
    END
  END a_d[263]
  PIN a_d[264]
    DIRECTION OUTPUT ;
    USE SIGNAL ;
    PORT
      LAYER M3 ;
        RECT 17.673 86.208 17.697 86.400 ;
    END
  END a_d[264]
  PIN a_d[265]
    DIRECTION OUTPUT ;
    USE SIGNAL ;
    PORT
      LAYER M5 ;
        RECT 17.760 86.208 17.784 86.400 ;
    END
  END a_d[265]
  PIN a_d[266]
    DIRECTION OUTPUT ;
    USE SIGNAL ;
    PORT
      LAYER M3 ;
        RECT 17.817 86.208 17.841 86.400 ;
    END
  END a_d[266]
  PIN a_d[267]
    DIRECTION OUTPUT ;
    USE SIGNAL ;
    PORT
      LAYER M5 ;
        RECT 17.904 86.208 17.928 86.400 ;
    END
  END a_d[267]
  PIN a_d[268]
    DIRECTION OUTPUT ;
    USE SIGNAL ;
    PORT
      LAYER M3 ;
        RECT 17.961 86.208 17.985 86.400 ;
    END
  END a_d[268]
  PIN a_d[269]
    DIRECTION OUTPUT ;
    USE SIGNAL ;
    PORT
      LAYER M5 ;
        RECT 18.000 86.208 18.024 86.400 ;
    END
  END a_d[269]
  PIN a_d[270]
    DIRECTION OUTPUT ;
    USE SIGNAL ;
    PORT
      LAYER M3 ;
        RECT 18.069 86.208 18.093 86.400 ;
    END
  END a_d[270]
  PIN a_d[271]
    DIRECTION OUTPUT ;
    USE SIGNAL ;
    PORT
      LAYER M5 ;
        RECT 18.144 86.208 18.168 86.400 ;
    END
  END a_d[271]
  PIN a_d[272]
    DIRECTION OUTPUT ;
    USE SIGNAL ;
    PORT
      LAYER M3 ;
        RECT 18.213 86.208 18.237 86.400 ;
    END
  END a_d[272]
  PIN a_d[273]
    DIRECTION OUTPUT ;
    USE SIGNAL ;
    PORT
      LAYER M5 ;
        RECT 18.288 86.208 18.312 86.400 ;
    END
  END a_d[273]
  PIN a_d[274]
    DIRECTION OUTPUT ;
    USE SIGNAL ;
    PORT
      LAYER M3 ;
        RECT 18.321 86.208 18.345 86.400 ;
    END
  END a_d[274]
  PIN a_d[275]
    DIRECTION OUTPUT ;
    USE SIGNAL ;
    PORT
      LAYER M5 ;
        RECT 18.384 86.208 18.408 86.400 ;
    END
  END a_d[275]
  PIN a_d[276]
    DIRECTION OUTPUT ;
    USE SIGNAL ;
    PORT
      LAYER M3 ;
        RECT 18.465 86.208 18.489 86.400 ;
    END
  END a_d[276]
  PIN a_d[277]
    DIRECTION OUTPUT ;
    USE SIGNAL ;
    PORT
      LAYER M5 ;
        RECT 18.528 86.208 18.552 86.400 ;
    END
  END a_d[277]
  PIN a_d[278]
    DIRECTION OUTPUT ;
    USE SIGNAL ;
    PORT
      LAYER M3 ;
        RECT 18.609 86.208 18.633 86.400 ;
    END
  END a_d[278]
  PIN a_d[279]
    DIRECTION OUTPUT ;
    USE SIGNAL ;
    PORT
      LAYER M5 ;
        RECT 18.672 86.208 18.696 86.400 ;
    END
  END a_d[279]
  PIN a_d[280]
    DIRECTION OUTPUT ;
    USE SIGNAL ;
    PORT
      LAYER M3 ;
        RECT 18.717 86.208 18.741 86.400 ;
    END
  END a_d[280]
  PIN a_d[281]
    DIRECTION OUTPUT ;
    USE SIGNAL ;
    PORT
      LAYER M5 ;
        RECT 18.816 86.208 18.840 86.400 ;
    END
  END a_d[281]
  PIN a_d[282]
    DIRECTION OUTPUT ;
    USE SIGNAL ;
    PORT
      LAYER M3 ;
        RECT 18.861 86.208 18.885 86.400 ;
    END
  END a_d[282]
  PIN a_d[283]
    DIRECTION OUTPUT ;
    USE SIGNAL ;
    PORT
      LAYER M5 ;
        RECT 18.912 86.208 18.936 86.400 ;
    END
  END a_d[283]
  PIN a_d[284]
    DIRECTION OUTPUT ;
    USE SIGNAL ;
    PORT
      LAYER M3 ;
        RECT 19.005 86.208 19.029 86.400 ;
    END
  END a_d[284]
  PIN a_d[285]
    DIRECTION OUTPUT ;
    USE SIGNAL ;
    PORT
      LAYER M5 ;
        RECT 19.056 86.208 19.080 86.400 ;
    END
  END a_d[285]
  PIN a_d[286]
    DIRECTION OUTPUT ;
    USE SIGNAL ;
    PORT
      LAYER M3 ;
        RECT 19.113 86.208 19.137 86.400 ;
    END
  END a_d[286]
  PIN a_d[287]
    DIRECTION OUTPUT ;
    USE SIGNAL ;
    PORT
      LAYER M5 ;
        RECT 19.200 86.208 19.224 86.400 ;
    END
  END a_d[287]
  PIN a_d[288]
    DIRECTION OUTPUT ;
    USE SIGNAL ;
    PORT
      LAYER M3 ;
        RECT 19.257 86.208 19.281 86.400 ;
    END
  END a_d[288]
  PIN a_d[289]
    DIRECTION OUTPUT ;
    USE SIGNAL ;
    PORT
      LAYER M5 ;
        RECT 19.296 86.208 19.320 86.400 ;
    END
  END a_d[289]
  PIN a_d[290]
    DIRECTION OUTPUT ;
    USE SIGNAL ;
    PORT
      LAYER M3 ;
        RECT 19.365 86.208 19.389 86.400 ;
    END
  END a_d[290]
  PIN a_d[291]
    DIRECTION OUTPUT ;
    USE SIGNAL ;
    PORT
      LAYER M5 ;
        RECT 19.440 86.208 19.464 86.400 ;
    END
  END a_d[291]
  PIN a_d[292]
    DIRECTION OUTPUT ;
    USE SIGNAL ;
    PORT
      LAYER M3 ;
        RECT 19.509 86.208 19.533 86.400 ;
    END
  END a_d[292]
  PIN a_d[293]
    DIRECTION OUTPUT ;
    USE SIGNAL ;
    PORT
      LAYER M5 ;
        RECT 19.584 86.208 19.608 86.400 ;
    END
  END a_d[293]
  PIN a_d[294]
    DIRECTION OUTPUT ;
    USE SIGNAL ;
    PORT
      LAYER M3 ;
        RECT 19.653 86.208 19.677 86.400 ;
    END
  END a_d[294]
  PIN a_d[295]
    DIRECTION OUTPUT ;
    USE SIGNAL ;
    PORT
      LAYER M5 ;
        RECT 19.680 86.208 19.704 86.400 ;
    END
  END a_d[295]
  PIN a_d[296]
    DIRECTION OUTPUT ;
    USE SIGNAL ;
    PORT
      LAYER M3 ;
        RECT 19.761 86.208 19.785 86.400 ;
    END
  END a_d[296]
  PIN a_d[297]
    DIRECTION OUTPUT ;
    USE SIGNAL ;
    PORT
      LAYER M5 ;
        RECT 19.824 86.208 19.848 86.400 ;
    END
  END a_d[297]
  PIN a_d[298]
    DIRECTION OUTPUT ;
    USE SIGNAL ;
    PORT
      LAYER M3 ;
        RECT 19.905 86.208 19.929 86.400 ;
    END
  END a_d[298]
  PIN a_d[299]
    DIRECTION OUTPUT ;
    USE SIGNAL ;
    PORT
      LAYER M5 ;
        RECT 19.968 86.208 19.992 86.400 ;
    END
  END a_d[299]
  PIN a_d[300]
    DIRECTION OUTPUT ;
    USE SIGNAL ;
    PORT
      LAYER M3 ;
        RECT 20.013 86.208 20.037 86.400 ;
    END
  END a_d[300]
  PIN a_d[301]
    DIRECTION OUTPUT ;
    USE SIGNAL ;
    PORT
      LAYER M5 ;
        RECT 20.112 86.208 20.136 86.400 ;
    END
  END a_d[301]
  PIN a_d[302]
    DIRECTION OUTPUT ;
    USE SIGNAL ;
    PORT
      LAYER M3 ;
        RECT 20.157 86.208 20.181 86.400 ;
    END
  END a_d[302]
  PIN a_d[303]
    DIRECTION OUTPUT ;
    USE SIGNAL ;
    PORT
      LAYER M5 ;
        RECT 20.208 86.208 20.232 86.400 ;
    END
  END a_d[303]
  PIN a_d[304]
    DIRECTION OUTPUT ;
    USE SIGNAL ;
    PORT
      LAYER M3 ;
        RECT 20.301 86.208 20.325 86.400 ;
    END
  END a_d[304]
  PIN a_d[305]
    DIRECTION OUTPUT ;
    USE SIGNAL ;
    PORT
      LAYER M5 ;
        RECT 20.352 86.208 20.376 86.400 ;
    END
  END a_d[305]
  PIN a_d[306]
    DIRECTION OUTPUT ;
    USE SIGNAL ;
    PORT
      LAYER M3 ;
        RECT 20.409 86.208 20.433 86.400 ;
    END
  END a_d[306]
  PIN a_d[307]
    DIRECTION OUTPUT ;
    USE SIGNAL ;
    PORT
      LAYER M5 ;
        RECT 20.496 86.208 20.520 86.400 ;
    END
  END a_d[307]
  PIN a_d[308]
    DIRECTION OUTPUT ;
    USE SIGNAL ;
    PORT
      LAYER M3 ;
        RECT 20.553 86.208 20.577 86.400 ;
    END
  END a_d[308]
  PIN a_d[309]
    DIRECTION OUTPUT ;
    USE SIGNAL ;
    PORT
      LAYER M5 ;
        RECT 20.592 86.208 20.616 86.400 ;
    END
  END a_d[309]
  PIN a_d[310]
    DIRECTION OUTPUT ;
    USE SIGNAL ;
    PORT
      LAYER M3 ;
        RECT 20.661 86.208 20.685 86.400 ;
    END
  END a_d[310]
  PIN a_d[311]
    DIRECTION OUTPUT ;
    USE SIGNAL ;
    PORT
      LAYER M5 ;
        RECT 20.736 86.208 20.760 86.400 ;
    END
  END a_d[311]
  PIN a_d[312]
    DIRECTION OUTPUT ;
    USE SIGNAL ;
    PORT
      LAYER M3 ;
        RECT 20.805 86.208 20.829 86.400 ;
    END
  END a_d[312]
  PIN a_d[313]
    DIRECTION OUTPUT ;
    USE SIGNAL ;
    PORT
      LAYER M5 ;
        RECT 20.880 86.208 20.904 86.400 ;
    END
  END a_d[313]
  PIN a_d[314]
    DIRECTION OUTPUT ;
    USE SIGNAL ;
    PORT
      LAYER M3 ;
        RECT 20.949 86.208 20.973 86.400 ;
    END
  END a_d[314]
  PIN a_d[315]
    DIRECTION OUTPUT ;
    USE SIGNAL ;
    PORT
      LAYER M5 ;
        RECT 20.976 86.208 21.000 86.400 ;
    END
  END a_d[315]
  PIN a_d[316]
    DIRECTION OUTPUT ;
    USE SIGNAL ;
    PORT
      LAYER M3 ;
        RECT 21.057 86.208 21.081 86.400 ;
    END
  END a_d[316]
  PIN a_d[317]
    DIRECTION OUTPUT ;
    USE SIGNAL ;
    PORT
      LAYER M5 ;
        RECT 21.120 86.208 21.144 86.400 ;
    END
  END a_d[317]
  PIN a_d[318]
    DIRECTION OUTPUT ;
    USE SIGNAL ;
    PORT
      LAYER M3 ;
        RECT 21.201 86.208 21.225 86.400 ;
    END
  END a_d[318]
  PIN a_d[319]
    DIRECTION OUTPUT ;
    USE SIGNAL ;
    PORT
      LAYER M5 ;
        RECT 21.264 86.208 21.288 86.400 ;
    END
  END a_d[319]
  PIN a_d[320]
    DIRECTION OUTPUT ;
    USE SIGNAL ;
    PORT
      LAYER M3 ;
        RECT 21.309 86.208 21.333 86.400 ;
    END
  END a_d[320]
  PIN a_d[321]
    DIRECTION OUTPUT ;
    USE SIGNAL ;
    PORT
      LAYER M5 ;
        RECT 21.408 86.208 21.432 86.400 ;
    END
  END a_d[321]
  PIN a_d[322]
    DIRECTION OUTPUT ;
    USE SIGNAL ;
    PORT
      LAYER M3 ;
        RECT 21.453 86.208 21.477 86.400 ;
    END
  END a_d[322]
  PIN a_d[323]
    DIRECTION OUTPUT ;
    USE SIGNAL ;
    PORT
      LAYER M5 ;
        RECT 21.504 86.208 21.528 86.400 ;
    END
  END a_d[323]
  PIN a_d[324]
    DIRECTION OUTPUT ;
    USE SIGNAL ;
    PORT
      LAYER M3 ;
        RECT 21.597 86.208 21.621 86.400 ;
    END
  END a_d[324]
  PIN a_d[325]
    DIRECTION OUTPUT ;
    USE SIGNAL ;
    PORT
      LAYER M5 ;
        RECT 21.648 86.208 21.672 86.400 ;
    END
  END a_d[325]
  PIN a_d[326]
    DIRECTION OUTPUT ;
    USE SIGNAL ;
    PORT
      LAYER M3 ;
        RECT 21.705 86.208 21.729 86.400 ;
    END
  END a_d[326]
  PIN a_d[327]
    DIRECTION OUTPUT ;
    USE SIGNAL ;
    PORT
      LAYER M5 ;
        RECT 21.792 86.208 21.816 86.400 ;
    END
  END a_d[327]
  PIN a_d[328]
    DIRECTION OUTPUT ;
    USE SIGNAL ;
    PORT
      LAYER M3 ;
        RECT 21.849 86.208 21.873 86.400 ;
    END
  END a_d[328]
  PIN a_d[329]
    DIRECTION OUTPUT ;
    USE SIGNAL ;
    PORT
      LAYER M5 ;
        RECT 21.888 86.208 21.912 86.400 ;
    END
  END a_d[329]
  PIN a_d[330]
    DIRECTION OUTPUT ;
    USE SIGNAL ;
    PORT
      LAYER M3 ;
        RECT 21.957 86.208 21.981 86.400 ;
    END
  END a_d[330]
  PIN a_d[331]
    DIRECTION OUTPUT ;
    USE SIGNAL ;
    PORT
      LAYER M5 ;
        RECT 22.032 86.208 22.056 86.400 ;
    END
  END a_d[331]
  PIN a_d[332]
    DIRECTION OUTPUT ;
    USE SIGNAL ;
    PORT
      LAYER M3 ;
        RECT 22.101 86.208 22.125 86.400 ;
    END
  END a_d[332]
  PIN a_d[333]
    DIRECTION OUTPUT ;
    USE SIGNAL ;
    PORT
      LAYER M5 ;
        RECT 22.176 86.208 22.200 86.400 ;
    END
  END a_d[333]
  PIN a_d[334]
    DIRECTION OUTPUT ;
    USE SIGNAL ;
    PORT
      LAYER M3 ;
        RECT 22.245 86.208 22.269 86.400 ;
    END
  END a_d[334]
  PIN a_d[335]
    DIRECTION OUTPUT ;
    USE SIGNAL ;
    PORT
      LAYER M5 ;
        RECT 22.320 86.208 22.344 86.400 ;
    END
  END a_d[335]
  PIN a_d[336]
    DIRECTION OUTPUT ;
    USE SIGNAL ;
    PORT
      LAYER M3 ;
        RECT 22.353 86.208 22.377 86.400 ;
    END
  END a_d[336]
  PIN a_d[337]
    DIRECTION OUTPUT ;
    USE SIGNAL ;
    PORT
      LAYER M5 ;
        RECT 22.416 86.208 22.440 86.400 ;
    END
  END a_d[337]
  PIN a_d[338]
    DIRECTION OUTPUT ;
    USE SIGNAL ;
    PORT
      LAYER M3 ;
        RECT 22.497 86.208 22.521 86.400 ;
    END
  END a_d[338]
  PIN a_d[339]
    DIRECTION OUTPUT ;
    USE SIGNAL ;
    PORT
      LAYER M5 ;
        RECT 22.560 86.208 22.584 86.400 ;
    END
  END a_d[339]
  PIN a_d[340]
    DIRECTION OUTPUT ;
    USE SIGNAL ;
    PORT
      LAYER M3 ;
        RECT 22.605 86.208 22.629 86.400 ;
    END
  END a_d[340]
  PIN a_d[341]
    DIRECTION OUTPUT ;
    USE SIGNAL ;
    PORT
      LAYER M5 ;
        RECT 22.704 86.208 22.728 86.400 ;
    END
  END a_d[341]
  PIN a_d[342]
    DIRECTION OUTPUT ;
    USE SIGNAL ;
    PORT
      LAYER M3 ;
        RECT 22.749 86.208 22.773 86.400 ;
    END
  END a_d[342]
  PIN a_d[343]
    DIRECTION OUTPUT ;
    USE SIGNAL ;
    PORT
      LAYER M5 ;
        RECT 22.800 86.208 22.824 86.400 ;
    END
  END a_d[343]
  PIN a_d[344]
    DIRECTION OUTPUT ;
    USE SIGNAL ;
    PORT
      LAYER M3 ;
        RECT 22.893 86.208 22.917 86.400 ;
    END
  END a_d[344]
  PIN a_d[345]
    DIRECTION OUTPUT ;
    USE SIGNAL ;
    PORT
      LAYER M5 ;
        RECT 22.944 86.208 22.968 86.400 ;
    END
  END a_d[345]
  PIN a_d[346]
    DIRECTION OUTPUT ;
    USE SIGNAL ;
    PORT
      LAYER M3 ;
        RECT 23.001 86.208 23.025 86.400 ;
    END
  END a_d[346]
  PIN a_d[347]
    DIRECTION OUTPUT ;
    USE SIGNAL ;
    PORT
      LAYER M5 ;
        RECT 23.088 86.208 23.112 86.400 ;
    END
  END a_d[347]
  PIN a_d[348]
    DIRECTION OUTPUT ;
    USE SIGNAL ;
    PORT
      LAYER M3 ;
        RECT 23.145 86.208 23.169 86.400 ;
    END
  END a_d[348]
  PIN a_d[349]
    DIRECTION OUTPUT ;
    USE SIGNAL ;
    PORT
      LAYER M5 ;
        RECT 23.184 86.208 23.208 86.400 ;
    END
  END a_d[349]
  PIN a_d[350]
    DIRECTION OUTPUT ;
    USE SIGNAL ;
    PORT
      LAYER M3 ;
        RECT 23.253 86.208 23.277 86.400 ;
    END
  END a_d[350]
  PIN a_d[351]
    DIRECTION OUTPUT ;
    USE SIGNAL ;
    PORT
      LAYER M5 ;
        RECT 23.328 86.208 23.352 86.400 ;
    END
  END a_d[351]
  PIN a_d[352]
    DIRECTION OUTPUT ;
    USE SIGNAL ;
    PORT
      LAYER M3 ;
        RECT 23.397 86.208 23.421 86.400 ;
    END
  END a_d[352]
  PIN a_d[353]
    DIRECTION OUTPUT ;
    USE SIGNAL ;
    PORT
      LAYER M5 ;
        RECT 23.472 86.208 23.496 86.400 ;
    END
  END a_d[353]
  PIN a_d[354]
    DIRECTION OUTPUT ;
    USE SIGNAL ;
    PORT
      LAYER M3 ;
        RECT 23.541 86.208 23.565 86.400 ;
    END
  END a_d[354]
  PIN a_d[355]
    DIRECTION OUTPUT ;
    USE SIGNAL ;
    PORT
      LAYER M5 ;
        RECT 23.616 86.208 23.640 86.400 ;
    END
  END a_d[355]
  PIN a_d[356]
    DIRECTION OUTPUT ;
    USE SIGNAL ;
    PORT
      LAYER M3 ;
        RECT 23.649 86.208 23.673 86.400 ;
    END
  END a_d[356]
  PIN a_d[357]
    DIRECTION OUTPUT ;
    USE SIGNAL ;
    PORT
      LAYER M5 ;
        RECT 23.712 86.208 23.736 86.400 ;
    END
  END a_d[357]
  PIN a_d[358]
    DIRECTION OUTPUT ;
    USE SIGNAL ;
    PORT
      LAYER M3 ;
        RECT 23.793 86.208 23.817 86.400 ;
    END
  END a_d[358]
  PIN a_d[359]
    DIRECTION OUTPUT ;
    USE SIGNAL ;
    PORT
      LAYER M5 ;
        RECT 23.856 86.208 23.880 86.400 ;
    END
  END a_d[359]
  PIN a_d[360]
    DIRECTION OUTPUT ;
    USE SIGNAL ;
    PORT
      LAYER M3 ;
        RECT 23.901 86.208 23.925 86.400 ;
    END
  END a_d[360]
  PIN a_d[361]
    DIRECTION OUTPUT ;
    USE SIGNAL ;
    PORT
      LAYER M5 ;
        RECT 24.000 86.208 24.024 86.400 ;
    END
  END a_d[361]
  PIN a_d[362]
    DIRECTION OUTPUT ;
    USE SIGNAL ;
    PORT
      LAYER M3 ;
        RECT 24.045 86.208 24.069 86.400 ;
    END
  END a_d[362]
  PIN a_d[363]
    DIRECTION OUTPUT ;
    USE SIGNAL ;
    PORT
      LAYER M5 ;
        RECT 24.096 86.208 24.120 86.400 ;
    END
  END a_d[363]
  PIN a_d[364]
    DIRECTION OUTPUT ;
    USE SIGNAL ;
    PORT
      LAYER M3 ;
        RECT 24.189 86.208 24.213 86.400 ;
    END
  END a_d[364]
  PIN a_d[365]
    DIRECTION OUTPUT ;
    USE SIGNAL ;
    PORT
      LAYER M5 ;
        RECT 24.240 86.208 24.264 86.400 ;
    END
  END a_d[365]
  PIN a_d[366]
    DIRECTION OUTPUT ;
    USE SIGNAL ;
    PORT
      LAYER M3 ;
        RECT 24.297 86.208 24.321 86.400 ;
    END
  END a_d[366]
  PIN a_d[367]
    DIRECTION OUTPUT ;
    USE SIGNAL ;
    PORT
      LAYER M5 ;
        RECT 24.384 86.208 24.408 86.400 ;
    END
  END a_d[367]
  PIN a_d[368]
    DIRECTION OUTPUT ;
    USE SIGNAL ;
    PORT
      LAYER M3 ;
        RECT 24.441 86.208 24.465 86.400 ;
    END
  END a_d[368]
  PIN a_d[369]
    DIRECTION OUTPUT ;
    USE SIGNAL ;
    PORT
      LAYER M5 ;
        RECT 24.480 86.208 24.504 86.400 ;
    END
  END a_d[369]
  PIN a_d[370]
    DIRECTION OUTPUT ;
    USE SIGNAL ;
    PORT
      LAYER M3 ;
        RECT 24.585 86.208 24.609 86.400 ;
    END
  END a_d[370]
  PIN a_d[371]
    DIRECTION OUTPUT ;
    USE SIGNAL ;
    PORT
      LAYER M5 ;
        RECT 24.624 86.208 24.648 86.400 ;
    END
  END a_d[371]
  PIN a_d[372]
    DIRECTION OUTPUT ;
    USE SIGNAL ;
    PORT
      LAYER M3 ;
        RECT 24.693 86.208 24.717 86.400 ;
    END
  END a_d[372]
  PIN a_d[373]
    DIRECTION OUTPUT ;
    USE SIGNAL ;
    PORT
      LAYER M5 ;
        RECT 24.768 86.208 24.792 86.400 ;
    END
  END a_d[373]
  PIN a_d[374]
    DIRECTION OUTPUT ;
    USE SIGNAL ;
    PORT
      LAYER M3 ;
        RECT 24.837 86.208 24.861 86.400 ;
    END
  END a_d[374]
  PIN a_d[375]
    DIRECTION OUTPUT ;
    USE SIGNAL ;
    PORT
      LAYER M5 ;
        RECT 24.912 86.208 24.936 86.400 ;
    END
  END a_d[375]
  PIN a_d[376]
    DIRECTION OUTPUT ;
    USE SIGNAL ;
    PORT
      LAYER M3 ;
        RECT 24.945 86.208 24.969 86.400 ;
    END
  END a_d[376]
  PIN a_d[377]
    DIRECTION OUTPUT ;
    USE SIGNAL ;
    PORT
      LAYER M5 ;
        RECT 25.008 86.208 25.032 86.400 ;
    END
  END a_d[377]
  PIN a_d[378]
    DIRECTION OUTPUT ;
    USE SIGNAL ;
    PORT
      LAYER M3 ;
        RECT 25.089 86.208 25.113 86.400 ;
    END
  END a_d[378]
  PIN a_d[379]
    DIRECTION OUTPUT ;
    USE SIGNAL ;
    PORT
      LAYER M5 ;
        RECT 25.152 86.208 25.176 86.400 ;
    END
  END a_d[379]
  PIN a_d[380]
    DIRECTION OUTPUT ;
    USE SIGNAL ;
    PORT
      LAYER M3 ;
        RECT 25.233 86.208 25.257 86.400 ;
    END
  END a_d[380]
  PIN a_d[381]
    DIRECTION OUTPUT ;
    USE SIGNAL ;
    PORT
      LAYER M5 ;
        RECT 25.296 86.208 25.320 86.400 ;
    END
  END a_d[381]
  PIN a_d[382]
    DIRECTION OUTPUT ;
    USE SIGNAL ;
    PORT
      LAYER M3 ;
        RECT 25.341 86.208 25.365 86.400 ;
    END
  END a_d[382]
  PIN a_d[383]
    DIRECTION OUTPUT ;
    USE SIGNAL ;
    PORT
      LAYER M5 ;
        RECT 25.392 86.208 25.416 86.400 ;
    END
  END a_d[383]
  PIN a_d[384]
    DIRECTION OUTPUT ;
    USE SIGNAL ;
    PORT
      LAYER M3 ;
        RECT 25.485 86.208 25.509 86.400 ;
    END
  END a_d[384]
  PIN a_d[385]
    DIRECTION OUTPUT ;
    USE SIGNAL ;
    PORT
      LAYER M5 ;
        RECT 25.536 86.208 25.560 86.400 ;
    END
  END a_d[385]
  PIN a_d[386]
    DIRECTION OUTPUT ;
    USE SIGNAL ;
    PORT
      LAYER M3 ;
        RECT 25.593 86.208 25.617 86.400 ;
    END
  END a_d[386]
  PIN a_d[387]
    DIRECTION OUTPUT ;
    USE SIGNAL ;
    PORT
      LAYER M5 ;
        RECT 25.680 86.208 25.704 86.400 ;
    END
  END a_d[387]
  PIN a_d[388]
    DIRECTION OUTPUT ;
    USE SIGNAL ;
    PORT
      LAYER M3 ;
        RECT 25.737 86.208 25.761 86.400 ;
    END
  END a_d[388]
  PIN a_d[389]
    DIRECTION OUTPUT ;
    USE SIGNAL ;
    PORT
      LAYER M5 ;
        RECT 25.824 86.208 25.848 86.400 ;
    END
  END a_d[389]
  PIN a_d[390]
    DIRECTION OUTPUT ;
    USE SIGNAL ;
    PORT
      LAYER M3 ;
        RECT 25.881 86.208 25.905 86.400 ;
    END
  END a_d[390]
  PIN a_d[391]
    DIRECTION OUTPUT ;
    USE SIGNAL ;
    PORT
      LAYER M5 ;
        RECT 25.920 86.208 25.944 86.400 ;
    END
  END a_d[391]
  PIN a_d[392]
    DIRECTION OUTPUT ;
    USE SIGNAL ;
    PORT
      LAYER M3 ;
        RECT 25.989 86.208 26.013 86.400 ;
    END
  END a_d[392]
  PIN a_d[393]
    DIRECTION OUTPUT ;
    USE SIGNAL ;
    PORT
      LAYER M5 ;
        RECT 26.064 86.208 26.088 86.400 ;
    END
  END a_d[393]
  PIN a_d[394]
    DIRECTION OUTPUT ;
    USE SIGNAL ;
    PORT
      LAYER M3 ;
        RECT 26.133 86.208 26.157 86.400 ;
    END
  END a_d[394]
  PIN a_d[395]
    DIRECTION OUTPUT ;
    USE SIGNAL ;
    PORT
      LAYER M5 ;
        RECT 26.208 86.208 26.232 86.400 ;
    END
  END a_d[395]
  PIN a_d[396]
    DIRECTION OUTPUT ;
    USE SIGNAL ;
    PORT
      LAYER M3 ;
        RECT 26.241 86.208 26.265 86.400 ;
    END
  END a_d[396]
  PIN a_d[397]
    DIRECTION OUTPUT ;
    USE SIGNAL ;
    PORT
      LAYER M5 ;
        RECT 26.304 86.208 26.328 86.400 ;
    END
  END a_d[397]
  PIN a_d[398]
    DIRECTION OUTPUT ;
    USE SIGNAL ;
    PORT
      LAYER M3 ;
        RECT 26.385 86.208 26.409 86.400 ;
    END
  END a_d[398]
  PIN a_d[399]
    DIRECTION OUTPUT ;
    USE SIGNAL ;
    PORT
      LAYER M5 ;
        RECT 26.448 86.208 26.472 86.400 ;
    END
  END a_d[399]
  PIN a_d[400]
    DIRECTION OUTPUT ;
    USE SIGNAL ;
    PORT
      LAYER M3 ;
        RECT 26.529 86.208 26.553 86.400 ;
    END
  END a_d[400]
  PIN a_d[401]
    DIRECTION OUTPUT ;
    USE SIGNAL ;
    PORT
      LAYER M5 ;
        RECT 26.592 86.208 26.616 86.400 ;
    END
  END a_d[401]
  PIN a_d[402]
    DIRECTION OUTPUT ;
    USE SIGNAL ;
    PORT
      LAYER M3 ;
        RECT 26.637 86.208 26.661 86.400 ;
    END
  END a_d[402]
  PIN a_d[403]
    DIRECTION OUTPUT ;
    USE SIGNAL ;
    PORT
      LAYER M5 ;
        RECT 26.688 86.208 26.712 86.400 ;
    END
  END a_d[403]
  PIN a_d[404]
    DIRECTION OUTPUT ;
    USE SIGNAL ;
    PORT
      LAYER M3 ;
        RECT 26.781 86.208 26.805 86.400 ;
    END
  END a_d[404]
  PIN a_d[405]
    DIRECTION OUTPUT ;
    USE SIGNAL ;
    PORT
      LAYER M5 ;
        RECT 26.832 86.208 26.856 86.400 ;
    END
  END a_d[405]
  PIN a_d[406]
    DIRECTION OUTPUT ;
    USE SIGNAL ;
    PORT
      LAYER M3 ;
        RECT 26.889 86.208 26.913 86.400 ;
    END
  END a_d[406]
  PIN a_d[407]
    DIRECTION OUTPUT ;
    USE SIGNAL ;
    PORT
      LAYER M5 ;
        RECT 26.976 86.208 27.000 86.400 ;
    END
  END a_d[407]
  PIN a_d[408]
    DIRECTION OUTPUT ;
    USE SIGNAL ;
    PORT
      LAYER M3 ;
        RECT 27.033 86.208 27.057 86.400 ;
    END
  END a_d[408]
  PIN a_d[409]
    DIRECTION OUTPUT ;
    USE SIGNAL ;
    PORT
      LAYER M5 ;
        RECT 27.120 86.208 27.144 86.400 ;
    END
  END a_d[409]
  PIN a_d[410]
    DIRECTION OUTPUT ;
    USE SIGNAL ;
    PORT
      LAYER M3 ;
        RECT 27.177 86.208 27.201 86.400 ;
    END
  END a_d[410]
  PIN a_d[411]
    DIRECTION OUTPUT ;
    USE SIGNAL ;
    PORT
      LAYER M5 ;
        RECT 27.216 86.208 27.240 86.400 ;
    END
  END a_d[411]
  PIN a_d[412]
    DIRECTION OUTPUT ;
    USE SIGNAL ;
    PORT
      LAYER M3 ;
        RECT 27.285 86.208 27.309 86.400 ;
    END
  END a_d[412]
  PIN a_d[413]
    DIRECTION OUTPUT ;
    USE SIGNAL ;
    PORT
      LAYER M5 ;
        RECT 27.360 86.208 27.384 86.400 ;
    END
  END a_d[413]
  PIN a_d[414]
    DIRECTION OUTPUT ;
    USE SIGNAL ;
    PORT
      LAYER M3 ;
        RECT 27.429 86.208 27.453 86.400 ;
    END
  END a_d[414]
  PIN a_d[415]
    DIRECTION OUTPUT ;
    USE SIGNAL ;
    PORT
      LAYER M5 ;
        RECT 27.504 86.208 27.528 86.400 ;
    END
  END a_d[415]
  PIN a_d[416]
    DIRECTION OUTPUT ;
    USE SIGNAL ;
    PORT
      LAYER M3 ;
        RECT 27.537 86.208 27.561 86.400 ;
    END
  END a_d[416]
  PIN a_d[417]
    DIRECTION OUTPUT ;
    USE SIGNAL ;
    PORT
      LAYER M5 ;
        RECT 27.600 86.208 27.624 86.400 ;
    END
  END a_d[417]
  PIN a_d[418]
    DIRECTION OUTPUT ;
    USE SIGNAL ;
    PORT
      LAYER M3 ;
        RECT 27.681 86.208 27.705 86.400 ;
    END
  END a_d[418]
  PIN a_d[419]
    DIRECTION OUTPUT ;
    USE SIGNAL ;
    PORT
      LAYER M5 ;
        RECT 27.744 86.208 27.768 86.400 ;
    END
  END a_d[419]
  PIN a_d[420]
    DIRECTION OUTPUT ;
    USE SIGNAL ;
    PORT
      LAYER M3 ;
        RECT 27.825 86.208 27.849 86.400 ;
    END
  END a_d[420]
  PIN a_d[421]
    DIRECTION OUTPUT ;
    USE SIGNAL ;
    PORT
      LAYER M5 ;
        RECT 27.888 86.208 27.912 86.400 ;
    END
  END a_d[421]
  PIN a_d[422]
    DIRECTION OUTPUT ;
    USE SIGNAL ;
    PORT
      LAYER M3 ;
        RECT 27.933 86.208 27.957 86.400 ;
    END
  END a_d[422]
  PIN a_d[423]
    DIRECTION OUTPUT ;
    USE SIGNAL ;
    PORT
      LAYER M5 ;
        RECT 27.984 86.208 28.008 86.400 ;
    END
  END a_d[423]
  PIN a_d[424]
    DIRECTION OUTPUT ;
    USE SIGNAL ;
    PORT
      LAYER M3 ;
        RECT 28.077 86.208 28.101 86.400 ;
    END
  END a_d[424]
  PIN a_d[425]
    DIRECTION OUTPUT ;
    USE SIGNAL ;
    PORT
      LAYER M5 ;
        RECT 28.128 86.208 28.152 86.400 ;
    END
  END a_d[425]
  PIN a_d[426]
    DIRECTION OUTPUT ;
    USE SIGNAL ;
    PORT
      LAYER M3 ;
        RECT 28.185 86.208 28.209 86.400 ;
    END
  END a_d[426]
  PIN a_d[427]
    DIRECTION OUTPUT ;
    USE SIGNAL ;
    PORT
      LAYER M5 ;
        RECT 28.272 86.208 28.296 86.400 ;
    END
  END a_d[427]
  PIN a_d[428]
    DIRECTION OUTPUT ;
    USE SIGNAL ;
    PORT
      LAYER M3 ;
        RECT 28.329 86.208 28.353 86.400 ;
    END
  END a_d[428]
  PIN a_d[429]
    DIRECTION OUTPUT ;
    USE SIGNAL ;
    PORT
      LAYER M5 ;
        RECT 28.416 86.208 28.440 86.400 ;
    END
  END a_d[429]
  PIN a_d[430]
    DIRECTION OUTPUT ;
    USE SIGNAL ;
    PORT
      LAYER M3 ;
        RECT 28.473 86.208 28.497 86.400 ;
    END
  END a_d[430]
  PIN a_d[431]
    DIRECTION OUTPUT ;
    USE SIGNAL ;
    PORT
      LAYER M5 ;
        RECT 28.512 86.208 28.536 86.400 ;
    END
  END a_d[431]
  PIN a_d[432]
    DIRECTION OUTPUT ;
    USE SIGNAL ;
    PORT
      LAYER M3 ;
        RECT 28.581 86.208 28.605 86.400 ;
    END
  END a_d[432]
  PIN a_d[433]
    DIRECTION OUTPUT ;
    USE SIGNAL ;
    PORT
      LAYER M5 ;
        RECT 28.656 86.208 28.680 86.400 ;
    END
  END a_d[433]
  PIN a_d[434]
    DIRECTION OUTPUT ;
    USE SIGNAL ;
    PORT
      LAYER M3 ;
        RECT 28.725 86.208 28.749 86.400 ;
    END
  END a_d[434]
  PIN a_d[435]
    DIRECTION OUTPUT ;
    USE SIGNAL ;
    PORT
      LAYER M5 ;
        RECT 28.800 86.208 28.824 86.400 ;
    END
  END a_d[435]
  PIN a_d[436]
    DIRECTION OUTPUT ;
    USE SIGNAL ;
    PORT
      LAYER M3 ;
        RECT 28.833 86.208 28.857 86.400 ;
    END
  END a_d[436]
  PIN a_d[437]
    DIRECTION OUTPUT ;
    USE SIGNAL ;
    PORT
      LAYER M5 ;
        RECT 28.896 86.208 28.920 86.400 ;
    END
  END a_d[437]
  PIN a_d[438]
    DIRECTION OUTPUT ;
    USE SIGNAL ;
    PORT
      LAYER M3 ;
        RECT 28.977 86.208 29.001 86.400 ;
    END
  END a_d[438]
  PIN a_d[439]
    DIRECTION OUTPUT ;
    USE SIGNAL ;
    PORT
      LAYER M5 ;
        RECT 29.040 86.208 29.064 86.400 ;
    END
  END a_d[439]
  PIN a_d[440]
    DIRECTION OUTPUT ;
    USE SIGNAL ;
    PORT
      LAYER M3 ;
        RECT 29.121 86.208 29.145 86.400 ;
    END
  END a_d[440]
  PIN a_d[441]
    DIRECTION OUTPUT ;
    USE SIGNAL ;
    PORT
      LAYER M5 ;
        RECT 29.184 86.208 29.208 86.400 ;
    END
  END a_d[441]
  PIN a_d[442]
    DIRECTION OUTPUT ;
    USE SIGNAL ;
    PORT
      LAYER M3 ;
        RECT 29.229 86.208 29.253 86.400 ;
    END
  END a_d[442]
  PIN a_d[443]
    DIRECTION OUTPUT ;
    USE SIGNAL ;
    PORT
      LAYER M5 ;
        RECT 29.280 86.208 29.304 86.400 ;
    END
  END a_d[443]
  PIN a_d[444]
    DIRECTION OUTPUT ;
    USE SIGNAL ;
    PORT
      LAYER M3 ;
        RECT 29.373 86.208 29.397 86.400 ;
    END
  END a_d[444]
  PIN a_d[445]
    DIRECTION OUTPUT ;
    USE SIGNAL ;
    PORT
      LAYER M5 ;
        RECT 29.424 86.208 29.448 86.400 ;
    END
  END a_d[445]
  PIN a_d[446]
    DIRECTION OUTPUT ;
    USE SIGNAL ;
    PORT
      LAYER M3 ;
        RECT 29.481 86.208 29.505 86.400 ;
    END
  END a_d[446]
  PIN a_d[447]
    DIRECTION OUTPUT ;
    USE SIGNAL ;
    PORT
      LAYER M5 ;
        RECT 29.568 86.208 29.592 86.400 ;
    END
  END a_d[447]
  PIN a_d[448]
    DIRECTION OUTPUT ;
    USE SIGNAL ;
    PORT
      LAYER M3 ;
        RECT 29.625 86.208 29.649 86.400 ;
    END
  END a_d[448]
  PIN a_d[449]
    DIRECTION OUTPUT ;
    USE SIGNAL ;
    PORT
      LAYER M5 ;
        RECT 29.712 86.208 29.736 86.400 ;
    END
  END a_d[449]
  PIN a_d[450]
    DIRECTION OUTPUT ;
    USE SIGNAL ;
    PORT
      LAYER M3 ;
        RECT 29.769 86.208 29.793 86.400 ;
    END
  END a_d[450]
  PIN a_d[451]
    DIRECTION OUTPUT ;
    USE SIGNAL ;
    PORT
      LAYER M5 ;
        RECT 29.808 86.208 29.832 86.400 ;
    END
  END a_d[451]
  PIN a_d[452]
    DIRECTION OUTPUT ;
    USE SIGNAL ;
    PORT
      LAYER M3 ;
        RECT 29.877 86.208 29.901 86.400 ;
    END
  END a_d[452]
  PIN a_d[453]
    DIRECTION OUTPUT ;
    USE SIGNAL ;
    PORT
      LAYER M5 ;
        RECT 29.952 86.208 29.976 86.400 ;
    END
  END a_d[453]
  PIN a_d[454]
    DIRECTION OUTPUT ;
    USE SIGNAL ;
    PORT
      LAYER M3 ;
        RECT 30.021 86.208 30.045 86.400 ;
    END
  END a_d[454]
  PIN a_d[455]
    DIRECTION OUTPUT ;
    USE SIGNAL ;
    PORT
      LAYER M5 ;
        RECT 30.096 86.208 30.120 86.400 ;
    END
  END a_d[455]
  PIN a_d[456]
    DIRECTION OUTPUT ;
    USE SIGNAL ;
    PORT
      LAYER M3 ;
        RECT 30.165 86.208 30.189 86.400 ;
    END
  END a_d[456]
  PIN a_d[457]
    DIRECTION OUTPUT ;
    USE SIGNAL ;
    PORT
      LAYER M5 ;
        RECT 30.192 86.208 30.216 86.400 ;
    END
  END a_d[457]
  PIN a_d[458]
    DIRECTION OUTPUT ;
    USE SIGNAL ;
    PORT
      LAYER M3 ;
        RECT 30.273 86.208 30.297 86.400 ;
    END
  END a_d[458]
  PIN a_d[459]
    DIRECTION OUTPUT ;
    USE SIGNAL ;
    PORT
      LAYER M5 ;
        RECT 30.336 86.208 30.360 86.400 ;
    END
  END a_d[459]
  PIN a_d[460]
    DIRECTION OUTPUT ;
    USE SIGNAL ;
    PORT
      LAYER M3 ;
        RECT 30.417 86.208 30.441 86.400 ;
    END
  END a_d[460]
  PIN a_d[461]
    DIRECTION OUTPUT ;
    USE SIGNAL ;
    PORT
      LAYER M5 ;
        RECT 30.480 86.208 30.504 86.400 ;
    END
  END a_d[461]
  PIN a_d[462]
    DIRECTION OUTPUT ;
    USE SIGNAL ;
    PORT
      LAYER M3 ;
        RECT 30.525 86.208 30.549 86.400 ;
    END
  END a_d[462]
  PIN a_d[463]
    DIRECTION OUTPUT ;
    USE SIGNAL ;
    PORT
      LAYER M5 ;
        RECT 30.624 86.208 30.648 86.400 ;
    END
  END a_d[463]
  PIN a_d[464]
    DIRECTION OUTPUT ;
    USE SIGNAL ;
    PORT
      LAYER M3 ;
        RECT 30.669 86.208 30.693 86.400 ;
    END
  END a_d[464]
  PIN a_d[465]
    DIRECTION OUTPUT ;
    USE SIGNAL ;
    PORT
      LAYER M5 ;
        RECT 30.720 86.208 30.744 86.400 ;
    END
  END a_d[465]
  PIN a_d[466]
    DIRECTION OUTPUT ;
    USE SIGNAL ;
    PORT
      LAYER M3 ;
        RECT 30.813 86.208 30.837 86.400 ;
    END
  END a_d[466]
  PIN a_d[467]
    DIRECTION OUTPUT ;
    USE SIGNAL ;
    PORT
      LAYER M5 ;
        RECT 30.864 86.208 30.888 86.400 ;
    END
  END a_d[467]
  PIN a_d[468]
    DIRECTION OUTPUT ;
    USE SIGNAL ;
    PORT
      LAYER M3 ;
        RECT 30.921 86.208 30.945 86.400 ;
    END
  END a_d[468]
  PIN a_d[469]
    DIRECTION OUTPUT ;
    USE SIGNAL ;
    PORT
      LAYER M5 ;
        RECT 31.008 86.208 31.032 86.400 ;
    END
  END a_d[469]
  PIN a_d[470]
    DIRECTION OUTPUT ;
    USE SIGNAL ;
    PORT
      LAYER M3 ;
        RECT 31.065 86.208 31.089 86.400 ;
    END
  END a_d[470]
  PIN a_d[471]
    DIRECTION OUTPUT ;
    USE SIGNAL ;
    PORT
      LAYER M5 ;
        RECT 31.104 86.208 31.128 86.400 ;
    END
  END a_d[471]
  PIN a_d[472]
    DIRECTION OUTPUT ;
    USE SIGNAL ;
    PORT
      LAYER M3 ;
        RECT 31.173 86.208 31.197 86.400 ;
    END
  END a_d[472]
  PIN a_d[473]
    DIRECTION OUTPUT ;
    USE SIGNAL ;
    PORT
      LAYER M5 ;
        RECT 31.248 86.208 31.272 86.400 ;
    END
  END a_d[473]
  PIN a_d[474]
    DIRECTION OUTPUT ;
    USE SIGNAL ;
    PORT
      LAYER M3 ;
        RECT 31.317 86.208 31.341 86.400 ;
    END
  END a_d[474]
  PIN a_d[475]
    DIRECTION OUTPUT ;
    USE SIGNAL ;
    PORT
      LAYER M5 ;
        RECT 31.392 86.208 31.416 86.400 ;
    END
  END a_d[475]
  PIN a_d[476]
    DIRECTION OUTPUT ;
    USE SIGNAL ;
    PORT
      LAYER M3 ;
        RECT 31.461 86.208 31.485 86.400 ;
    END
  END a_d[476]
  PIN a_d[477]
    DIRECTION OUTPUT ;
    USE SIGNAL ;
    PORT
      LAYER M5 ;
        RECT 31.488 86.208 31.512 86.400 ;
    END
  END a_d[477]
  PIN a_d[478]
    DIRECTION OUTPUT ;
    USE SIGNAL ;
    PORT
      LAYER M3 ;
        RECT 31.569 86.208 31.593 86.400 ;
    END
  END a_d[478]
  PIN a_d[479]
    DIRECTION OUTPUT ;
    USE SIGNAL ;
    PORT
      LAYER M5 ;
        RECT 31.632 86.208 31.656 86.400 ;
    END
  END a_d[479]
  PIN a_d[480]
    DIRECTION OUTPUT ;
    USE SIGNAL ;
    PORT
      LAYER M3 ;
        RECT 31.713 86.208 31.737 86.400 ;
    END
  END a_d[480]
  PIN a_d[481]
    DIRECTION OUTPUT ;
    USE SIGNAL ;
    PORT
      LAYER M5 ;
        RECT 31.776 86.208 31.800 86.400 ;
    END
  END a_d[481]
  PIN a_d[482]
    DIRECTION OUTPUT ;
    USE SIGNAL ;
    PORT
      LAYER M3 ;
        RECT 31.821 86.208 31.845 86.400 ;
    END
  END a_d[482]
  PIN a_d[483]
    DIRECTION OUTPUT ;
    USE SIGNAL ;
    PORT
      LAYER M5 ;
        RECT 31.920 86.208 31.944 86.400 ;
    END
  END a_d[483]
  PIN a_d[484]
    DIRECTION OUTPUT ;
    USE SIGNAL ;
    PORT
      LAYER M3 ;
        RECT 31.965 86.208 31.989 86.400 ;
    END
  END a_d[484]
  PIN a_d[485]
    DIRECTION OUTPUT ;
    USE SIGNAL ;
    PORT
      LAYER M5 ;
        RECT 32.016 86.208 32.040 86.400 ;
    END
  END a_d[485]
  PIN a_d[486]
    DIRECTION OUTPUT ;
    USE SIGNAL ;
    PORT
      LAYER M3 ;
        RECT 32.109 86.208 32.133 86.400 ;
    END
  END a_d[486]
  PIN a_d[487]
    DIRECTION OUTPUT ;
    USE SIGNAL ;
    PORT
      LAYER M5 ;
        RECT 32.160 86.208 32.184 86.400 ;
    END
  END a_d[487]
  PIN a_d[488]
    DIRECTION OUTPUT ;
    USE SIGNAL ;
    PORT
      LAYER M3 ;
        RECT 32.217 86.208 32.241 86.400 ;
    END
  END a_d[488]
  PIN a_d[489]
    DIRECTION OUTPUT ;
    USE SIGNAL ;
    PORT
      LAYER M5 ;
        RECT 32.304 86.208 32.328 86.400 ;
    END
  END a_d[489]
  PIN a_d[490]
    DIRECTION OUTPUT ;
    USE SIGNAL ;
    PORT
      LAYER M3 ;
        RECT 32.361 86.208 32.385 86.400 ;
    END
  END a_d[490]
  PIN a_d[491]
    DIRECTION OUTPUT ;
    USE SIGNAL ;
    PORT
      LAYER M5 ;
        RECT 32.400 86.208 32.424 86.400 ;
    END
  END a_d[491]
  PIN a_d[492]
    DIRECTION OUTPUT ;
    USE SIGNAL ;
    PORT
      LAYER M3 ;
        RECT 32.469 86.208 32.493 86.400 ;
    END
  END a_d[492]
  PIN a_d[493]
    DIRECTION OUTPUT ;
    USE SIGNAL ;
    PORT
      LAYER M5 ;
        RECT 32.544 86.208 32.568 86.400 ;
    END
  END a_d[493]
  PIN a_d[494]
    DIRECTION OUTPUT ;
    USE SIGNAL ;
    PORT
      LAYER M3 ;
        RECT 32.613 86.208 32.637 86.400 ;
    END
  END a_d[494]
  PIN a_d[495]
    DIRECTION OUTPUT ;
    USE SIGNAL ;
    PORT
      LAYER M5 ;
        RECT 32.688 86.208 32.712 86.400 ;
    END
  END a_d[495]
  PIN a_d[496]
    DIRECTION OUTPUT ;
    USE SIGNAL ;
    PORT
      LAYER M3 ;
        RECT 32.757 86.208 32.781 86.400 ;
    END
  END a_d[496]
  PIN a_d[497]
    DIRECTION OUTPUT ;
    USE SIGNAL ;
    PORT
      LAYER M5 ;
        RECT 32.784 86.208 32.808 86.400 ;
    END
  END a_d[497]
  PIN a_d[498]
    DIRECTION OUTPUT ;
    USE SIGNAL ;
    PORT
      LAYER M3 ;
        RECT 32.865 86.208 32.889 86.400 ;
    END
  END a_d[498]
  PIN a_d[499]
    DIRECTION OUTPUT ;
    USE SIGNAL ;
    PORT
      LAYER M5 ;
        RECT 32.928 86.208 32.952 86.400 ;
    END
  END a_d[499]
  PIN a_d[500]
    DIRECTION OUTPUT ;
    USE SIGNAL ;
    PORT
      LAYER M3 ;
        RECT 33.009 86.208 33.033 86.400 ;
    END
  END a_d[500]
  PIN a_d[501]
    DIRECTION OUTPUT ;
    USE SIGNAL ;
    PORT
      LAYER M5 ;
        RECT 33.072 86.208 33.096 86.400 ;
    END
  END a_d[501]
  PIN a_d[502]
    DIRECTION OUTPUT ;
    USE SIGNAL ;
    PORT
      LAYER M3 ;
        RECT 33.117 86.208 33.141 86.400 ;
    END
  END a_d[502]
  PIN a_d[503]
    DIRECTION OUTPUT ;
    USE SIGNAL ;
    PORT
      LAYER M5 ;
        RECT 33.216 86.208 33.240 86.400 ;
    END
  END a_d[503]
  PIN a_d[504]
    DIRECTION OUTPUT ;
    USE SIGNAL ;
    PORT
      LAYER M3 ;
        RECT 33.261 86.208 33.285 86.400 ;
    END
  END a_d[504]
  PIN a_d[505]
    DIRECTION OUTPUT ;
    USE SIGNAL ;
    PORT
      LAYER M5 ;
        RECT 33.312 86.208 33.336 86.400 ;
    END
  END a_d[505]
  PIN a_d[506]
    DIRECTION OUTPUT ;
    USE SIGNAL ;
    PORT
      LAYER M3 ;
        RECT 33.405 86.208 33.429 86.400 ;
    END
  END a_d[506]
  PIN a_d[507]
    DIRECTION OUTPUT ;
    USE SIGNAL ;
    PORT
      LAYER M5 ;
        RECT 33.456 86.208 33.480 86.400 ;
    END
  END a_d[507]
  PIN a_d[508]
    DIRECTION OUTPUT ;
    USE SIGNAL ;
    PORT
      LAYER M3 ;
        RECT 33.513 86.208 33.537 86.400 ;
    END
  END a_d[508]
  PIN a_d[509]
    DIRECTION OUTPUT ;
    USE SIGNAL ;
    PORT
      LAYER M5 ;
        RECT 33.600 86.208 33.624 86.400 ;
    END
  END a_d[509]
  PIN a_d[510]
    DIRECTION OUTPUT ;
    USE SIGNAL ;
    PORT
      LAYER M3 ;
        RECT 33.657 86.208 33.681 86.400 ;
    END
  END a_d[510]
  PIN a_d[511]
    DIRECTION OUTPUT ;
    USE SIGNAL ;
    PORT
      LAYER M5 ;
        RECT 33.696 86.208 33.720 86.400 ;
    END
  END a_d[511]
  PIN a_d[512]
    DIRECTION OUTPUT ;
    USE SIGNAL ;
    PORT
      LAYER M3 ;
        RECT 33.765 86.208 33.789 86.400 ;
    END
  END a_d[512]
  PIN a_d[513]
    DIRECTION OUTPUT ;
    USE SIGNAL ;
    PORT
      LAYER M5 ;
        RECT 33.840 86.208 33.864 86.400 ;
    END
  END a_d[513]
  PIN a_d[514]
    DIRECTION OUTPUT ;
    USE SIGNAL ;
    PORT
      LAYER M3 ;
        RECT 33.909 86.208 33.933 86.400 ;
    END
  END a_d[514]
  PIN a_d[515]
    DIRECTION OUTPUT ;
    USE SIGNAL ;
    PORT
      LAYER M5 ;
        RECT 33.984 86.208 34.008 86.400 ;
    END
  END a_d[515]
  PIN tap_d[0]
    DIRECTION OUTPUT ;
    USE SIGNAL ;
    PORT
      LAYER M4 ;
        RECT 0.000 22.512 0.192 22.536 ;
    END
  END tap_d[0]
  PIN tap_d[1]
    DIRECTION OUTPUT ;
    USE SIGNAL ;
    PORT
      LAYER M4 ;
        RECT 0.000 22.608 0.192 22.632 ;
    END
  END tap_d[1]
  PIN tap_d[2]
    DIRECTION OUTPUT ;
    USE SIGNAL ;
    PORT
      LAYER M4 ;
        RECT 0.000 22.704 0.192 22.728 ;
    END
  END tap_d[2]
  PIN tap_d[3]
    DIRECTION OUTPUT ;
    USE SIGNAL ;
    PORT
      LAYER M4 ;
        RECT 0.000 22.800 0.192 22.824 ;
    END
  END tap_d[3]
  PIN tap_d[4]
    DIRECTION OUTPUT ;
    USE SIGNAL ;
    PORT
      LAYER M4 ;
        RECT 0.000 22.896 0.192 22.920 ;
    END
  END tap_d[4]
  PIN tap_d[5]
    DIRECTION OUTPUT ;
    USE SIGNAL ;
    PORT
      LAYER M4 ;
        RECT 0.000 22.992 0.192 23.016 ;
    END
  END tap_d[5]
  PIN tap_d[6]
    DIRECTION OUTPUT ;
    USE SIGNAL ;
    PORT
      LAYER M4 ;
        RECT 0.000 23.088 0.192 23.112 ;
    END
  END tap_d[6]
  PIN tap_d[7]
    DIRECTION OUTPUT ;
    USE SIGNAL ;
    PORT
      LAYER M4 ;
        RECT 0.000 23.184 0.192 23.208 ;
    END
  END tap_d[7]
  PIN tap_d[8]
    DIRECTION OUTPUT ;
    USE SIGNAL ;
    PORT
      LAYER M4 ;
        RECT 0.000 23.280 0.192 23.304 ;
    END
  END tap_d[8]
  PIN tap_d[9]
    DIRECTION OUTPUT ;
    USE SIGNAL ;
    PORT
      LAYER M4 ;
        RECT 0.000 23.376 0.192 23.400 ;
    END
  END tap_d[9]
  PIN tap_d[10]
    DIRECTION OUTPUT ;
    USE SIGNAL ;
    PORT
      LAYER M4 ;
        RECT 0.000 23.472 0.192 23.496 ;
    END
  END tap_d[10]
  PIN tap_d[11]
    DIRECTION OUTPUT ;
    USE SIGNAL ;
    PORT
      LAYER M4 ;
        RECT 0.000 23.568 0.192 23.592 ;
    END
  END tap_d[11]
  PIN tap_d[12]
    DIRECTION OUTPUT ;
    USE SIGNAL ;
    PORT
      LAYER M4 ;
        RECT 0.000 23.664 0.192 23.688 ;
    END
  END tap_d[12]
  PIN tap_d[13]
    DIRECTION OUTPUT ;
    USE SIGNAL ;
    PORT
      LAYER M4 ;
        RECT 0.000 23.760 0.192 23.784 ;
    END
  END tap_d[13]
  PIN tap_d[14]
    DIRECTION OUTPUT ;
    USE SIGNAL ;
    PORT
      LAYER M4 ;
        RECT 0.000 23.856 0.192 23.880 ;
    END
  END tap_d[14]
  PIN tap_d[15]
    DIRECTION OUTPUT ;
    USE SIGNAL ;
    PORT
      LAYER M4 ;
        RECT 0.000 23.952 0.192 23.976 ;
    END
  END tap_d[15]
  PIN tap_d[16]
    DIRECTION OUTPUT ;
    USE SIGNAL ;
    PORT
      LAYER M4 ;
        RECT 0.000 24.048 0.192 24.072 ;
    END
  END tap_d[16]
  PIN tap_d[17]
    DIRECTION OUTPUT ;
    USE SIGNAL ;
    PORT
      LAYER M4 ;
        RECT 0.000 24.144 0.192 24.168 ;
    END
  END tap_d[17]
  PIN tap_d[18]
    DIRECTION OUTPUT ;
    USE SIGNAL ;
    PORT
      LAYER M4 ;
        RECT 0.000 24.240 0.192 24.264 ;
    END
  END tap_d[18]
  PIN tap_d[19]
    DIRECTION OUTPUT ;
    USE SIGNAL ;
    PORT
      LAYER M4 ;
        RECT 0.000 24.336 0.192 24.360 ;
    END
  END tap_d[19]
  PIN tap_d[20]
    DIRECTION OUTPUT ;
    USE SIGNAL ;
    PORT
      LAYER M4 ;
        RECT 0.000 24.432 0.192 24.456 ;
    END
  END tap_d[20]
  PIN tap_d[21]
    DIRECTION OUTPUT ;
    USE SIGNAL ;
    PORT
      LAYER M4 ;
        RECT 0.000 24.528 0.192 24.552 ;
    END
  END tap_d[21]
  PIN tap_d[22]
    DIRECTION OUTPUT ;
    USE SIGNAL ;
    PORT
      LAYER M4 ;
        RECT 0.000 24.624 0.192 24.648 ;
    END
  END tap_d[22]
  PIN tap_d[23]
    DIRECTION OUTPUT ;
    USE SIGNAL ;
    PORT
      LAYER M4 ;
        RECT 0.000 24.720 0.192 24.744 ;
    END
  END tap_d[23]
  PIN tap_d[24]
    DIRECTION OUTPUT ;
    USE SIGNAL ;
    PORT
      LAYER M4 ;
        RECT 0.000 24.816 0.192 24.840 ;
    END
  END tap_d[24]
  PIN tap_d[25]
    DIRECTION OUTPUT ;
    USE SIGNAL ;
    PORT
      LAYER M4 ;
        RECT 0.000 24.912 0.192 24.936 ;
    END
  END tap_d[25]
  PIN tap_d[26]
    DIRECTION OUTPUT ;
    USE SIGNAL ;
    PORT
      LAYER M4 ;
        RECT 0.000 25.008 0.192 25.032 ;
    END
  END tap_d[26]
  PIN tap_d[27]
    DIRECTION OUTPUT ;
    USE SIGNAL ;
    PORT
      LAYER M4 ;
        RECT 0.000 25.104 0.192 25.128 ;
    END
  END tap_d[27]
  PIN tap_d[28]
    DIRECTION OUTPUT ;
    USE SIGNAL ;
    PORT
      LAYER M4 ;
        RECT 0.000 25.200 0.192 25.224 ;
    END
  END tap_d[28]
  PIN tap_d[29]
    DIRECTION OUTPUT ;
    USE SIGNAL ;
    PORT
      LAYER M4 ;
        RECT 0.000 25.296 0.192 25.320 ;
    END
  END tap_d[29]
  PIN tap_d[30]
    DIRECTION OUTPUT ;
    USE SIGNAL ;
    PORT
      LAYER M4 ;
        RECT 0.000 25.392 0.192 25.416 ;
    END
  END tap_d[30]
  PIN tap_d[31]
    DIRECTION OUTPUT ;
    USE SIGNAL ;
    PORT
      LAYER M4 ;
        RECT 0.000 25.488 0.192 25.512 ;
    END
  END tap_d[31]
  PIN tap_d[32]
    DIRECTION OUTPUT ;
    USE SIGNAL ;
    PORT
      LAYER M4 ;
        RECT 0.000 25.584 0.192 25.608 ;
    END
  END tap_d[32]
  PIN tap_d[33]
    DIRECTION OUTPUT ;
    USE SIGNAL ;
    PORT
      LAYER M4 ;
        RECT 0.000 25.680 0.192 25.704 ;
    END
  END tap_d[33]
  PIN tap_d[34]
    DIRECTION OUTPUT ;
    USE SIGNAL ;
    PORT
      LAYER M4 ;
        RECT 0.000 25.776 0.192 25.800 ;
    END
  END tap_d[34]
  PIN tap_d[35]
    DIRECTION OUTPUT ;
    USE SIGNAL ;
    PORT
      LAYER M4 ;
        RECT 0.000 25.872 0.192 25.896 ;
    END
  END tap_d[35]
  PIN tap_d[36]
    DIRECTION OUTPUT ;
    USE SIGNAL ;
    PORT
      LAYER M4 ;
        RECT 0.000 25.968 0.192 25.992 ;
    END
  END tap_d[36]
  PIN tap_d[37]
    DIRECTION OUTPUT ;
    USE SIGNAL ;
    PORT
      LAYER M4 ;
        RECT 0.000 26.064 0.192 26.088 ;
    END
  END tap_d[37]
  PIN tap_d[38]
    DIRECTION OUTPUT ;
    USE SIGNAL ;
    PORT
      LAYER M4 ;
        RECT 0.000 26.160 0.192 26.184 ;
    END
  END tap_d[38]
  PIN tap_d[39]
    DIRECTION OUTPUT ;
    USE SIGNAL ;
    PORT
      LAYER M4 ;
        RECT 0.000 26.256 0.192 26.280 ;
    END
  END tap_d[39]
  PIN tap_d[40]
    DIRECTION OUTPUT ;
    USE SIGNAL ;
    PORT
      LAYER M4 ;
        RECT 0.000 26.352 0.192 26.376 ;
    END
  END tap_d[40]
  PIN tap_d[41]
    DIRECTION OUTPUT ;
    USE SIGNAL ;
    PORT
      LAYER M4 ;
        RECT 0.000 26.448 0.192 26.472 ;
    END
  END tap_d[41]
  PIN tap_d[42]
    DIRECTION OUTPUT ;
    USE SIGNAL ;
    PORT
      LAYER M4 ;
        RECT 0.000 26.544 0.192 26.568 ;
    END
  END tap_d[42]
  PIN tap_d[43]
    DIRECTION OUTPUT ;
    USE SIGNAL ;
    PORT
      LAYER M4 ;
        RECT 0.000 26.640 0.192 26.664 ;
    END
  END tap_d[43]
  PIN tap_d[44]
    DIRECTION OUTPUT ;
    USE SIGNAL ;
    PORT
      LAYER M4 ;
        RECT 0.000 26.736 0.192 26.760 ;
    END
  END tap_d[44]
  PIN tap_d[45]
    DIRECTION OUTPUT ;
    USE SIGNAL ;
    PORT
      LAYER M4 ;
        RECT 0.000 26.832 0.192 26.856 ;
    END
  END tap_d[45]
  PIN tap_d[46]
    DIRECTION OUTPUT ;
    USE SIGNAL ;
    PORT
      LAYER M4 ;
        RECT 0.000 26.928 0.192 26.952 ;
    END
  END tap_d[46]
  PIN tap_d[47]
    DIRECTION OUTPUT ;
    USE SIGNAL ;
    PORT
      LAYER M4 ;
        RECT 0.000 27.024 0.192 27.048 ;
    END
  END tap_d[47]
  PIN tap_d[48]
    DIRECTION OUTPUT ;
    USE SIGNAL ;
    PORT
      LAYER M4 ;
        RECT 0.000 27.120 0.192 27.144 ;
    END
  END tap_d[48]
  PIN tap_d[49]
    DIRECTION OUTPUT ;
    USE SIGNAL ;
    PORT
      LAYER M4 ;
        RECT 0.000 27.216 0.192 27.240 ;
    END
  END tap_d[49]
  PIN tap_d[50]
    DIRECTION OUTPUT ;
    USE SIGNAL ;
    PORT
      LAYER M4 ;
        RECT 0.000 27.312 0.192 27.336 ;
    END
  END tap_d[50]
  PIN tap_d[51]
    DIRECTION OUTPUT ;
    USE SIGNAL ;
    PORT
      LAYER M4 ;
        RECT 0.000 27.408 0.192 27.432 ;
    END
  END tap_d[51]
  PIN tap_d[52]
    DIRECTION OUTPUT ;
    USE SIGNAL ;
    PORT
      LAYER M4 ;
        RECT 0.000 27.504 0.192 27.528 ;
    END
  END tap_d[52]
  PIN tap_d[53]
    DIRECTION OUTPUT ;
    USE SIGNAL ;
    PORT
      LAYER M4 ;
        RECT 0.000 27.600 0.192 27.624 ;
    END
  END tap_d[53]
  PIN tap_d[54]
    DIRECTION OUTPUT ;
    USE SIGNAL ;
    PORT
      LAYER M4 ;
        RECT 0.000 27.696 0.192 27.720 ;
    END
  END tap_d[54]
  PIN tap_d[55]
    DIRECTION OUTPUT ;
    USE SIGNAL ;
    PORT
      LAYER M4 ;
        RECT 0.000 27.792 0.192 27.816 ;
    END
  END tap_d[55]
  PIN tap_d[56]
    DIRECTION OUTPUT ;
    USE SIGNAL ;
    PORT
      LAYER M4 ;
        RECT 0.000 27.888 0.192 27.912 ;
    END
  END tap_d[56]
  PIN tap_d[57]
    DIRECTION OUTPUT ;
    USE SIGNAL ;
    PORT
      LAYER M4 ;
        RECT 0.000 27.984 0.192 28.008 ;
    END
  END tap_d[57]
  PIN tap_d[58]
    DIRECTION OUTPUT ;
    USE SIGNAL ;
    PORT
      LAYER M4 ;
        RECT 0.000 28.080 0.192 28.104 ;
    END
  END tap_d[58]
  PIN tap_d[59]
    DIRECTION OUTPUT ;
    USE SIGNAL ;
    PORT
      LAYER M4 ;
        RECT 0.000 28.176 0.192 28.200 ;
    END
  END tap_d[59]
  PIN tap_d[60]
    DIRECTION OUTPUT ;
    USE SIGNAL ;
    PORT
      LAYER M4 ;
        RECT 0.000 28.272 0.192 28.296 ;
    END
  END tap_d[60]
  PIN tap_d[61]
    DIRECTION OUTPUT ;
    USE SIGNAL ;
    PORT
      LAYER M4 ;
        RECT 0.000 28.368 0.192 28.392 ;
    END
  END tap_d[61]
  PIN tap_d[62]
    DIRECTION OUTPUT ;
    USE SIGNAL ;
    PORT
      LAYER M4 ;
        RECT 0.000 28.464 0.192 28.488 ;
    END
  END tap_d[62]
  PIN tap_d[63]
    DIRECTION OUTPUT ;
    USE SIGNAL ;
    PORT
      LAYER M4 ;
        RECT 0.000 28.512 0.192 28.536 ;
    END
  END tap_d[63]
  PIN tap_d[64]
    DIRECTION OUTPUT ;
    USE SIGNAL ;
    PORT
      LAYER M4 ;
        RECT 0.000 28.608 0.192 28.632 ;
    END
  END tap_d[64]
  PIN tap_d[65]
    DIRECTION OUTPUT ;
    USE SIGNAL ;
    PORT
      LAYER M4 ;
        RECT 0.000 28.704 0.192 28.728 ;
    END
  END tap_d[65]
  PIN tap_d[66]
    DIRECTION OUTPUT ;
    USE SIGNAL ;
    PORT
      LAYER M4 ;
        RECT 0.000 28.800 0.192 28.824 ;
    END
  END tap_d[66]
  PIN tap_d[67]
    DIRECTION OUTPUT ;
    USE SIGNAL ;
    PORT
      LAYER M4 ;
        RECT 0.000 28.896 0.192 28.920 ;
    END
  END tap_d[67]
  PIN tap_d[68]
    DIRECTION OUTPUT ;
    USE SIGNAL ;
    PORT
      LAYER M4 ;
        RECT 0.000 28.992 0.192 29.016 ;
    END
  END tap_d[68]
  PIN tap_d[69]
    DIRECTION OUTPUT ;
    USE SIGNAL ;
    PORT
      LAYER M4 ;
        RECT 0.000 29.088 0.192 29.112 ;
    END
  END tap_d[69]
  PIN tap_d[70]
    DIRECTION OUTPUT ;
    USE SIGNAL ;
    PORT
      LAYER M4 ;
        RECT 0.000 29.184 0.192 29.208 ;
    END
  END tap_d[70]
  PIN tap_d[71]
    DIRECTION OUTPUT ;
    USE SIGNAL ;
    PORT
      LAYER M4 ;
        RECT 0.000 29.280 0.192 29.304 ;
    END
  END tap_d[71]
  PIN tap_d[72]
    DIRECTION OUTPUT ;
    USE SIGNAL ;
    PORT
      LAYER M4 ;
        RECT 0.000 29.376 0.192 29.400 ;
    END
  END tap_d[72]
  PIN tap_d[73]
    DIRECTION OUTPUT ;
    USE SIGNAL ;
    PORT
      LAYER M4 ;
        RECT 0.000 29.472 0.192 29.496 ;
    END
  END tap_d[73]
  PIN tap_d[74]
    DIRECTION OUTPUT ;
    USE SIGNAL ;
    PORT
      LAYER M4 ;
        RECT 0.000 29.568 0.192 29.592 ;
    END
  END tap_d[74]
  PIN tap_d[75]
    DIRECTION OUTPUT ;
    USE SIGNAL ;
    PORT
      LAYER M4 ;
        RECT 0.000 29.664 0.192 29.688 ;
    END
  END tap_d[75]
  PIN tap_d[76]
    DIRECTION OUTPUT ;
    USE SIGNAL ;
    PORT
      LAYER M4 ;
        RECT 0.000 29.760 0.192 29.784 ;
    END
  END tap_d[76]
  PIN tap_d[77]
    DIRECTION OUTPUT ;
    USE SIGNAL ;
    PORT
      LAYER M4 ;
        RECT 0.000 29.856 0.192 29.880 ;
    END
  END tap_d[77]
  PIN tap_d[78]
    DIRECTION OUTPUT ;
    USE SIGNAL ;
    PORT
      LAYER M4 ;
        RECT 0.000 29.952 0.192 29.976 ;
    END
  END tap_d[78]
  PIN tap_d[79]
    DIRECTION OUTPUT ;
    USE SIGNAL ;
    PORT
      LAYER M4 ;
        RECT 0.000 30.048 0.192 30.072 ;
    END
  END tap_d[79]
  PIN tap_d[80]
    DIRECTION OUTPUT ;
    USE SIGNAL ;
    PORT
      LAYER M4 ;
        RECT 0.000 30.144 0.192 30.168 ;
    END
  END tap_d[80]
  PIN tap_d[81]
    DIRECTION OUTPUT ;
    USE SIGNAL ;
    PORT
      LAYER M4 ;
        RECT 0.000 30.240 0.192 30.264 ;
    END
  END tap_d[81]
  PIN tap_d[82]
    DIRECTION OUTPUT ;
    USE SIGNAL ;
    PORT
      LAYER M4 ;
        RECT 0.000 30.336 0.192 30.360 ;
    END
  END tap_d[82]
  PIN tap_d[83]
    DIRECTION OUTPUT ;
    USE SIGNAL ;
    PORT
      LAYER M4 ;
        RECT 0.000 30.432 0.192 30.456 ;
    END
  END tap_d[83]
  PIN tap_d[84]
    DIRECTION OUTPUT ;
    USE SIGNAL ;
    PORT
      LAYER M4 ;
        RECT 0.000 30.528 0.192 30.552 ;
    END
  END tap_d[84]
  PIN tap_d[85]
    DIRECTION OUTPUT ;
    USE SIGNAL ;
    PORT
      LAYER M4 ;
        RECT 0.000 30.624 0.192 30.648 ;
    END
  END tap_d[85]
  PIN tap_d[86]
    DIRECTION OUTPUT ;
    USE SIGNAL ;
    PORT
      LAYER M4 ;
        RECT 0.000 30.720 0.192 30.744 ;
    END
  END tap_d[86]
  PIN tap_d[87]
    DIRECTION OUTPUT ;
    USE SIGNAL ;
    PORT
      LAYER M4 ;
        RECT 0.000 30.816 0.192 30.840 ;
    END
  END tap_d[87]
  PIN tap_d[88]
    DIRECTION OUTPUT ;
    USE SIGNAL ;
    PORT
      LAYER M4 ;
        RECT 0.000 30.912 0.192 30.936 ;
    END
  END tap_d[88]
  PIN tap_d[89]
    DIRECTION OUTPUT ;
    USE SIGNAL ;
    PORT
      LAYER M4 ;
        RECT 0.000 31.008 0.192 31.032 ;
    END
  END tap_d[89]
  PIN tap_d[90]
    DIRECTION OUTPUT ;
    USE SIGNAL ;
    PORT
      LAYER M4 ;
        RECT 0.000 31.104 0.192 31.128 ;
    END
  END tap_d[90]
  PIN tap_d[91]
    DIRECTION OUTPUT ;
    USE SIGNAL ;
    PORT
      LAYER M4 ;
        RECT 0.000 31.200 0.192 31.224 ;
    END
  END tap_d[91]
  PIN tap_d[92]
    DIRECTION OUTPUT ;
    USE SIGNAL ;
    PORT
      LAYER M4 ;
        RECT 0.000 31.296 0.192 31.320 ;
    END
  END tap_d[92]
  PIN tap_d[93]
    DIRECTION OUTPUT ;
    USE SIGNAL ;
    PORT
      LAYER M4 ;
        RECT 0.000 31.392 0.192 31.416 ;
    END
  END tap_d[93]
  PIN tap_d[94]
    DIRECTION OUTPUT ;
    USE SIGNAL ;
    PORT
      LAYER M4 ;
        RECT 0.000 31.488 0.192 31.512 ;
    END
  END tap_d[94]
  PIN tap_d[95]
    DIRECTION OUTPUT ;
    USE SIGNAL ;
    PORT
      LAYER M4 ;
        RECT 0.000 31.584 0.192 31.608 ;
    END
  END tap_d[95]
  PIN tap_d[96]
    DIRECTION OUTPUT ;
    USE SIGNAL ;
    PORT
      LAYER M4 ;
        RECT 0.000 31.680 0.192 31.704 ;
    END
  END tap_d[96]
  PIN tap_d[97]
    DIRECTION OUTPUT ;
    USE SIGNAL ;
    PORT
      LAYER M4 ;
        RECT 0.000 31.776 0.192 31.800 ;
    END
  END tap_d[97]
  PIN tap_d[98]
    DIRECTION OUTPUT ;
    USE SIGNAL ;
    PORT
      LAYER M4 ;
        RECT 0.000 31.872 0.192 31.896 ;
    END
  END tap_d[98]
  PIN tap_d[99]
    DIRECTION OUTPUT ;
    USE SIGNAL ;
    PORT
      LAYER M4 ;
        RECT 0.000 31.968 0.192 31.992 ;
    END
  END tap_d[99]
  PIN tap_d[100]
    DIRECTION OUTPUT ;
    USE SIGNAL ;
    PORT
      LAYER M4 ;
        RECT 0.000 32.064 0.192 32.088 ;
    END
  END tap_d[100]
  PIN tap_d[101]
    DIRECTION OUTPUT ;
    USE SIGNAL ;
    PORT
      LAYER M4 ;
        RECT 0.000 32.160 0.192 32.184 ;
    END
  END tap_d[101]
  PIN tap_d[102]
    DIRECTION OUTPUT ;
    USE SIGNAL ;
    PORT
      LAYER M4 ;
        RECT 0.000 32.256 0.192 32.280 ;
    END
  END tap_d[102]
  PIN tap_d[103]
    DIRECTION OUTPUT ;
    USE SIGNAL ;
    PORT
      LAYER M4 ;
        RECT 0.000 32.352 0.192 32.376 ;
    END
  END tap_d[103]
  PIN tap_d[104]
    DIRECTION OUTPUT ;
    USE SIGNAL ;
    PORT
      LAYER M4 ;
        RECT 0.000 32.448 0.192 32.472 ;
    END
  END tap_d[104]
  PIN tap_d[105]
    DIRECTION OUTPUT ;
    USE SIGNAL ;
    PORT
      LAYER M4 ;
        RECT 0.000 32.544 0.192 32.568 ;
    END
  END tap_d[105]
  PIN tap_d[106]
    DIRECTION OUTPUT ;
    USE SIGNAL ;
    PORT
      LAYER M4 ;
        RECT 0.000 32.640 0.192 32.664 ;
    END
  END tap_d[106]
  PIN tap_d[107]
    DIRECTION OUTPUT ;
    USE SIGNAL ;
    PORT
      LAYER M4 ;
        RECT 0.000 32.736 0.192 32.760 ;
    END
  END tap_d[107]
  PIN tap_d[108]
    DIRECTION OUTPUT ;
    USE SIGNAL ;
    PORT
      LAYER M4 ;
        RECT 0.000 32.832 0.192 32.856 ;
    END
  END tap_d[108]
  PIN tap_d[109]
    DIRECTION OUTPUT ;
    USE SIGNAL ;
    PORT
      LAYER M4 ;
        RECT 0.000 32.928 0.192 32.952 ;
    END
  END tap_d[109]
  PIN tap_d[110]
    DIRECTION OUTPUT ;
    USE SIGNAL ;
    PORT
      LAYER M4 ;
        RECT 0.000 33.024 0.192 33.048 ;
    END
  END tap_d[110]
  PIN tap_d[111]
    DIRECTION OUTPUT ;
    USE SIGNAL ;
    PORT
      LAYER M4 ;
        RECT 0.000 33.120 0.192 33.144 ;
    END
  END tap_d[111]
  PIN tap_d[112]
    DIRECTION OUTPUT ;
    USE SIGNAL ;
    PORT
      LAYER M4 ;
        RECT 0.000 33.216 0.192 33.240 ;
    END
  END tap_d[112]
  PIN tap_d[113]
    DIRECTION OUTPUT ;
    USE SIGNAL ;
    PORT
      LAYER M4 ;
        RECT 0.000 33.312 0.192 33.336 ;
    END
  END tap_d[113]
  PIN tap_d[114]
    DIRECTION OUTPUT ;
    USE SIGNAL ;
    PORT
      LAYER M4 ;
        RECT 0.000 33.408 0.192 33.432 ;
    END
  END tap_d[114]
  PIN tap_d[115]
    DIRECTION OUTPUT ;
    USE SIGNAL ;
    PORT
      LAYER M4 ;
        RECT 0.000 33.504 0.192 33.528 ;
    END
  END tap_d[115]
  PIN tap_d[116]
    DIRECTION OUTPUT ;
    USE SIGNAL ;
    PORT
      LAYER M4 ;
        RECT 0.000 33.600 0.192 33.624 ;
    END
  END tap_d[116]
  PIN tap_d[117]
    DIRECTION OUTPUT ;
    USE SIGNAL ;
    PORT
      LAYER M4 ;
        RECT 0.000 33.696 0.192 33.720 ;
    END
  END tap_d[117]
  PIN tap_d[118]
    DIRECTION OUTPUT ;
    USE SIGNAL ;
    PORT
      LAYER M4 ;
        RECT 0.000 33.792 0.192 33.816 ;
    END
  END tap_d[118]
  PIN tap_d[119]
    DIRECTION OUTPUT ;
    USE SIGNAL ;
    PORT
      LAYER M4 ;
        RECT 0.000 33.888 0.192 33.912 ;
    END
  END tap_d[119]
  PIN tap_d[120]
    DIRECTION OUTPUT ;
    USE SIGNAL ;
    PORT
      LAYER M4 ;
        RECT 0.000 33.984 0.192 34.008 ;
    END
  END tap_d[120]
  PIN tap_d[121]
    DIRECTION OUTPUT ;
    USE SIGNAL ;
    PORT
      LAYER M4 ;
        RECT 0.000 34.080 0.192 34.104 ;
    END
  END tap_d[121]
  PIN tap_d[122]
    DIRECTION OUTPUT ;
    USE SIGNAL ;
    PORT
      LAYER M4 ;
        RECT 0.000 34.176 0.192 34.200 ;
    END
  END tap_d[122]
  PIN tap_d[123]
    DIRECTION OUTPUT ;
    USE SIGNAL ;
    PORT
      LAYER M4 ;
        RECT 0.000 34.272 0.192 34.296 ;
    END
  END tap_d[123]
  PIN tap_d[124]
    DIRECTION OUTPUT ;
    USE SIGNAL ;
    PORT
      LAYER M4 ;
        RECT 0.000 34.368 0.192 34.392 ;
    END
  END tap_d[124]
  PIN tap_d[125]
    DIRECTION OUTPUT ;
    USE SIGNAL ;
    PORT
      LAYER M4 ;
        RECT 0.000 34.464 0.192 34.488 ;
    END
  END tap_d[125]
  PIN tap_d[126]
    DIRECTION OUTPUT ;
    USE SIGNAL ;
    PORT
      LAYER M4 ;
        RECT 0.000 34.560 0.192 34.584 ;
    END
  END tap_d[126]
  PIN tap_d[127]
    DIRECTION OUTPUT ;
    USE SIGNAL ;
    PORT
      LAYER M4 ;
        RECT 0.000 34.656 0.192 34.680 ;
    END
  END tap_d[127]
  PIN tap_d[128]
    DIRECTION OUTPUT ;
    USE SIGNAL ;
    PORT
      LAYER M4 ;
        RECT 0.000 34.752 0.192 34.776 ;
    END
  END tap_d[128]
  PIN tap_d[129]
    DIRECTION OUTPUT ;
    USE SIGNAL ;
    PORT
      LAYER M4 ;
        RECT 0.000 34.848 0.192 34.872 ;
    END
  END tap_d[129]
  PIN tap_d[130]
    DIRECTION OUTPUT ;
    USE SIGNAL ;
    PORT
      LAYER M4 ;
        RECT 0.000 34.944 0.192 34.968 ;
    END
  END tap_d[130]
  PIN tap_d[131]
    DIRECTION OUTPUT ;
    USE SIGNAL ;
    PORT
      LAYER M4 ;
        RECT 0.000 35.040 0.192 35.064 ;
    END
  END tap_d[131]
  PIN tap_d[132]
    DIRECTION OUTPUT ;
    USE SIGNAL ;
    PORT
      LAYER M4 ;
        RECT 0.000 35.136 0.192 35.160 ;
    END
  END tap_d[132]
  PIN tap_d[133]
    DIRECTION OUTPUT ;
    USE SIGNAL ;
    PORT
      LAYER M4 ;
        RECT 0.000 35.232 0.192 35.256 ;
    END
  END tap_d[133]
  PIN tap_d[134]
    DIRECTION OUTPUT ;
    USE SIGNAL ;
    PORT
      LAYER M4 ;
        RECT 0.000 35.328 0.192 35.352 ;
    END
  END tap_d[134]
  PIN tap_d[135]
    DIRECTION OUTPUT ;
    USE SIGNAL ;
    PORT
      LAYER M4 ;
        RECT 0.000 35.424 0.192 35.448 ;
    END
  END tap_d[135]
  PIN tap_d[136]
    DIRECTION OUTPUT ;
    USE SIGNAL ;
    PORT
      LAYER M4 ;
        RECT 0.000 35.520 0.192 35.544 ;
    END
  END tap_d[136]
  PIN tap_d[137]
    DIRECTION OUTPUT ;
    USE SIGNAL ;
    PORT
      LAYER M4 ;
        RECT 0.000 35.616 0.192 35.640 ;
    END
  END tap_d[137]
  PIN tap_d[138]
    DIRECTION OUTPUT ;
    USE SIGNAL ;
    PORT
      LAYER M4 ;
        RECT 0.000 35.712 0.192 35.736 ;
    END
  END tap_d[138]
  PIN tap_d[139]
    DIRECTION OUTPUT ;
    USE SIGNAL ;
    PORT
      LAYER M4 ;
        RECT 0.000 35.808 0.192 35.832 ;
    END
  END tap_d[139]
  PIN tap_d[140]
    DIRECTION OUTPUT ;
    USE SIGNAL ;
    PORT
      LAYER M4 ;
        RECT 0.000 35.904 0.192 35.928 ;
    END
  END tap_d[140]
  PIN tap_d[141]
    DIRECTION OUTPUT ;
    USE SIGNAL ;
    PORT
      LAYER M4 ;
        RECT 0.000 36.000 0.192 36.024 ;
    END
  END tap_d[141]
  PIN tap_d[142]
    DIRECTION OUTPUT ;
    USE SIGNAL ;
    PORT
      LAYER M4 ;
        RECT 0.000 36.096 0.192 36.120 ;
    END
  END tap_d[142]
  PIN tap_d[143]
    DIRECTION OUTPUT ;
    USE SIGNAL ;
    PORT
      LAYER M4 ;
        RECT 0.000 36.192 0.192 36.216 ;
    END
  END tap_d[143]
  PIN tap_d[144]
    DIRECTION OUTPUT ;
    USE SIGNAL ;
    PORT
      LAYER M4 ;
        RECT 0.000 36.288 0.192 36.312 ;
    END
  END tap_d[144]
  PIN tap_d[145]
    DIRECTION OUTPUT ;
    USE SIGNAL ;
    PORT
      LAYER M4 ;
        RECT 0.000 36.384 0.192 36.408 ;
    END
  END tap_d[145]
  PIN tap_d[146]
    DIRECTION OUTPUT ;
    USE SIGNAL ;
    PORT
      LAYER M4 ;
        RECT 0.000 36.480 0.192 36.504 ;
    END
  END tap_d[146]
  PIN tap_d[147]
    DIRECTION OUTPUT ;
    USE SIGNAL ;
    PORT
      LAYER M4 ;
        RECT 0.000 36.576 0.192 36.600 ;
    END
  END tap_d[147]
  PIN tap_d[148]
    DIRECTION OUTPUT ;
    USE SIGNAL ;
    PORT
      LAYER M4 ;
        RECT 0.000 36.672 0.192 36.696 ;
    END
  END tap_d[148]
  PIN tap_d[149]
    DIRECTION OUTPUT ;
    USE SIGNAL ;
    PORT
      LAYER M4 ;
        RECT 0.000 36.768 0.192 36.792 ;
    END
  END tap_d[149]
  PIN tap_d[150]
    DIRECTION OUTPUT ;
    USE SIGNAL ;
    PORT
      LAYER M4 ;
        RECT 0.000 36.864 0.192 36.888 ;
    END
  END tap_d[150]
  PIN tap_d[151]
    DIRECTION OUTPUT ;
    USE SIGNAL ;
    PORT
      LAYER M4 ;
        RECT 0.000 36.960 0.192 36.984 ;
    END
  END tap_d[151]
  PIN tap_d[152]
    DIRECTION OUTPUT ;
    USE SIGNAL ;
    PORT
      LAYER M4 ;
        RECT 0.000 37.056 0.192 37.080 ;
    END
  END tap_d[152]
  PIN tap_d[153]
    DIRECTION OUTPUT ;
    USE SIGNAL ;
    PORT
      LAYER M4 ;
        RECT 0.000 37.152 0.192 37.176 ;
    END
  END tap_d[153]
  PIN tap_d[154]
    DIRECTION OUTPUT ;
    USE SIGNAL ;
    PORT
      LAYER M4 ;
        RECT 0.000 37.248 0.192 37.272 ;
    END
  END tap_d[154]
  PIN tap_d[155]
    DIRECTION OUTPUT ;
    USE SIGNAL ;
    PORT
      LAYER M4 ;
        RECT 0.000 37.344 0.192 37.368 ;
    END
  END tap_d[155]
  PIN tap_d[156]
    DIRECTION OUTPUT ;
    USE SIGNAL ;
    PORT
      LAYER M4 ;
        RECT 0.000 37.440 0.192 37.464 ;
    END
  END tap_d[156]
  PIN tap_d[157]
    DIRECTION OUTPUT ;
    USE SIGNAL ;
    PORT
      LAYER M4 ;
        RECT 0.000 37.536 0.192 37.560 ;
    END
  END tap_d[157]
  PIN tap_d[158]
    DIRECTION OUTPUT ;
    USE SIGNAL ;
    PORT
      LAYER M4 ;
        RECT 0.000 37.632 0.192 37.656 ;
    END
  END tap_d[158]
  PIN tap_d[159]
    DIRECTION OUTPUT ;
    USE SIGNAL ;
    PORT
      LAYER M4 ;
        RECT 0.000 37.728 0.192 37.752 ;
    END
  END tap_d[159]
  PIN tap_d[160]
    DIRECTION OUTPUT ;
    USE SIGNAL ;
    PORT
      LAYER M4 ;
        RECT 0.000 37.824 0.192 37.848 ;
    END
  END tap_d[160]
  PIN tap_d[161]
    DIRECTION OUTPUT ;
    USE SIGNAL ;
    PORT
      LAYER M4 ;
        RECT 0.000 37.920 0.192 37.944 ;
    END
  END tap_d[161]
  PIN tap_d[162]
    DIRECTION OUTPUT ;
    USE SIGNAL ;
    PORT
      LAYER M4 ;
        RECT 0.000 38.016 0.192 38.040 ;
    END
  END tap_d[162]
  PIN tap_d[163]
    DIRECTION OUTPUT ;
    USE SIGNAL ;
    PORT
      LAYER M4 ;
        RECT 0.000 38.112 0.192 38.136 ;
    END
  END tap_d[163]
  PIN tap_d[164]
    DIRECTION OUTPUT ;
    USE SIGNAL ;
    PORT
      LAYER M4 ;
        RECT 0.000 38.208 0.192 38.232 ;
    END
  END tap_d[164]
  PIN tap_d[165]
    DIRECTION OUTPUT ;
    USE SIGNAL ;
    PORT
      LAYER M4 ;
        RECT 0.000 38.304 0.192 38.328 ;
    END
  END tap_d[165]
  PIN tap_d[166]
    DIRECTION OUTPUT ;
    USE SIGNAL ;
    PORT
      LAYER M4 ;
        RECT 0.000 38.400 0.192 38.424 ;
    END
  END tap_d[166]
  PIN tap_d[167]
    DIRECTION OUTPUT ;
    USE SIGNAL ;
    PORT
      LAYER M4 ;
        RECT 0.000 38.496 0.192 38.520 ;
    END
  END tap_d[167]
  PIN tap_d[168]
    DIRECTION OUTPUT ;
    USE SIGNAL ;
    PORT
      LAYER M4 ;
        RECT 0.000 38.592 0.192 38.616 ;
    END
  END tap_d[168]
  PIN tap_d[169]
    DIRECTION OUTPUT ;
    USE SIGNAL ;
    PORT
      LAYER M4 ;
        RECT 0.000 38.688 0.192 38.712 ;
    END
  END tap_d[169]
  PIN tap_d[170]
    DIRECTION OUTPUT ;
    USE SIGNAL ;
    PORT
      LAYER M4 ;
        RECT 0.000 38.784 0.192 38.808 ;
    END
  END tap_d[170]
  PIN tap_d[171]
    DIRECTION OUTPUT ;
    USE SIGNAL ;
    PORT
      LAYER M4 ;
        RECT 0.000 38.880 0.192 38.904 ;
    END
  END tap_d[171]
  PIN tap_d[172]
    DIRECTION OUTPUT ;
    USE SIGNAL ;
    PORT
      LAYER M4 ;
        RECT 0.000 38.976 0.192 39.000 ;
    END
  END tap_d[172]
  PIN tap_d[173]
    DIRECTION OUTPUT ;
    USE SIGNAL ;
    PORT
      LAYER M4 ;
        RECT 0.000 39.072 0.192 39.096 ;
    END
  END tap_d[173]
  PIN tap_d[174]
    DIRECTION OUTPUT ;
    USE SIGNAL ;
    PORT
      LAYER M4 ;
        RECT 0.000 39.168 0.192 39.192 ;
    END
  END tap_d[174]
  PIN tap_d[175]
    DIRECTION OUTPUT ;
    USE SIGNAL ;
    PORT
      LAYER M4 ;
        RECT 0.000 39.264 0.192 39.288 ;
    END
  END tap_d[175]
  PIN tap_d[176]
    DIRECTION OUTPUT ;
    USE SIGNAL ;
    PORT
      LAYER M4 ;
        RECT 0.000 39.360 0.192 39.384 ;
    END
  END tap_d[176]
  PIN tap_d[177]
    DIRECTION OUTPUT ;
    USE SIGNAL ;
    PORT
      LAYER M4 ;
        RECT 0.000 39.456 0.192 39.480 ;
    END
  END tap_d[177]
  PIN tap_d[178]
    DIRECTION OUTPUT ;
    USE SIGNAL ;
    PORT
      LAYER M4 ;
        RECT 0.000 39.552 0.192 39.576 ;
    END
  END tap_d[178]
  PIN tap_d[179]
    DIRECTION OUTPUT ;
    USE SIGNAL ;
    PORT
      LAYER M4 ;
        RECT 0.000 39.648 0.192 39.672 ;
    END
  END tap_d[179]
  PIN tap_d[180]
    DIRECTION OUTPUT ;
    USE SIGNAL ;
    PORT
      LAYER M4 ;
        RECT 0.000 39.744 0.192 39.768 ;
    END
  END tap_d[180]
  PIN tap_d[181]
    DIRECTION OUTPUT ;
    USE SIGNAL ;
    PORT
      LAYER M4 ;
        RECT 0.000 39.840 0.192 39.864 ;
    END
  END tap_d[181]
  PIN tap_d[182]
    DIRECTION OUTPUT ;
    USE SIGNAL ;
    PORT
      LAYER M4 ;
        RECT 0.000 39.936 0.192 39.960 ;
    END
  END tap_d[182]
  PIN tap_d[183]
    DIRECTION OUTPUT ;
    USE SIGNAL ;
    PORT
      LAYER M4 ;
        RECT 0.000 40.032 0.192 40.056 ;
    END
  END tap_d[183]
  PIN tap_d[184]
    DIRECTION OUTPUT ;
    USE SIGNAL ;
    PORT
      LAYER M4 ;
        RECT 0.000 40.128 0.192 40.152 ;
    END
  END tap_d[184]
  PIN tap_d[185]
    DIRECTION OUTPUT ;
    USE SIGNAL ;
    PORT
      LAYER M4 ;
        RECT 0.000 40.224 0.192 40.248 ;
    END
  END tap_d[185]
  PIN tap_d[186]
    DIRECTION OUTPUT ;
    USE SIGNAL ;
    PORT
      LAYER M4 ;
        RECT 0.000 40.320 0.192 40.344 ;
    END
  END tap_d[186]
  PIN tap_d[187]
    DIRECTION OUTPUT ;
    USE SIGNAL ;
    PORT
      LAYER M4 ;
        RECT 0.000 40.416 0.192 40.440 ;
    END
  END tap_d[187]
  PIN tap_d[188]
    DIRECTION OUTPUT ;
    USE SIGNAL ;
    PORT
      LAYER M4 ;
        RECT 0.000 40.512 0.192 40.536 ;
    END
  END tap_d[188]
  PIN tap_d[189]
    DIRECTION OUTPUT ;
    USE SIGNAL ;
    PORT
      LAYER M4 ;
        RECT 0.000 40.608 0.192 40.632 ;
    END
  END tap_d[189]
  PIN tap_d[190]
    DIRECTION OUTPUT ;
    USE SIGNAL ;
    PORT
      LAYER M4 ;
        RECT 0.000 40.704 0.192 40.728 ;
    END
  END tap_d[190]
  PIN tap_d[191]
    DIRECTION OUTPUT ;
    USE SIGNAL ;
    PORT
      LAYER M4 ;
        RECT 0.000 40.800 0.192 40.824 ;
    END
  END tap_d[191]
  PIN tap_d[192]
    DIRECTION OUTPUT ;
    USE SIGNAL ;
    PORT
      LAYER M4 ;
        RECT 0.000 40.896 0.192 40.920 ;
    END
  END tap_d[192]
  PIN tap_d[193]
    DIRECTION OUTPUT ;
    USE SIGNAL ;
    PORT
      LAYER M4 ;
        RECT 0.000 40.992 0.192 41.016 ;
    END
  END tap_d[193]
  PIN tap_d[194]
    DIRECTION OUTPUT ;
    USE SIGNAL ;
    PORT
      LAYER M4 ;
        RECT 0.000 41.088 0.192 41.112 ;
    END
  END tap_d[194]
  PIN tap_d[195]
    DIRECTION OUTPUT ;
    USE SIGNAL ;
    PORT
      LAYER M4 ;
        RECT 0.000 41.184 0.192 41.208 ;
    END
  END tap_d[195]
  PIN tap_d[196]
    DIRECTION OUTPUT ;
    USE SIGNAL ;
    PORT
      LAYER M4 ;
        RECT 0.000 41.280 0.192 41.304 ;
    END
  END tap_d[196]
  PIN tap_d[197]
    DIRECTION OUTPUT ;
    USE SIGNAL ;
    PORT
      LAYER M4 ;
        RECT 0.000 41.376 0.192 41.400 ;
    END
  END tap_d[197]
  PIN tap_d[198]
    DIRECTION OUTPUT ;
    USE SIGNAL ;
    PORT
      LAYER M4 ;
        RECT 0.000 41.472 0.192 41.496 ;
    END
  END tap_d[198]
  PIN tap_d[199]
    DIRECTION OUTPUT ;
    USE SIGNAL ;
    PORT
      LAYER M4 ;
        RECT 0.000 41.568 0.192 41.592 ;
    END
  END tap_d[199]
  PIN tap_d[200]
    DIRECTION OUTPUT ;
    USE SIGNAL ;
    PORT
      LAYER M4 ;
        RECT 0.000 41.664 0.192 41.688 ;
    END
  END tap_d[200]
  PIN tap_d[201]
    DIRECTION OUTPUT ;
    USE SIGNAL ;
    PORT
      LAYER M4 ;
        RECT 0.000 41.760 0.192 41.784 ;
    END
  END tap_d[201]
  PIN tap_d[202]
    DIRECTION OUTPUT ;
    USE SIGNAL ;
    PORT
      LAYER M4 ;
        RECT 0.000 41.856 0.192 41.880 ;
    END
  END tap_d[202]
  PIN tap_d[203]
    DIRECTION OUTPUT ;
    USE SIGNAL ;
    PORT
      LAYER M4 ;
        RECT 0.000 41.952 0.192 41.976 ;
    END
  END tap_d[203]
  PIN tap_d[204]
    DIRECTION OUTPUT ;
    USE SIGNAL ;
    PORT
      LAYER M4 ;
        RECT 0.000 42.048 0.192 42.072 ;
    END
  END tap_d[204]
  PIN tap_d[205]
    DIRECTION OUTPUT ;
    USE SIGNAL ;
    PORT
      LAYER M4 ;
        RECT 0.000 42.144 0.192 42.168 ;
    END
  END tap_d[205]
  PIN tap_d[206]
    DIRECTION OUTPUT ;
    USE SIGNAL ;
    PORT
      LAYER M4 ;
        RECT 0.000 42.240 0.192 42.264 ;
    END
  END tap_d[206]
  PIN tap_d[207]
    DIRECTION OUTPUT ;
    USE SIGNAL ;
    PORT
      LAYER M4 ;
        RECT 0.000 42.336 0.192 42.360 ;
    END
  END tap_d[207]
  PIN tap_d[208]
    DIRECTION OUTPUT ;
    USE SIGNAL ;
    PORT
      LAYER M4 ;
        RECT 0.000 42.432 0.192 42.456 ;
    END
  END tap_d[208]
  PIN tap_d[209]
    DIRECTION OUTPUT ;
    USE SIGNAL ;
    PORT
      LAYER M4 ;
        RECT 0.000 42.528 0.192 42.552 ;
    END
  END tap_d[209]
  PIN tap_d[210]
    DIRECTION OUTPUT ;
    USE SIGNAL ;
    PORT
      LAYER M4 ;
        RECT 0.000 42.624 0.192 42.648 ;
    END
  END tap_d[210]
  PIN tap_d[211]
    DIRECTION OUTPUT ;
    USE SIGNAL ;
    PORT
      LAYER M4 ;
        RECT 0.000 42.720 0.192 42.744 ;
    END
  END tap_d[211]
  PIN tap_d[212]
    DIRECTION OUTPUT ;
    USE SIGNAL ;
    PORT
      LAYER M4 ;
        RECT 0.000 42.816 0.192 42.840 ;
    END
  END tap_d[212]
  PIN tap_d[213]
    DIRECTION OUTPUT ;
    USE SIGNAL ;
    PORT
      LAYER M4 ;
        RECT 0.000 42.912 0.192 42.936 ;
    END
  END tap_d[213]
  PIN tap_d[214]
    DIRECTION OUTPUT ;
    USE SIGNAL ;
    PORT
      LAYER M4 ;
        RECT 0.000 43.008 0.192 43.032 ;
    END
  END tap_d[214]
  PIN tap_d[215]
    DIRECTION OUTPUT ;
    USE SIGNAL ;
    PORT
      LAYER M4 ;
        RECT 0.000 43.104 0.192 43.128 ;
    END
  END tap_d[215]
  PIN tap_d[216]
    DIRECTION OUTPUT ;
    USE SIGNAL ;
    PORT
      LAYER M4 ;
        RECT 0.000 43.200 0.192 43.224 ;
    END
  END tap_d[216]
  PIN tap_d[217]
    DIRECTION OUTPUT ;
    USE SIGNAL ;
    PORT
      LAYER M4 ;
        RECT 0.000 43.296 0.192 43.320 ;
    END
  END tap_d[217]
  PIN tap_d[218]
    DIRECTION OUTPUT ;
    USE SIGNAL ;
    PORT
      LAYER M4 ;
        RECT 0.000 43.392 0.192 43.416 ;
    END
  END tap_d[218]
  PIN tap_d[219]
    DIRECTION OUTPUT ;
    USE SIGNAL ;
    PORT
      LAYER M4 ;
        RECT 0.000 43.488 0.192 43.512 ;
    END
  END tap_d[219]
  PIN tap_d[220]
    DIRECTION OUTPUT ;
    USE SIGNAL ;
    PORT
      LAYER M4 ;
        RECT 0.000 43.584 0.192 43.608 ;
    END
  END tap_d[220]
  PIN tap_d[221]
    DIRECTION OUTPUT ;
    USE SIGNAL ;
    PORT
      LAYER M4 ;
        RECT 0.000 43.680 0.192 43.704 ;
    END
  END tap_d[221]
  PIN tap_d[222]
    DIRECTION OUTPUT ;
    USE SIGNAL ;
    PORT
      LAYER M4 ;
        RECT 0.000 43.776 0.192 43.800 ;
    END
  END tap_d[222]
  PIN tap_d[223]
    DIRECTION OUTPUT ;
    USE SIGNAL ;
    PORT
      LAYER M4 ;
        RECT 0.000 43.872 0.192 43.896 ;
    END
  END tap_d[223]
  PIN tap_d[224]
    DIRECTION OUTPUT ;
    USE SIGNAL ;
    PORT
      LAYER M4 ;
        RECT 0.000 43.968 0.192 43.992 ;
    END
  END tap_d[224]
  PIN tap_d[225]
    DIRECTION OUTPUT ;
    USE SIGNAL ;
    PORT
      LAYER M4 ;
        RECT 0.000 44.064 0.192 44.088 ;
    END
  END tap_d[225]
  PIN tap_d[226]
    DIRECTION OUTPUT ;
    USE SIGNAL ;
    PORT
      LAYER M4 ;
        RECT 0.000 44.160 0.192 44.184 ;
    END
  END tap_d[226]
  PIN tap_d[227]
    DIRECTION OUTPUT ;
    USE SIGNAL ;
    PORT
      LAYER M4 ;
        RECT 0.000 44.256 0.192 44.280 ;
    END
  END tap_d[227]
  PIN tap_d[228]
    DIRECTION OUTPUT ;
    USE SIGNAL ;
    PORT
      LAYER M4 ;
        RECT 0.000 44.352 0.192 44.376 ;
    END
  END tap_d[228]
  PIN tap_d[229]
    DIRECTION OUTPUT ;
    USE SIGNAL ;
    PORT
      LAYER M4 ;
        RECT 0.000 44.448 0.192 44.472 ;
    END
  END tap_d[229]
  PIN tap_d[230]
    DIRECTION OUTPUT ;
    USE SIGNAL ;
    PORT
      LAYER M4 ;
        RECT 0.000 44.544 0.192 44.568 ;
    END
  END tap_d[230]
  PIN tap_d[231]
    DIRECTION OUTPUT ;
    USE SIGNAL ;
    PORT
      LAYER M4 ;
        RECT 0.000 44.640 0.192 44.664 ;
    END
  END tap_d[231]
  PIN tap_d[232]
    DIRECTION OUTPUT ;
    USE SIGNAL ;
    PORT
      LAYER M4 ;
        RECT 0.000 44.736 0.192 44.760 ;
    END
  END tap_d[232]
  PIN tap_d[233]
    DIRECTION OUTPUT ;
    USE SIGNAL ;
    PORT
      LAYER M4 ;
        RECT 0.000 44.832 0.192 44.856 ;
    END
  END tap_d[233]
  PIN tap_d[234]
    DIRECTION OUTPUT ;
    USE SIGNAL ;
    PORT
      LAYER M4 ;
        RECT 0.000 44.928 0.192 44.952 ;
    END
  END tap_d[234]
  PIN tap_d[235]
    DIRECTION OUTPUT ;
    USE SIGNAL ;
    PORT
      LAYER M4 ;
        RECT 0.000 45.024 0.192 45.048 ;
    END
  END tap_d[235]
  PIN tap_d[236]
    DIRECTION OUTPUT ;
    USE SIGNAL ;
    PORT
      LAYER M4 ;
        RECT 0.000 45.120 0.192 45.144 ;
    END
  END tap_d[236]
  PIN tap_d[237]
    DIRECTION OUTPUT ;
    USE SIGNAL ;
    PORT
      LAYER M4 ;
        RECT 0.000 45.216 0.192 45.240 ;
    END
  END tap_d[237]
  PIN tap_d[238]
    DIRECTION OUTPUT ;
    USE SIGNAL ;
    PORT
      LAYER M4 ;
        RECT 0.000 45.312 0.192 45.336 ;
    END
  END tap_d[238]
  PIN tap_d[239]
    DIRECTION OUTPUT ;
    USE SIGNAL ;
    PORT
      LAYER M4 ;
        RECT 0.000 45.408 0.192 45.432 ;
    END
  END tap_d[239]
  PIN tap_d[240]
    DIRECTION OUTPUT ;
    USE SIGNAL ;
    PORT
      LAYER M4 ;
        RECT 0.000 45.504 0.192 45.528 ;
    END
  END tap_d[240]
  PIN tap_d[241]
    DIRECTION OUTPUT ;
    USE SIGNAL ;
    PORT
      LAYER M4 ;
        RECT 0.000 45.600 0.192 45.624 ;
    END
  END tap_d[241]
  PIN tap_d[242]
    DIRECTION OUTPUT ;
    USE SIGNAL ;
    PORT
      LAYER M4 ;
        RECT 0.000 45.696 0.192 45.720 ;
    END
  END tap_d[242]
  PIN tap_d[243]
    DIRECTION OUTPUT ;
    USE SIGNAL ;
    PORT
      LAYER M4 ;
        RECT 0.000 45.792 0.192 45.816 ;
    END
  END tap_d[243]
  PIN tap_d[244]
    DIRECTION OUTPUT ;
    USE SIGNAL ;
    PORT
      LAYER M4 ;
        RECT 0.000 45.888 0.192 45.912 ;
    END
  END tap_d[244]
  PIN tap_d[245]
    DIRECTION OUTPUT ;
    USE SIGNAL ;
    PORT
      LAYER M4 ;
        RECT 0.000 45.984 0.192 46.008 ;
    END
  END tap_d[245]
  PIN tap_d[246]
    DIRECTION OUTPUT ;
    USE SIGNAL ;
    PORT
      LAYER M4 ;
        RECT 0.000 46.080 0.192 46.104 ;
    END
  END tap_d[246]
  PIN tap_d[247]
    DIRECTION OUTPUT ;
    USE SIGNAL ;
    PORT
      LAYER M4 ;
        RECT 0.000 46.176 0.192 46.200 ;
    END
  END tap_d[247]
  PIN tap_d[248]
    DIRECTION OUTPUT ;
    USE SIGNAL ;
    PORT
      LAYER M4 ;
        RECT 0.000 46.272 0.192 46.296 ;
    END
  END tap_d[248]
  PIN tap_d[249]
    DIRECTION OUTPUT ;
    USE SIGNAL ;
    PORT
      LAYER M4 ;
        RECT 0.000 46.368 0.192 46.392 ;
    END
  END tap_d[249]
  PIN tap_d[250]
    DIRECTION OUTPUT ;
    USE SIGNAL ;
    PORT
      LAYER M4 ;
        RECT 0.000 46.464 0.192 46.488 ;
    END
  END tap_d[250]
  PIN tap_d[251]
    DIRECTION OUTPUT ;
    USE SIGNAL ;
    PORT
      LAYER M4 ;
        RECT 0.000 46.560 0.192 46.584 ;
    END
  END tap_d[251]
  PIN tap_d[252]
    DIRECTION OUTPUT ;
    USE SIGNAL ;
    PORT
      LAYER M4 ;
        RECT 0.000 46.656 0.192 46.680 ;
    END
  END tap_d[252]
  PIN tap_d[253]
    DIRECTION OUTPUT ;
    USE SIGNAL ;
    PORT
      LAYER M4 ;
        RECT 0.000 46.752 0.192 46.776 ;
    END
  END tap_d[253]
  PIN tap_d[254]
    DIRECTION OUTPUT ;
    USE SIGNAL ;
    PORT
      LAYER M4 ;
        RECT 0.000 46.848 0.192 46.872 ;
    END
  END tap_d[254]
  PIN tap_d[255]
    DIRECTION OUTPUT ;
    USE SIGNAL ;
    PORT
      LAYER M4 ;
        RECT 0.000 46.944 0.192 46.968 ;
    END
  END tap_d[255]
  PIN tap_d[256]
    DIRECTION OUTPUT ;
    USE SIGNAL ;
    PORT
      LAYER M4 ;
        RECT 0.000 47.040 0.192 47.064 ;
    END
  END tap_d[256]
  PIN tap_d[257]
    DIRECTION OUTPUT ;
    USE SIGNAL ;
    PORT
      LAYER M4 ;
        RECT 0.000 47.136 0.192 47.160 ;
    END
  END tap_d[257]
  PIN tap_d[258]
    DIRECTION OUTPUT ;
    USE SIGNAL ;
    PORT
      LAYER M4 ;
        RECT 0.000 47.232 0.192 47.256 ;
    END
  END tap_d[258]
  PIN tap_d[259]
    DIRECTION OUTPUT ;
    USE SIGNAL ;
    PORT
      LAYER M4 ;
        RECT 0.000 47.328 0.192 47.352 ;
    END
  END tap_d[259]
  PIN tap_d[260]
    DIRECTION OUTPUT ;
    USE SIGNAL ;
    PORT
      LAYER M4 ;
        RECT 0.000 47.424 0.192 47.448 ;
    END
  END tap_d[260]
  PIN tap_d[261]
    DIRECTION OUTPUT ;
    USE SIGNAL ;
    PORT
      LAYER M4 ;
        RECT 0.000 47.520 0.192 47.544 ;
    END
  END tap_d[261]
  PIN tap_d[262]
    DIRECTION OUTPUT ;
    USE SIGNAL ;
    PORT
      LAYER M4 ;
        RECT 0.000 47.616 0.192 47.640 ;
    END
  END tap_d[262]
  PIN tap_d[263]
    DIRECTION OUTPUT ;
    USE SIGNAL ;
    PORT
      LAYER M4 ;
        RECT 0.000 47.712 0.192 47.736 ;
    END
  END tap_d[263]
  PIN tap_d[264]
    DIRECTION OUTPUT ;
    USE SIGNAL ;
    PORT
      LAYER M4 ;
        RECT 0.000 47.808 0.192 47.832 ;
    END
  END tap_d[264]
  PIN tap_d[265]
    DIRECTION OUTPUT ;
    USE SIGNAL ;
    PORT
      LAYER M4 ;
        RECT 0.000 47.904 0.192 47.928 ;
    END
  END tap_d[265]
  PIN tap_d[266]
    DIRECTION OUTPUT ;
    USE SIGNAL ;
    PORT
      LAYER M4 ;
        RECT 0.000 48.000 0.192 48.024 ;
    END
  END tap_d[266]
  PIN tap_d[267]
    DIRECTION OUTPUT ;
    USE SIGNAL ;
    PORT
      LAYER M4 ;
        RECT 0.000 48.096 0.192 48.120 ;
    END
  END tap_d[267]
  PIN tap_d[268]
    DIRECTION OUTPUT ;
    USE SIGNAL ;
    PORT
      LAYER M4 ;
        RECT 0.000 48.192 0.192 48.216 ;
    END
  END tap_d[268]
  PIN tap_d[269]
    DIRECTION OUTPUT ;
    USE SIGNAL ;
    PORT
      LAYER M4 ;
        RECT 0.000 48.288 0.192 48.312 ;
    END
  END tap_d[269]
  PIN tap_d[270]
    DIRECTION OUTPUT ;
    USE SIGNAL ;
    PORT
      LAYER M4 ;
        RECT 0.000 48.384 0.192 48.408 ;
    END
  END tap_d[270]
  PIN tap_d[271]
    DIRECTION OUTPUT ;
    USE SIGNAL ;
    PORT
      LAYER M4 ;
        RECT 0.000 48.480 0.192 48.504 ;
    END
  END tap_d[271]
  PIN tap_d[272]
    DIRECTION OUTPUT ;
    USE SIGNAL ;
    PORT
      LAYER M4 ;
        RECT 0.000 48.576 0.192 48.600 ;
    END
  END tap_d[272]
  PIN tap_d[273]
    DIRECTION OUTPUT ;
    USE SIGNAL ;
    PORT
      LAYER M4 ;
        RECT 0.000 48.672 0.192 48.696 ;
    END
  END tap_d[273]
  PIN tap_d[274]
    DIRECTION OUTPUT ;
    USE SIGNAL ;
    PORT
      LAYER M4 ;
        RECT 0.000 48.768 0.192 48.792 ;
    END
  END tap_d[274]
  PIN tap_d[275]
    DIRECTION OUTPUT ;
    USE SIGNAL ;
    PORT
      LAYER M4 ;
        RECT 0.000 48.864 0.192 48.888 ;
    END
  END tap_d[275]
  PIN tap_d[276]
    DIRECTION OUTPUT ;
    USE SIGNAL ;
    PORT
      LAYER M4 ;
        RECT 0.000 48.960 0.192 48.984 ;
    END
  END tap_d[276]
  PIN tap_d[277]
    DIRECTION OUTPUT ;
    USE SIGNAL ;
    PORT
      LAYER M4 ;
        RECT 0.000 49.056 0.192 49.080 ;
    END
  END tap_d[277]
  PIN tap_d[278]
    DIRECTION OUTPUT ;
    USE SIGNAL ;
    PORT
      LAYER M4 ;
        RECT 0.000 49.152 0.192 49.176 ;
    END
  END tap_d[278]
  PIN tap_d[279]
    DIRECTION OUTPUT ;
    USE SIGNAL ;
    PORT
      LAYER M4 ;
        RECT 0.000 49.248 0.192 49.272 ;
    END
  END tap_d[279]
  PIN tap_d[280]
    DIRECTION OUTPUT ;
    USE SIGNAL ;
    PORT
      LAYER M4 ;
        RECT 0.000 49.344 0.192 49.368 ;
    END
  END tap_d[280]
  PIN tap_d[281]
    DIRECTION OUTPUT ;
    USE SIGNAL ;
    PORT
      LAYER M4 ;
        RECT 0.000 49.440 0.192 49.464 ;
    END
  END tap_d[281]
  PIN tap_d[282]
    DIRECTION OUTPUT ;
    USE SIGNAL ;
    PORT
      LAYER M4 ;
        RECT 0.000 49.536 0.192 49.560 ;
    END
  END tap_d[282]
  PIN tap_d[283]
    DIRECTION OUTPUT ;
    USE SIGNAL ;
    PORT
      LAYER M4 ;
        RECT 0.000 49.632 0.192 49.656 ;
    END
  END tap_d[283]
  PIN tap_d[284]
    DIRECTION OUTPUT ;
    USE SIGNAL ;
    PORT
      LAYER M4 ;
        RECT 0.000 49.728 0.192 49.752 ;
    END
  END tap_d[284]
  PIN tap_d[285]
    DIRECTION OUTPUT ;
    USE SIGNAL ;
    PORT
      LAYER M4 ;
        RECT 0.000 49.824 0.192 49.848 ;
    END
  END tap_d[285]
  PIN tap_d[286]
    DIRECTION OUTPUT ;
    USE SIGNAL ;
    PORT
      LAYER M4 ;
        RECT 0.000 49.920 0.192 49.944 ;
    END
  END tap_d[286]
  PIN tap_d[287]
    DIRECTION OUTPUT ;
    USE SIGNAL ;
    PORT
      LAYER M4 ;
        RECT 0.000 50.016 0.192 50.040 ;
    END
  END tap_d[287]
  PIN tap_d[288]
    DIRECTION OUTPUT ;
    USE SIGNAL ;
    PORT
      LAYER M4 ;
        RECT 0.000 50.112 0.192 50.136 ;
    END
  END tap_d[288]
  PIN tap_d[289]
    DIRECTION OUTPUT ;
    USE SIGNAL ;
    PORT
      LAYER M4 ;
        RECT 0.000 50.208 0.192 50.232 ;
    END
  END tap_d[289]
  PIN tap_d[290]
    DIRECTION OUTPUT ;
    USE SIGNAL ;
    PORT
      LAYER M4 ;
        RECT 0.000 50.304 0.192 50.328 ;
    END
  END tap_d[290]
  PIN tap_d[291]
    DIRECTION OUTPUT ;
    USE SIGNAL ;
    PORT
      LAYER M4 ;
        RECT 0.000 50.400 0.192 50.424 ;
    END
  END tap_d[291]
  PIN tap_d[292]
    DIRECTION OUTPUT ;
    USE SIGNAL ;
    PORT
      LAYER M4 ;
        RECT 0.000 50.496 0.192 50.520 ;
    END
  END tap_d[292]
  PIN tap_d[293]
    DIRECTION OUTPUT ;
    USE SIGNAL ;
    PORT
      LAYER M4 ;
        RECT 0.000 50.592 0.192 50.616 ;
    END
  END tap_d[293]
  PIN tap_d[294]
    DIRECTION OUTPUT ;
    USE SIGNAL ;
    PORT
      LAYER M4 ;
        RECT 0.000 50.688 0.192 50.712 ;
    END
  END tap_d[294]
  PIN tap_d[295]
    DIRECTION OUTPUT ;
    USE SIGNAL ;
    PORT
      LAYER M4 ;
        RECT 0.000 50.784 0.192 50.808 ;
    END
  END tap_d[295]
  PIN tap_d[296]
    DIRECTION OUTPUT ;
    USE SIGNAL ;
    PORT
      LAYER M4 ;
        RECT 0.000 50.880 0.192 50.904 ;
    END
  END tap_d[296]
  PIN tap_d[297]
    DIRECTION OUTPUT ;
    USE SIGNAL ;
    PORT
      LAYER M4 ;
        RECT 0.000 50.976 0.192 51.000 ;
    END
  END tap_d[297]
  PIN tap_d[298]
    DIRECTION OUTPUT ;
    USE SIGNAL ;
    PORT
      LAYER M4 ;
        RECT 0.000 51.072 0.192 51.096 ;
    END
  END tap_d[298]
  PIN tap_d[299]
    DIRECTION OUTPUT ;
    USE SIGNAL ;
    PORT
      LAYER M4 ;
        RECT 0.000 51.168 0.192 51.192 ;
    END
  END tap_d[299]
  PIN tap_d[300]
    DIRECTION OUTPUT ;
    USE SIGNAL ;
    PORT
      LAYER M4 ;
        RECT 0.000 51.264 0.192 51.288 ;
    END
  END tap_d[300]
  PIN tap_d[301]
    DIRECTION OUTPUT ;
    USE SIGNAL ;
    PORT
      LAYER M4 ;
        RECT 0.000 51.360 0.192 51.384 ;
    END
  END tap_d[301]
  PIN tap_d[302]
    DIRECTION OUTPUT ;
    USE SIGNAL ;
    PORT
      LAYER M4 ;
        RECT 0.000 51.456 0.192 51.480 ;
    END
  END tap_d[302]
  PIN tap_d[303]
    DIRECTION OUTPUT ;
    USE SIGNAL ;
    PORT
      LAYER M4 ;
        RECT 0.000 51.552 0.192 51.576 ;
    END
  END tap_d[303]
  PIN tap_d[304]
    DIRECTION OUTPUT ;
    USE SIGNAL ;
    PORT
      LAYER M4 ;
        RECT 0.000 51.648 0.192 51.672 ;
    END
  END tap_d[304]
  PIN tap_d[305]
    DIRECTION OUTPUT ;
    USE SIGNAL ;
    PORT
      LAYER M4 ;
        RECT 0.000 51.744 0.192 51.768 ;
    END
  END tap_d[305]
  PIN tap_d[306]
    DIRECTION OUTPUT ;
    USE SIGNAL ;
    PORT
      LAYER M4 ;
        RECT 0.000 51.840 0.192 51.864 ;
    END
  END tap_d[306]
  PIN tap_d[307]
    DIRECTION OUTPUT ;
    USE SIGNAL ;
    PORT
      LAYER M4 ;
        RECT 0.000 51.936 0.192 51.960 ;
    END
  END tap_d[307]
  PIN tap_d[308]
    DIRECTION OUTPUT ;
    USE SIGNAL ;
    PORT
      LAYER M4 ;
        RECT 0.000 52.032 0.192 52.056 ;
    END
  END tap_d[308]
  PIN tap_d[309]
    DIRECTION OUTPUT ;
    USE SIGNAL ;
    PORT
      LAYER M4 ;
        RECT 0.000 52.128 0.192 52.152 ;
    END
  END tap_d[309]
  PIN tap_d[310]
    DIRECTION OUTPUT ;
    USE SIGNAL ;
    PORT
      LAYER M4 ;
        RECT 0.000 52.224 0.192 52.248 ;
    END
  END tap_d[310]
  PIN tap_d[311]
    DIRECTION OUTPUT ;
    USE SIGNAL ;
    PORT
      LAYER M4 ;
        RECT 0.000 52.320 0.192 52.344 ;
    END
  END tap_d[311]
  PIN tap_d[312]
    DIRECTION OUTPUT ;
    USE SIGNAL ;
    PORT
      LAYER M4 ;
        RECT 0.000 52.416 0.192 52.440 ;
    END
  END tap_d[312]
  PIN tap_d[313]
    DIRECTION OUTPUT ;
    USE SIGNAL ;
    PORT
      LAYER M4 ;
        RECT 0.000 52.512 0.192 52.536 ;
    END
  END tap_d[313]
  PIN tap_d[314]
    DIRECTION OUTPUT ;
    USE SIGNAL ;
    PORT
      LAYER M4 ;
        RECT 0.000 52.608 0.192 52.632 ;
    END
  END tap_d[314]
  PIN tap_d[315]
    DIRECTION OUTPUT ;
    USE SIGNAL ;
    PORT
      LAYER M4 ;
        RECT 0.000 52.704 0.192 52.728 ;
    END
  END tap_d[315]
  PIN tap_d[316]
    DIRECTION OUTPUT ;
    USE SIGNAL ;
    PORT
      LAYER M4 ;
        RECT 0.000 52.800 0.192 52.824 ;
    END
  END tap_d[316]
  PIN tap_d[317]
    DIRECTION OUTPUT ;
    USE SIGNAL ;
    PORT
      LAYER M4 ;
        RECT 0.000 52.896 0.192 52.920 ;
    END
  END tap_d[317]
  PIN tap_d[318]
    DIRECTION OUTPUT ;
    USE SIGNAL ;
    PORT
      LAYER M4 ;
        RECT 0.000 52.944 0.192 52.968 ;
    END
  END tap_d[318]
  PIN tap_d[319]
    DIRECTION OUTPUT ;
    USE SIGNAL ;
    PORT
      LAYER M4 ;
        RECT 0.000 53.040 0.192 53.064 ;
    END
  END tap_d[319]
  PIN tap_d[320]
    DIRECTION OUTPUT ;
    USE SIGNAL ;
    PORT
      LAYER M4 ;
        RECT 0.000 53.136 0.192 53.160 ;
    END
  END tap_d[320]
  PIN tap_d[321]
    DIRECTION OUTPUT ;
    USE SIGNAL ;
    PORT
      LAYER M4 ;
        RECT 0.000 53.232 0.192 53.256 ;
    END
  END tap_d[321]
  PIN tap_d[322]
    DIRECTION OUTPUT ;
    USE SIGNAL ;
    PORT
      LAYER M4 ;
        RECT 0.000 53.328 0.192 53.352 ;
    END
  END tap_d[322]
  PIN tap_d[323]
    DIRECTION OUTPUT ;
    USE SIGNAL ;
    PORT
      LAYER M4 ;
        RECT 0.000 53.424 0.192 53.448 ;
    END
  END tap_d[323]
  PIN tap_d[324]
    DIRECTION OUTPUT ;
    USE SIGNAL ;
    PORT
      LAYER M4 ;
        RECT 0.000 53.520 0.192 53.544 ;
    END
  END tap_d[324]
  PIN tap_d[325]
    DIRECTION OUTPUT ;
    USE SIGNAL ;
    PORT
      LAYER M4 ;
        RECT 0.000 53.616 0.192 53.640 ;
    END
  END tap_d[325]
  PIN tap_d[326]
    DIRECTION OUTPUT ;
    USE SIGNAL ;
    PORT
      LAYER M4 ;
        RECT 0.000 53.712 0.192 53.736 ;
    END
  END tap_d[326]
  PIN tap_d[327]
    DIRECTION OUTPUT ;
    USE SIGNAL ;
    PORT
      LAYER M4 ;
        RECT 0.000 53.808 0.192 53.832 ;
    END
  END tap_d[327]
  PIN tap_d[328]
    DIRECTION OUTPUT ;
    USE SIGNAL ;
    PORT
      LAYER M4 ;
        RECT 0.000 53.904 0.192 53.928 ;
    END
  END tap_d[328]
  PIN tap_d[329]
    DIRECTION OUTPUT ;
    USE SIGNAL ;
    PORT
      LAYER M4 ;
        RECT 0.000 54.000 0.192 54.024 ;
    END
  END tap_d[329]
  PIN tap_d[330]
    DIRECTION OUTPUT ;
    USE SIGNAL ;
    PORT
      LAYER M4 ;
        RECT 0.000 54.096 0.192 54.120 ;
    END
  END tap_d[330]
  PIN tap_d[331]
    DIRECTION OUTPUT ;
    USE SIGNAL ;
    PORT
      LAYER M4 ;
        RECT 0.000 54.192 0.192 54.216 ;
    END
  END tap_d[331]
  PIN tap_d[332]
    DIRECTION OUTPUT ;
    USE SIGNAL ;
    PORT
      LAYER M4 ;
        RECT 0.000 54.288 0.192 54.312 ;
    END
  END tap_d[332]
  PIN tap_d[333]
    DIRECTION OUTPUT ;
    USE SIGNAL ;
    PORT
      LAYER M4 ;
        RECT 0.000 54.384 0.192 54.408 ;
    END
  END tap_d[333]
  PIN tap_d[334]
    DIRECTION OUTPUT ;
    USE SIGNAL ;
    PORT
      LAYER M4 ;
        RECT 0.000 54.480 0.192 54.504 ;
    END
  END tap_d[334]
  PIN tap_d[335]
    DIRECTION OUTPUT ;
    USE SIGNAL ;
    PORT
      LAYER M4 ;
        RECT 0.000 54.576 0.192 54.600 ;
    END
  END tap_d[335]
  PIN tap_d[336]
    DIRECTION OUTPUT ;
    USE SIGNAL ;
    PORT
      LAYER M4 ;
        RECT 0.000 54.672 0.192 54.696 ;
    END
  END tap_d[336]
  PIN tap_d[337]
    DIRECTION OUTPUT ;
    USE SIGNAL ;
    PORT
      LAYER M4 ;
        RECT 0.000 54.768 0.192 54.792 ;
    END
  END tap_d[337]
  PIN tap_d[338]
    DIRECTION OUTPUT ;
    USE SIGNAL ;
    PORT
      LAYER M4 ;
        RECT 0.000 54.864 0.192 54.888 ;
    END
  END tap_d[338]
  PIN tap_d[339]
    DIRECTION OUTPUT ;
    USE SIGNAL ;
    PORT
      LAYER M4 ;
        RECT 0.000 54.960 0.192 54.984 ;
    END
  END tap_d[339]
  PIN tap_d[340]
    DIRECTION OUTPUT ;
    USE SIGNAL ;
    PORT
      LAYER M4 ;
        RECT 0.000 55.056 0.192 55.080 ;
    END
  END tap_d[340]
  PIN tap_d[341]
    DIRECTION OUTPUT ;
    USE SIGNAL ;
    PORT
      LAYER M4 ;
        RECT 0.000 55.152 0.192 55.176 ;
    END
  END tap_d[341]
  PIN tap_d[342]
    DIRECTION OUTPUT ;
    USE SIGNAL ;
    PORT
      LAYER M4 ;
        RECT 0.000 55.248 0.192 55.272 ;
    END
  END tap_d[342]
  PIN tap_d[343]
    DIRECTION OUTPUT ;
    USE SIGNAL ;
    PORT
      LAYER M4 ;
        RECT 0.000 55.344 0.192 55.368 ;
    END
  END tap_d[343]
  PIN tap_d[344]
    DIRECTION OUTPUT ;
    USE SIGNAL ;
    PORT
      LAYER M4 ;
        RECT 0.000 55.440 0.192 55.464 ;
    END
  END tap_d[344]
  PIN tap_d[345]
    DIRECTION OUTPUT ;
    USE SIGNAL ;
    PORT
      LAYER M4 ;
        RECT 0.000 55.536 0.192 55.560 ;
    END
  END tap_d[345]
  PIN tap_d[346]
    DIRECTION OUTPUT ;
    USE SIGNAL ;
    PORT
      LAYER M4 ;
        RECT 0.000 55.632 0.192 55.656 ;
    END
  END tap_d[346]
  PIN tap_d[347]
    DIRECTION OUTPUT ;
    USE SIGNAL ;
    PORT
      LAYER M4 ;
        RECT 0.000 55.728 0.192 55.752 ;
    END
  END tap_d[347]
  PIN tap_d[348]
    DIRECTION OUTPUT ;
    USE SIGNAL ;
    PORT
      LAYER M4 ;
        RECT 0.000 55.824 0.192 55.848 ;
    END
  END tap_d[348]
  PIN tap_d[349]
    DIRECTION OUTPUT ;
    USE SIGNAL ;
    PORT
      LAYER M4 ;
        RECT 0.000 55.920 0.192 55.944 ;
    END
  END tap_d[349]
  PIN tap_d[350]
    DIRECTION OUTPUT ;
    USE SIGNAL ;
    PORT
      LAYER M4 ;
        RECT 0.000 56.016 0.192 56.040 ;
    END
  END tap_d[350]
  PIN tap_d[351]
    DIRECTION OUTPUT ;
    USE SIGNAL ;
    PORT
      LAYER M4 ;
        RECT 0.000 56.112 0.192 56.136 ;
    END
  END tap_d[351]
  PIN tap_d[352]
    DIRECTION OUTPUT ;
    USE SIGNAL ;
    PORT
      LAYER M4 ;
        RECT 0.000 56.208 0.192 56.232 ;
    END
  END tap_d[352]
  PIN tap_d[353]
    DIRECTION OUTPUT ;
    USE SIGNAL ;
    PORT
      LAYER M4 ;
        RECT 0.000 56.304 0.192 56.328 ;
    END
  END tap_d[353]
  PIN tap_d[354]
    DIRECTION OUTPUT ;
    USE SIGNAL ;
    PORT
      LAYER M4 ;
        RECT 0.000 56.400 0.192 56.424 ;
    END
  END tap_d[354]
  PIN tap_d[355]
    DIRECTION OUTPUT ;
    USE SIGNAL ;
    PORT
      LAYER M4 ;
        RECT 0.000 56.496 0.192 56.520 ;
    END
  END tap_d[355]
  PIN tap_d[356]
    DIRECTION OUTPUT ;
    USE SIGNAL ;
    PORT
      LAYER M4 ;
        RECT 0.000 56.592 0.192 56.616 ;
    END
  END tap_d[356]
  PIN tap_d[357]
    DIRECTION OUTPUT ;
    USE SIGNAL ;
    PORT
      LAYER M4 ;
        RECT 0.000 56.688 0.192 56.712 ;
    END
  END tap_d[357]
  PIN tap_d[358]
    DIRECTION OUTPUT ;
    USE SIGNAL ;
    PORT
      LAYER M4 ;
        RECT 0.000 56.784 0.192 56.808 ;
    END
  END tap_d[358]
  PIN tap_d[359]
    DIRECTION OUTPUT ;
    USE SIGNAL ;
    PORT
      LAYER M4 ;
        RECT 0.000 56.880 0.192 56.904 ;
    END
  END tap_d[359]
  PIN tap_d[360]
    DIRECTION OUTPUT ;
    USE SIGNAL ;
    PORT
      LAYER M4 ;
        RECT 0.000 56.976 0.192 57.000 ;
    END
  END tap_d[360]
  PIN tap_d[361]
    DIRECTION OUTPUT ;
    USE SIGNAL ;
    PORT
      LAYER M4 ;
        RECT 0.000 57.072 0.192 57.096 ;
    END
  END tap_d[361]
  PIN tap_d[362]
    DIRECTION OUTPUT ;
    USE SIGNAL ;
    PORT
      LAYER M4 ;
        RECT 0.000 57.168 0.192 57.192 ;
    END
  END tap_d[362]
  PIN tap_d[363]
    DIRECTION OUTPUT ;
    USE SIGNAL ;
    PORT
      LAYER M4 ;
        RECT 0.000 57.264 0.192 57.288 ;
    END
  END tap_d[363]
  PIN tap_d[364]
    DIRECTION OUTPUT ;
    USE SIGNAL ;
    PORT
      LAYER M4 ;
        RECT 0.000 57.360 0.192 57.384 ;
    END
  END tap_d[364]
  PIN tap_d[365]
    DIRECTION OUTPUT ;
    USE SIGNAL ;
    PORT
      LAYER M4 ;
        RECT 0.000 57.456 0.192 57.480 ;
    END
  END tap_d[365]
  PIN tap_d[366]
    DIRECTION OUTPUT ;
    USE SIGNAL ;
    PORT
      LAYER M4 ;
        RECT 0.000 57.552 0.192 57.576 ;
    END
  END tap_d[366]
  PIN tap_d[367]
    DIRECTION OUTPUT ;
    USE SIGNAL ;
    PORT
      LAYER M4 ;
        RECT 0.000 57.648 0.192 57.672 ;
    END
  END tap_d[367]
  PIN tap_d[368]
    DIRECTION OUTPUT ;
    USE SIGNAL ;
    PORT
      LAYER M4 ;
        RECT 0.000 57.744 0.192 57.768 ;
    END
  END tap_d[368]
  PIN tap_d[369]
    DIRECTION OUTPUT ;
    USE SIGNAL ;
    PORT
      LAYER M4 ;
        RECT 0.000 57.840 0.192 57.864 ;
    END
  END tap_d[369]
  PIN tap_d[370]
    DIRECTION OUTPUT ;
    USE SIGNAL ;
    PORT
      LAYER M4 ;
        RECT 0.000 57.936 0.192 57.960 ;
    END
  END tap_d[370]
  PIN tap_d[371]
    DIRECTION OUTPUT ;
    USE SIGNAL ;
    PORT
      LAYER M4 ;
        RECT 0.000 58.032 0.192 58.056 ;
    END
  END tap_d[371]
  PIN tap_d[372]
    DIRECTION OUTPUT ;
    USE SIGNAL ;
    PORT
      LAYER M4 ;
        RECT 0.000 58.128 0.192 58.152 ;
    END
  END tap_d[372]
  PIN tap_d[373]
    DIRECTION OUTPUT ;
    USE SIGNAL ;
    PORT
      LAYER M4 ;
        RECT 0.000 58.224 0.192 58.248 ;
    END
  END tap_d[373]
  PIN tap_d[374]
    DIRECTION OUTPUT ;
    USE SIGNAL ;
    PORT
      LAYER M4 ;
        RECT 0.000 58.320 0.192 58.344 ;
    END
  END tap_d[374]
  PIN tap_d[375]
    DIRECTION OUTPUT ;
    USE SIGNAL ;
    PORT
      LAYER M4 ;
        RECT 0.000 58.416 0.192 58.440 ;
    END
  END tap_d[375]
  PIN tap_d[376]
    DIRECTION OUTPUT ;
    USE SIGNAL ;
    PORT
      LAYER M4 ;
        RECT 0.000 58.512 0.192 58.536 ;
    END
  END tap_d[376]
  PIN tap_d[377]
    DIRECTION OUTPUT ;
    USE SIGNAL ;
    PORT
      LAYER M4 ;
        RECT 0.000 58.608 0.192 58.632 ;
    END
  END tap_d[377]
  PIN tap_d[378]
    DIRECTION OUTPUT ;
    USE SIGNAL ;
    PORT
      LAYER M4 ;
        RECT 0.000 58.704 0.192 58.728 ;
    END
  END tap_d[378]
  PIN tap_d[379]
    DIRECTION OUTPUT ;
    USE SIGNAL ;
    PORT
      LAYER M4 ;
        RECT 0.000 58.800 0.192 58.824 ;
    END
  END tap_d[379]
  PIN tap_d[380]
    DIRECTION OUTPUT ;
    USE SIGNAL ;
    PORT
      LAYER M4 ;
        RECT 0.000 58.896 0.192 58.920 ;
    END
  END tap_d[380]
  PIN tap_d[381]
    DIRECTION OUTPUT ;
    USE SIGNAL ;
    PORT
      LAYER M4 ;
        RECT 0.000 58.992 0.192 59.016 ;
    END
  END tap_d[381]
  PIN tap_d[382]
    DIRECTION OUTPUT ;
    USE SIGNAL ;
    PORT
      LAYER M4 ;
        RECT 0.000 59.088 0.192 59.112 ;
    END
  END tap_d[382]
  PIN tap_d[383]
    DIRECTION OUTPUT ;
    USE SIGNAL ;
    PORT
      LAYER M4 ;
        RECT 0.000 59.184 0.192 59.208 ;
    END
  END tap_d[383]
  PIN tap_d[384]
    DIRECTION OUTPUT ;
    USE SIGNAL ;
    PORT
      LAYER M4 ;
        RECT 0.000 59.280 0.192 59.304 ;
    END
  END tap_d[384]
  PIN tap_d[385]
    DIRECTION OUTPUT ;
    USE SIGNAL ;
    PORT
      LAYER M4 ;
        RECT 0.000 59.376 0.192 59.400 ;
    END
  END tap_d[385]
  PIN tap_d[386]
    DIRECTION OUTPUT ;
    USE SIGNAL ;
    PORT
      LAYER M4 ;
        RECT 0.000 59.472 0.192 59.496 ;
    END
  END tap_d[386]
  PIN tap_d[387]
    DIRECTION OUTPUT ;
    USE SIGNAL ;
    PORT
      LAYER M4 ;
        RECT 0.000 59.568 0.192 59.592 ;
    END
  END tap_d[387]
  PIN tap_d[388]
    DIRECTION OUTPUT ;
    USE SIGNAL ;
    PORT
      LAYER M4 ;
        RECT 0.000 59.664 0.192 59.688 ;
    END
  END tap_d[388]
  PIN tap_d[389]
    DIRECTION OUTPUT ;
    USE SIGNAL ;
    PORT
      LAYER M4 ;
        RECT 0.000 59.760 0.192 59.784 ;
    END
  END tap_d[389]
  PIN tap_d[390]
    DIRECTION OUTPUT ;
    USE SIGNAL ;
    PORT
      LAYER M4 ;
        RECT 0.000 59.856 0.192 59.880 ;
    END
  END tap_d[390]
  PIN tap_d[391]
    DIRECTION OUTPUT ;
    USE SIGNAL ;
    PORT
      LAYER M4 ;
        RECT 0.000 59.952 0.192 59.976 ;
    END
  END tap_d[391]
  PIN tap_d[392]
    DIRECTION OUTPUT ;
    USE SIGNAL ;
    PORT
      LAYER M4 ;
        RECT 0.000 60.048 0.192 60.072 ;
    END
  END tap_d[392]
  PIN tap_d[393]
    DIRECTION OUTPUT ;
    USE SIGNAL ;
    PORT
      LAYER M4 ;
        RECT 0.000 60.144 0.192 60.168 ;
    END
  END tap_d[393]
  PIN tap_d[394]
    DIRECTION OUTPUT ;
    USE SIGNAL ;
    PORT
      LAYER M4 ;
        RECT 0.000 60.240 0.192 60.264 ;
    END
  END tap_d[394]
  PIN tap_d[395]
    DIRECTION OUTPUT ;
    USE SIGNAL ;
    PORT
      LAYER M4 ;
        RECT 0.000 60.336 0.192 60.360 ;
    END
  END tap_d[395]
  PIN tap_d[396]
    DIRECTION OUTPUT ;
    USE SIGNAL ;
    PORT
      LAYER M4 ;
        RECT 0.000 60.432 0.192 60.456 ;
    END
  END tap_d[396]
  PIN tap_d[397]
    DIRECTION OUTPUT ;
    USE SIGNAL ;
    PORT
      LAYER M4 ;
        RECT 0.000 60.528 0.192 60.552 ;
    END
  END tap_d[397]
  PIN tap_d[398]
    DIRECTION OUTPUT ;
    USE SIGNAL ;
    PORT
      LAYER M4 ;
        RECT 0.000 60.624 0.192 60.648 ;
    END
  END tap_d[398]
  PIN tap_d[399]
    DIRECTION OUTPUT ;
    USE SIGNAL ;
    PORT
      LAYER M4 ;
        RECT 0.000 60.720 0.192 60.744 ;
    END
  END tap_d[399]
  PIN tap_d[400]
    DIRECTION OUTPUT ;
    USE SIGNAL ;
    PORT
      LAYER M4 ;
        RECT 0.000 60.816 0.192 60.840 ;
    END
  END tap_d[400]
  PIN tap_d[401]
    DIRECTION OUTPUT ;
    USE SIGNAL ;
    PORT
      LAYER M4 ;
        RECT 0.000 60.912 0.192 60.936 ;
    END
  END tap_d[401]
  PIN tap_d[402]
    DIRECTION OUTPUT ;
    USE SIGNAL ;
    PORT
      LAYER M4 ;
        RECT 0.000 61.008 0.192 61.032 ;
    END
  END tap_d[402]
  PIN tap_d[403]
    DIRECTION OUTPUT ;
    USE SIGNAL ;
    PORT
      LAYER M4 ;
        RECT 0.000 61.104 0.192 61.128 ;
    END
  END tap_d[403]
  PIN tap_d[404]
    DIRECTION OUTPUT ;
    USE SIGNAL ;
    PORT
      LAYER M4 ;
        RECT 0.000 61.200 0.192 61.224 ;
    END
  END tap_d[404]
  PIN tap_d[405]
    DIRECTION OUTPUT ;
    USE SIGNAL ;
    PORT
      LAYER M4 ;
        RECT 0.000 61.296 0.192 61.320 ;
    END
  END tap_d[405]
  PIN tap_d[406]
    DIRECTION OUTPUT ;
    USE SIGNAL ;
    PORT
      LAYER M4 ;
        RECT 0.000 61.392 0.192 61.416 ;
    END
  END tap_d[406]
  PIN tap_d[407]
    DIRECTION OUTPUT ;
    USE SIGNAL ;
    PORT
      LAYER M4 ;
        RECT 0.000 61.488 0.192 61.512 ;
    END
  END tap_d[407]
  PIN tap_d[408]
    DIRECTION OUTPUT ;
    USE SIGNAL ;
    PORT
      LAYER M4 ;
        RECT 0.000 61.584 0.192 61.608 ;
    END
  END tap_d[408]
  PIN tap_d[409]
    DIRECTION OUTPUT ;
    USE SIGNAL ;
    PORT
      LAYER M4 ;
        RECT 0.000 61.680 0.192 61.704 ;
    END
  END tap_d[409]
  PIN tap_d[410]
    DIRECTION OUTPUT ;
    USE SIGNAL ;
    PORT
      LAYER M4 ;
        RECT 0.000 61.776 0.192 61.800 ;
    END
  END tap_d[410]
  PIN tap_d[411]
    DIRECTION OUTPUT ;
    USE SIGNAL ;
    PORT
      LAYER M4 ;
        RECT 0.000 61.872 0.192 61.896 ;
    END
  END tap_d[411]
  PIN tap_d[412]
    DIRECTION OUTPUT ;
    USE SIGNAL ;
    PORT
      LAYER M4 ;
        RECT 0.000 61.968 0.192 61.992 ;
    END
  END tap_d[412]
  PIN tap_d[413]
    DIRECTION OUTPUT ;
    USE SIGNAL ;
    PORT
      LAYER M4 ;
        RECT 0.000 62.064 0.192 62.088 ;
    END
  END tap_d[413]
  PIN tap_d[414]
    DIRECTION OUTPUT ;
    USE SIGNAL ;
    PORT
      LAYER M4 ;
        RECT 0.000 62.160 0.192 62.184 ;
    END
  END tap_d[414]
  PIN tap_d[415]
    DIRECTION OUTPUT ;
    USE SIGNAL ;
    PORT
      LAYER M4 ;
        RECT 0.000 62.256 0.192 62.280 ;
    END
  END tap_d[415]
  PIN tap_d[416]
    DIRECTION OUTPUT ;
    USE SIGNAL ;
    PORT
      LAYER M4 ;
        RECT 0.000 62.352 0.192 62.376 ;
    END
  END tap_d[416]
  PIN tap_d[417]
    DIRECTION OUTPUT ;
    USE SIGNAL ;
    PORT
      LAYER M4 ;
        RECT 0.000 62.448 0.192 62.472 ;
    END
  END tap_d[417]
  PIN tap_d[418]
    DIRECTION OUTPUT ;
    USE SIGNAL ;
    PORT
      LAYER M4 ;
        RECT 0.000 62.544 0.192 62.568 ;
    END
  END tap_d[418]
  PIN tap_d[419]
    DIRECTION OUTPUT ;
    USE SIGNAL ;
    PORT
      LAYER M4 ;
        RECT 0.000 62.640 0.192 62.664 ;
    END
  END tap_d[419]
  PIN tap_d[420]
    DIRECTION OUTPUT ;
    USE SIGNAL ;
    PORT
      LAYER M4 ;
        RECT 0.000 62.736 0.192 62.760 ;
    END
  END tap_d[420]
  PIN tap_d[421]
    DIRECTION OUTPUT ;
    USE SIGNAL ;
    PORT
      LAYER M4 ;
        RECT 0.000 62.832 0.192 62.856 ;
    END
  END tap_d[421]
  PIN tap_d[422]
    DIRECTION OUTPUT ;
    USE SIGNAL ;
    PORT
      LAYER M4 ;
        RECT 0.000 62.928 0.192 62.952 ;
    END
  END tap_d[422]
  PIN tap_d[423]
    DIRECTION OUTPUT ;
    USE SIGNAL ;
    PORT
      LAYER M4 ;
        RECT 0.000 63.024 0.192 63.048 ;
    END
  END tap_d[423]
  PIN tap_d[424]
    DIRECTION OUTPUT ;
    USE SIGNAL ;
    PORT
      LAYER M4 ;
        RECT 0.000 63.120 0.192 63.144 ;
    END
  END tap_d[424]
  PIN tap_d[425]
    DIRECTION OUTPUT ;
    USE SIGNAL ;
    PORT
      LAYER M4 ;
        RECT 0.000 63.216 0.192 63.240 ;
    END
  END tap_d[425]
  PIN tap_d[426]
    DIRECTION OUTPUT ;
    USE SIGNAL ;
    PORT
      LAYER M4 ;
        RECT 0.000 63.312 0.192 63.336 ;
    END
  END tap_d[426]
  PIN tap_d[427]
    DIRECTION OUTPUT ;
    USE SIGNAL ;
    PORT
      LAYER M4 ;
        RECT 0.000 63.408 0.192 63.432 ;
    END
  END tap_d[427]
  PIN tap_d[428]
    DIRECTION OUTPUT ;
    USE SIGNAL ;
    PORT
      LAYER M4 ;
        RECT 0.000 63.504 0.192 63.528 ;
    END
  END tap_d[428]
  PIN tap_d[429]
    DIRECTION OUTPUT ;
    USE SIGNAL ;
    PORT
      LAYER M4 ;
        RECT 0.000 63.600 0.192 63.624 ;
    END
  END tap_d[429]
  PIN tap_d[430]
    DIRECTION OUTPUT ;
    USE SIGNAL ;
    PORT
      LAYER M4 ;
        RECT 0.000 63.696 0.192 63.720 ;
    END
  END tap_d[430]
  PIN tap_d[431]
    DIRECTION OUTPUT ;
    USE SIGNAL ;
    PORT
      LAYER M4 ;
        RECT 0.000 63.792 0.192 63.816 ;
    END
  END tap_d[431]
  PIN tap_d[432]
    DIRECTION OUTPUT ;
    USE SIGNAL ;
    PORT
      LAYER M4 ;
        RECT 0.000 63.888 0.192 63.912 ;
    END
  END tap_d[432]
  PIN tap_d[433]
    DIRECTION OUTPUT ;
    USE SIGNAL ;
    PORT
      LAYER M4 ;
        RECT 0.000 63.984 0.192 64.008 ;
    END
  END tap_d[433]
  PIN tap_d[434]
    DIRECTION OUTPUT ;
    USE SIGNAL ;
    PORT
      LAYER M4 ;
        RECT 0.000 64.080 0.192 64.104 ;
    END
  END tap_d[434]
  PIN tap_d[435]
    DIRECTION OUTPUT ;
    USE SIGNAL ;
    PORT
      LAYER M4 ;
        RECT 0.000 64.176 0.192 64.200 ;
    END
  END tap_d[435]
  PIN tap_d[436]
    DIRECTION OUTPUT ;
    USE SIGNAL ;
    PORT
      LAYER M4 ;
        RECT 0.000 64.272 0.192 64.296 ;
    END
  END tap_d[436]
  PIN tap_d[437]
    DIRECTION OUTPUT ;
    USE SIGNAL ;
    PORT
      LAYER M4 ;
        RECT 0.000 64.368 0.192 64.392 ;
    END
  END tap_d[437]
  PIN tap_d[438]
    DIRECTION OUTPUT ;
    USE SIGNAL ;
    PORT
      LAYER M4 ;
        RECT 0.000 64.464 0.192 64.488 ;
    END
  END tap_d[438]
  PIN tap_d[439]
    DIRECTION OUTPUT ;
    USE SIGNAL ;
    PORT
      LAYER M4 ;
        RECT 0.000 64.560 0.192 64.584 ;
    END
  END tap_d[439]
  PIN tap_d[440]
    DIRECTION OUTPUT ;
    USE SIGNAL ;
    PORT
      LAYER M4 ;
        RECT 0.000 64.656 0.192 64.680 ;
    END
  END tap_d[440]
  PIN tap_d[441]
    DIRECTION OUTPUT ;
    USE SIGNAL ;
    PORT
      LAYER M4 ;
        RECT 0.000 64.752 0.192 64.776 ;
    END
  END tap_d[441]
  PIN tap_d[442]
    DIRECTION OUTPUT ;
    USE SIGNAL ;
    PORT
      LAYER M4 ;
        RECT 0.000 64.848 0.192 64.872 ;
    END
  END tap_d[442]
  PIN tap_d[443]
    DIRECTION OUTPUT ;
    USE SIGNAL ;
    PORT
      LAYER M4 ;
        RECT 0.000 64.944 0.192 64.968 ;
    END
  END tap_d[443]
  PIN tap_d[444]
    DIRECTION OUTPUT ;
    USE SIGNAL ;
    PORT
      LAYER M4 ;
        RECT 0.000 65.040 0.192 65.064 ;
    END
  END tap_d[444]
  PIN tap_d[445]
    DIRECTION OUTPUT ;
    USE SIGNAL ;
    PORT
      LAYER M4 ;
        RECT 0.000 65.136 0.192 65.160 ;
    END
  END tap_d[445]
  PIN tap_d[446]
    DIRECTION OUTPUT ;
    USE SIGNAL ;
    PORT
      LAYER M4 ;
        RECT 0.000 65.232 0.192 65.256 ;
    END
  END tap_d[446]
  PIN tap_d[447]
    DIRECTION OUTPUT ;
    USE SIGNAL ;
    PORT
      LAYER M4 ;
        RECT 0.000 65.328 0.192 65.352 ;
    END
  END tap_d[447]
  PIN tap_d[448]
    DIRECTION OUTPUT ;
    USE SIGNAL ;
    PORT
      LAYER M4 ;
        RECT 0.000 65.424 0.192 65.448 ;
    END
  END tap_d[448]
  PIN tap_d[449]
    DIRECTION OUTPUT ;
    USE SIGNAL ;
    PORT
      LAYER M4 ;
        RECT 0.000 65.520 0.192 65.544 ;
    END
  END tap_d[449]
  PIN tap_d[450]
    DIRECTION OUTPUT ;
    USE SIGNAL ;
    PORT
      LAYER M4 ;
        RECT 0.000 65.616 0.192 65.640 ;
    END
  END tap_d[450]
  PIN tap_d[451]
    DIRECTION OUTPUT ;
    USE SIGNAL ;
    PORT
      LAYER M4 ;
        RECT 0.000 65.712 0.192 65.736 ;
    END
  END tap_d[451]
  PIN tap_d[452]
    DIRECTION OUTPUT ;
    USE SIGNAL ;
    PORT
      LAYER M4 ;
        RECT 0.000 65.808 0.192 65.832 ;
    END
  END tap_d[452]
  PIN tap_d[453]
    DIRECTION OUTPUT ;
    USE SIGNAL ;
    PORT
      LAYER M4 ;
        RECT 0.000 65.904 0.192 65.928 ;
    END
  END tap_d[453]
  PIN tap_d[454]
    DIRECTION OUTPUT ;
    USE SIGNAL ;
    PORT
      LAYER M4 ;
        RECT 0.000 66.000 0.192 66.024 ;
    END
  END tap_d[454]
  PIN tap_d[455]
    DIRECTION OUTPUT ;
    USE SIGNAL ;
    PORT
      LAYER M4 ;
        RECT 0.000 66.096 0.192 66.120 ;
    END
  END tap_d[455]
  PIN tap_d[456]
    DIRECTION OUTPUT ;
    USE SIGNAL ;
    PORT
      LAYER M4 ;
        RECT 0.000 66.192 0.192 66.216 ;
    END
  END tap_d[456]
  PIN tap_d[457]
    DIRECTION OUTPUT ;
    USE SIGNAL ;
    PORT
      LAYER M4 ;
        RECT 0.000 66.288 0.192 66.312 ;
    END
  END tap_d[457]
  PIN tap_d[458]
    DIRECTION OUTPUT ;
    USE SIGNAL ;
    PORT
      LAYER M4 ;
        RECT 0.000 66.384 0.192 66.408 ;
    END
  END tap_d[458]
  PIN tap_d[459]
    DIRECTION OUTPUT ;
    USE SIGNAL ;
    PORT
      LAYER M4 ;
        RECT 0.000 66.480 0.192 66.504 ;
    END
  END tap_d[459]
  PIN tap_d[460]
    DIRECTION OUTPUT ;
    USE SIGNAL ;
    PORT
      LAYER M4 ;
        RECT 0.000 66.576 0.192 66.600 ;
    END
  END tap_d[460]
  PIN tap_d[461]
    DIRECTION OUTPUT ;
    USE SIGNAL ;
    PORT
      LAYER M4 ;
        RECT 0.000 66.672 0.192 66.696 ;
    END
  END tap_d[461]
  PIN tap_d[462]
    DIRECTION OUTPUT ;
    USE SIGNAL ;
    PORT
      LAYER M4 ;
        RECT 0.000 66.768 0.192 66.792 ;
    END
  END tap_d[462]
  PIN tap_d[463]
    DIRECTION OUTPUT ;
    USE SIGNAL ;
    PORT
      LAYER M4 ;
        RECT 0.000 66.864 0.192 66.888 ;
    END
  END tap_d[463]
  PIN tap_d[464]
    DIRECTION OUTPUT ;
    USE SIGNAL ;
    PORT
      LAYER M4 ;
        RECT 0.000 66.960 0.192 66.984 ;
    END
  END tap_d[464]
  PIN tap_d[465]
    DIRECTION OUTPUT ;
    USE SIGNAL ;
    PORT
      LAYER M4 ;
        RECT 0.000 67.056 0.192 67.080 ;
    END
  END tap_d[465]
  PIN tap_d[466]
    DIRECTION OUTPUT ;
    USE SIGNAL ;
    PORT
      LAYER M4 ;
        RECT 0.000 67.152 0.192 67.176 ;
    END
  END tap_d[466]
  PIN tap_d[467]
    DIRECTION OUTPUT ;
    USE SIGNAL ;
    PORT
      LAYER M4 ;
        RECT 0.000 67.248 0.192 67.272 ;
    END
  END tap_d[467]
  PIN tap_d[468]
    DIRECTION OUTPUT ;
    USE SIGNAL ;
    PORT
      LAYER M4 ;
        RECT 0.000 67.344 0.192 67.368 ;
    END
  END tap_d[468]
  PIN tap_d[469]
    DIRECTION OUTPUT ;
    USE SIGNAL ;
    PORT
      LAYER M4 ;
        RECT 0.000 67.440 0.192 67.464 ;
    END
  END tap_d[469]
  PIN tap_d[470]
    DIRECTION OUTPUT ;
    USE SIGNAL ;
    PORT
      LAYER M4 ;
        RECT 0.000 67.536 0.192 67.560 ;
    END
  END tap_d[470]
  PIN tap_d[471]
    DIRECTION OUTPUT ;
    USE SIGNAL ;
    PORT
      LAYER M4 ;
        RECT 0.000 67.632 0.192 67.656 ;
    END
  END tap_d[471]
  PIN tap_d[472]
    DIRECTION OUTPUT ;
    USE SIGNAL ;
    PORT
      LAYER M4 ;
        RECT 0.000 67.728 0.192 67.752 ;
    END
  END tap_d[472]
  PIN tap_d[473]
    DIRECTION OUTPUT ;
    USE SIGNAL ;
    PORT
      LAYER M4 ;
        RECT 0.000 67.824 0.192 67.848 ;
    END
  END tap_d[473]
  PIN tap_d[474]
    DIRECTION OUTPUT ;
    USE SIGNAL ;
    PORT
      LAYER M4 ;
        RECT 0.000 67.920 0.192 67.944 ;
    END
  END tap_d[474]
  PIN tap_d[475]
    DIRECTION OUTPUT ;
    USE SIGNAL ;
    PORT
      LAYER M4 ;
        RECT 0.000 68.016 0.192 68.040 ;
    END
  END tap_d[475]
  PIN tap_d[476]
    DIRECTION OUTPUT ;
    USE SIGNAL ;
    PORT
      LAYER M4 ;
        RECT 0.000 68.112 0.192 68.136 ;
    END
  END tap_d[476]
  PIN tap_d[477]
    DIRECTION OUTPUT ;
    USE SIGNAL ;
    PORT
      LAYER M4 ;
        RECT 0.000 68.208 0.192 68.232 ;
    END
  END tap_d[477]
  PIN tap_d[478]
    DIRECTION OUTPUT ;
    USE SIGNAL ;
    PORT
      LAYER M4 ;
        RECT 0.000 68.304 0.192 68.328 ;
    END
  END tap_d[478]
  PIN tap_d[479]
    DIRECTION OUTPUT ;
    USE SIGNAL ;
    PORT
      LAYER M4 ;
        RECT 0.000 68.400 0.192 68.424 ;
    END
  END tap_d[479]
  PIN tap_d[480]
    DIRECTION OUTPUT ;
    USE SIGNAL ;
    PORT
      LAYER M4 ;
        RECT 0.000 68.496 0.192 68.520 ;
    END
  END tap_d[480]
  PIN tap_d[481]
    DIRECTION OUTPUT ;
    USE SIGNAL ;
    PORT
      LAYER M4 ;
        RECT 0.000 68.592 0.192 68.616 ;
    END
  END tap_d[481]
  PIN tap_d[482]
    DIRECTION OUTPUT ;
    USE SIGNAL ;
    PORT
      LAYER M4 ;
        RECT 0.000 68.688 0.192 68.712 ;
    END
  END tap_d[482]
  PIN tap_d[483]
    DIRECTION OUTPUT ;
    USE SIGNAL ;
    PORT
      LAYER M4 ;
        RECT 0.000 68.784 0.192 68.808 ;
    END
  END tap_d[483]
  PIN tap_d[484]
    DIRECTION OUTPUT ;
    USE SIGNAL ;
    PORT
      LAYER M4 ;
        RECT 0.000 68.880 0.192 68.904 ;
    END
  END tap_d[484]
  PIN tap_d[485]
    DIRECTION OUTPUT ;
    USE SIGNAL ;
    PORT
      LAYER M4 ;
        RECT 0.000 68.976 0.192 69.000 ;
    END
  END tap_d[485]
  PIN tap_d[486]
    DIRECTION OUTPUT ;
    USE SIGNAL ;
    PORT
      LAYER M4 ;
        RECT 0.000 69.072 0.192 69.096 ;
    END
  END tap_d[486]
  PIN tap_d[487]
    DIRECTION OUTPUT ;
    USE SIGNAL ;
    PORT
      LAYER M4 ;
        RECT 0.000 69.168 0.192 69.192 ;
    END
  END tap_d[487]
  PIN tap_d[488]
    DIRECTION OUTPUT ;
    USE SIGNAL ;
    PORT
      LAYER M4 ;
        RECT 0.000 69.264 0.192 69.288 ;
    END
  END tap_d[488]
  PIN tap_d[489]
    DIRECTION OUTPUT ;
    USE SIGNAL ;
    PORT
      LAYER M4 ;
        RECT 0.000 69.360 0.192 69.384 ;
    END
  END tap_d[489]
  PIN tap_d[490]
    DIRECTION OUTPUT ;
    USE SIGNAL ;
    PORT
      LAYER M4 ;
        RECT 0.000 69.456 0.192 69.480 ;
    END
  END tap_d[490]
  PIN tap_d[491]
    DIRECTION OUTPUT ;
    USE SIGNAL ;
    PORT
      LAYER M4 ;
        RECT 0.000 69.552 0.192 69.576 ;
    END
  END tap_d[491]
  PIN tap_d[492]
    DIRECTION OUTPUT ;
    USE SIGNAL ;
    PORT
      LAYER M4 ;
        RECT 0.000 69.648 0.192 69.672 ;
    END
  END tap_d[492]
  PIN tap_d[493]
    DIRECTION OUTPUT ;
    USE SIGNAL ;
    PORT
      LAYER M4 ;
        RECT 0.000 69.744 0.192 69.768 ;
    END
  END tap_d[493]
  PIN tap_d[494]
    DIRECTION OUTPUT ;
    USE SIGNAL ;
    PORT
      LAYER M4 ;
        RECT 0.000 69.840 0.192 69.864 ;
    END
  END tap_d[494]
  PIN tap_d[495]
    DIRECTION OUTPUT ;
    USE SIGNAL ;
    PORT
      LAYER M4 ;
        RECT 0.000 69.936 0.192 69.960 ;
    END
  END tap_d[495]
  PIN tap_d[496]
    DIRECTION OUTPUT ;
    USE SIGNAL ;
    PORT
      LAYER M4 ;
        RECT 0.000 70.032 0.192 70.056 ;
    END
  END tap_d[496]
  PIN tap_d[497]
    DIRECTION OUTPUT ;
    USE SIGNAL ;
    PORT
      LAYER M4 ;
        RECT 0.000 70.128 0.192 70.152 ;
    END
  END tap_d[497]
  PIN tap_d[498]
    DIRECTION OUTPUT ;
    USE SIGNAL ;
    PORT
      LAYER M4 ;
        RECT 0.000 70.224 0.192 70.248 ;
    END
  END tap_d[498]
  PIN tap_d[499]
    DIRECTION OUTPUT ;
    USE SIGNAL ;
    PORT
      LAYER M4 ;
        RECT 0.000 70.320 0.192 70.344 ;
    END
  END tap_d[499]
  PIN tap_d[500]
    DIRECTION OUTPUT ;
    USE SIGNAL ;
    PORT
      LAYER M4 ;
        RECT 0.000 70.416 0.192 70.440 ;
    END
  END tap_d[500]
  PIN tap_d[501]
    DIRECTION OUTPUT ;
    USE SIGNAL ;
    PORT
      LAYER M4 ;
        RECT 0.000 70.512 0.192 70.536 ;
    END
  END tap_d[501]
  PIN tap_d[502]
    DIRECTION OUTPUT ;
    USE SIGNAL ;
    PORT
      LAYER M4 ;
        RECT 0.000 70.608 0.192 70.632 ;
    END
  END tap_d[502]
  PIN tap_d[503]
    DIRECTION OUTPUT ;
    USE SIGNAL ;
    PORT
      LAYER M4 ;
        RECT 0.000 70.704 0.192 70.728 ;
    END
  END tap_d[503]
  PIN tap_d[504]
    DIRECTION OUTPUT ;
    USE SIGNAL ;
    PORT
      LAYER M4 ;
        RECT 0.000 70.800 0.192 70.824 ;
    END
  END tap_d[504]
  PIN tap_d[505]
    DIRECTION OUTPUT ;
    USE SIGNAL ;
    PORT
      LAYER M4 ;
        RECT 0.000 70.896 0.192 70.920 ;
    END
  END tap_d[505]
  PIN tap_d[506]
    DIRECTION OUTPUT ;
    USE SIGNAL ;
    PORT
      LAYER M4 ;
        RECT 0.000 70.992 0.192 71.016 ;
    END
  END tap_d[506]
  PIN tap_d[507]
    DIRECTION OUTPUT ;
    USE SIGNAL ;
    PORT
      LAYER M4 ;
        RECT 0.000 71.088 0.192 71.112 ;
    END
  END tap_d[507]
  PIN VDD
    DIRECTION INOUT ;
    USE POWER ;
    PORT
      LAYER M5 ;
        RECT 2.460 0.500 2.580 85.900 ;
        RECT 7.860 0.500 7.980 85.900 ;
        RECT 13.260 0.500 13.380 85.900 ;
        RECT 18.660 0.500 18.780 85.900 ;
        RECT 24.060 0.500 24.180 85.900 ;
        RECT 29.460 0.500 29.580 85.900 ;
    END
  END VDD
  PIN VSS
    DIRECTION INOUT ;
    USE GROUND ;
    PORT
      LAYER M5 ;
        RECT 2.652 0.500 2.772 85.900 ;
        RECT 8.052 0.500 8.172 85.900 ;
        RECT 13.452 0.500 13.572 85.900 ;
        RECT 18.852 0.500 18.972 85.900 ;
        RECT 24.252 0.500 24.372 85.900 ;
        RECT 29.652 0.500 29.772 85.900 ;
    END
  END VSS
  OBS
    LAYER M1 ;
      RECT 0.500 0.500 34.060 85.900 ;
    LAYER M2 ;
      RECT 0.500 0.500 34.060 85.900 ;
    LAYER M3 ;
      RECT 0.500 0.500 34.060 85.900 ;
    LAYER M4 ;
      RECT 0.500 0.500 34.060 85.900 ;
    LAYER M5 ;
      RECT 0.500 0.900 2.460 85.500 ;
      RECT 2.580 0.900 2.652 85.500 ;
      RECT 2.772 0.900 7.860 85.500 ;
      RECT 7.980 0.900 8.052 85.500 ;
      RECT 8.172 0.900 13.260 85.500 ;
      RECT 13.380 0.900 13.452 85.500 ;
      RECT 13.572 0.900 18.660 85.500 ;
      RECT 18.780 0.900 18.852 85.500 ;
      RECT 18.972 0.900 24.060 85.500 ;
      RECT 24.180 0.900 24.252 85.500 ;
      RECT 24.372 0.900 29.460 85.500 ;
      RECT 29.580 0.900 29.652 85.500 ;
      RECT 29.772 0.900 34.060 85.500 ;
  END
END qfd_c_xstnw
END LIBRARY
